# sg13g2_stdcell_hv -- thick-oxide (3.3 V) standard cells
# Generated by work/gen_lef.py from the drawn GDS; see that script
# for what is measured and what is inherited from the thin-oxide
# LEF. Uses the PDK tech LEF (sg13g2_tech.lef) layers.
VERSION 5.8 ;
BUSBITCHARS "[]" ;
DIVIDERCHAR "/" ;

SITE  CoreSiteHV
    CLASS       CORE ;
    SYMMETRY    Y ;
    SIZE        0.48 BY 7.14 ;
END  CoreSiteHV

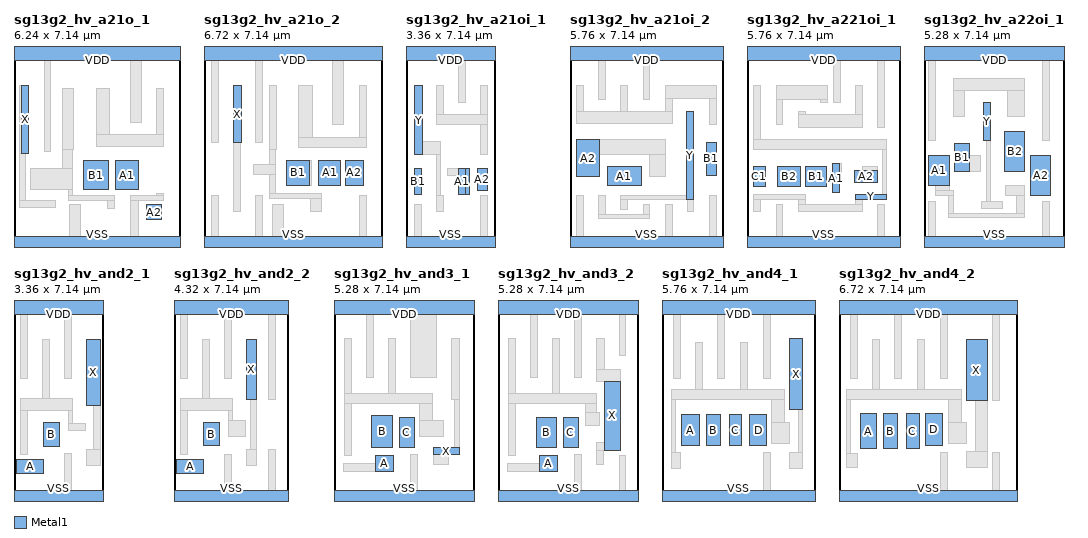
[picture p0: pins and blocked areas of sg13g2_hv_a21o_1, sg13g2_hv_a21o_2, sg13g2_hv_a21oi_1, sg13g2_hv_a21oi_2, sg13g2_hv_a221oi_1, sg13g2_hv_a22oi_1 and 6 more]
MACRO sg13g2_hv_a21o_1
  CLASS CORE ;
  ORIGIN 0 0 ;
  FOREIGN sg13g2_hv_a21o_1 0 0 ;
  SIZE 6.24 BY 7.14 ;
  SYMMETRY X Y ;
  SITE CoreSiteHV ;
  PIN A2
    DIRECTION INPUT ;
    USE SIGNAL ;
    ANTENNAMODEL OXIDE1 ;
      ANTENNAGATEAREA 1.3680 LAYER Metal1 ;
    PORT
      LAYER Metal1 ;
        RECT 4.965 0.835 5.55 1.395 ;
    END
  END A2
  PIN A1
    DIRECTION INPUT ;
    USE SIGNAL ;
    ANTENNAMODEL OXIDE1 ;
      ANTENNAGATEAREA 1.3680 LAYER Metal1 ;
    PORT
      LAYER Metal1 ;
        RECT 3.825 1.955 4.665 3.08 ;
    END
  END A1
  PIN B1
    DIRECTION INPUT ;
    USE SIGNAL ;
    ANTENNAMODEL OXIDE1 ;
      ANTENNAGATEAREA 1.3680 LAYER Metal1 ;
    PORT
      LAYER Metal1 ;
        RECT 2.63 1.955 3.54 3.08 ;
    END
  END B1
  PIN X
    DIRECTION OUTPUT ;
    USE SIGNAL ;
    ANTENNADIFFAREA 1.1662 LAYER Metal1 ;
    PORT
      LAYER Metal1 ;
        RECT 0.285 3.31 0.56 5.865 ;
    END
  END X
  PIN VDD
    DIRECTION INOUT ;
    USE POWER ;
    SHAPE ABUTMENT ;
    NETEXPR "VDD VDD!" ;
    PORT
      LAYER Metal1 ;
        RECT 0 6.825 6.24 7.36 ;
    END
  END VDD
  PIN VSS
    DIRECTION INOUT ;
    USE GROUND ;
    SHAPE ABUTMENT ;
    NETEXPR "VSS VSS!" ;
    PORT
      LAYER Metal1 ;
        RECT 0 -0.22 6.24 0.22 ;
    END
  END VSS
  OBS
      LAYER Metal1 ;
        RECT 0.205 1.315 1.545 1.575 ;
        RECT 0.205 1.575 0.445 3.31 ;
        RECT 0.205 3.31 0.285 5.865 ;
        RECT 0.635 1.97 2.215 2.745 ;
        RECT 1.13 3.415 1.39 6.825 ;
        RECT 1.825 2.745 2.215 3.49 ;
        RECT 1.825 3.49 2.235 5.78 ;
        RECT 2.055 1.575 3.775 1.735 ;
        RECT 2.055 1.735 2.215 1.97 ;
        RECT 2.095 0.22 2.49 1.395 ;
        RECT 3.085 3.585 5.615 4.05 ;
        RECT 3.085 4.05 3.605 5.78 ;
        RECT 3.51 1.255 3.775 1.575 ;
        RECT 4.365 4.485 4.785 6.825 ;
        RECT 4.395 0.22 4.695 1.575 ;
        RECT 4.395 1.575 5.605 1.74 ;
        RECT 5.355 4.05 5.615 5.78 ;
        RECT 5.36 1.74 5.605 1.84 ;
  END
END sg13g2_hv_a21o_1

MACRO sg13g2_hv_a21o_2
  CLASS CORE ;
  ORIGIN 0 0 ;
  FOREIGN sg13g2_hv_a21o_2 0 0 ;
  SIZE 6.72 BY 7.14 ;
  SYMMETRY X Y ;
  SITE CoreSiteHV ;
  PIN A2
    DIRECTION INPUT ;
    USE SIGNAL ;
    ANTENNAMODEL OXIDE1 ;
      ANTENNAGATEAREA 1.4130 LAYER Metal1 ;
    PORT
      LAYER Metal1 ;
        RECT 5.32 2.125 5.985 3.08 ;
    END
  END A2
  PIN A1
    DIRECTION INPUT ;
    USE SIGNAL ;
    ANTENNAMODEL OXIDE1 ;
      ANTENNAGATEAREA 1.4130 LAYER Metal1 ;
    PORT
      LAYER Metal1 ;
        RECT 4.3 2.125 5.14 3.08 ;
    END
  END A1
  PIN B1
    DIRECTION INPUT ;
    USE SIGNAL ;
    ANTENNAMODEL OXIDE1 ;
      ANTENNAGATEAREA 1.4130 LAYER Metal1 ;
    PORT
      LAYER Metal1 ;
        RECT 3.105 2.125 3.97 3.08 ;
    END
  END B1
  PIN X
    DIRECTION OUTPUT ;
    USE SIGNAL ;
    ANTENNADIFFAREA 1.3034 LAYER Metal1 ;
    PORT
      LAYER Metal1 ;
        RECT 1.105 3.73 1.4 5.865 ;
    END
  END X
  PIN VDD
    DIRECTION INOUT ;
    USE POWER ;
    SHAPE ABUTMENT ;
    NETEXPR "VDD VDD!" ;
    PORT
      LAYER Metal1 ;
        RECT 0 6.825 6.72 7.36 ;
    END
  END VDD
  PIN VSS
    DIRECTION INOUT ;
    USE GROUND ;
    SHAPE ABUTMENT ;
    NETEXPR "VSS VSS!" ;
    PORT
      LAYER Metal1 ;
        RECT 0 -0.22 6.72 0.22 ;
    END
  END VSS
  OBS
      LAYER Metal1 ;
        RECT 0.275 0.22 0.535 1.75 ;
        RECT 0.275 3.73 0.535 6.825 ;
        RECT 1.105 1.15 1.365 3.73 ;
        RECT 1.875 2.545 2.69 2.91 ;
        RECT 1.935 0.22 2.195 1.75 ;
        RECT 1.935 3.73 2.195 6.825 ;
        RECT 2.45 1.65 4.405 1.81 ;
        RECT 2.45 1.81 2.69 2.545 ;
        RECT 2.45 2.91 2.69 3.49 ;
        RECT 2.45 3.49 2.71 5.865 ;
        RECT 2.575 0.22 2.985 1.42 ;
        RECT 3.56 3.56 6.09 3.945 ;
        RECT 3.56 3.945 4.08 5.865 ;
        RECT 3.97 2.125 4.025 3.08 ;
        RECT 3.985 1.15 4.405 1.65 ;
        RECT 4.84 4.4 5.26 6.825 ;
        RECT 5.83 0.22 6.09 1.75 ;
        RECT 5.83 3.945 6.09 5.865 ;
  END
END sg13g2_hv_a21o_2

MACRO sg13g2_hv_a21oi_1
  CLASS CORE ;
  ORIGIN 0 0 ;
  FOREIGN sg13g2_hv_a21oi_1 0 0 ;
  SIZE 3.36 BY 7.14 ;
  SYMMETRY X Y ;
  SITE CoreSiteHV ;
  PIN VSS
    DIRECTION INOUT ;
    USE GROUND ;
    SHAPE ABUTMENT ;
    NETEXPR "VSS VSS!" ;
    PORT
      LAYER Metal1 ;
        RECT 0 -0.22 3.36 0.22 ;
    END
  END VSS
  PIN VDD
    DIRECTION INOUT ;
    USE POWER ;
    SHAPE ABUTMENT ;
    NETEXPR "VDD VDD!" ;
    PORT
      LAYER Metal1 ;
        RECT 0 6.825 3.36 7.36 ;
    END
  END VDD
  PIN A1
    DIRECTION INPUT ;
    USE SIGNAL ;
    ANTENNAMODEL OXIDE1 ;
      ANTENNAGATEAREA 1.5435 LAYER Metal1 ;
    PORT
      LAYER Metal1 ;
        RECT 1.96 1.775 2.22 2.765 ;
        RECT 2.22 1.775 2.4 2.765 ;
    END
  END A1
  PIN A2
    DIRECTION INPUT ;
    USE SIGNAL ;
    ANTENNAMODEL OXIDE1 ;
      ANTENNAGATEAREA 1.5435 LAYER Metal1 ;
    PORT
      LAYER Metal1 ;
        RECT 2.67 1.93 3.075 2.765 ;
    END
  END A2
  PIN Y
    DIRECTION OUTPUT ;
    USE SIGNAL ;
    ANTENNADIFFAREA 1.4178 LAYER Metal1 ;
    PORT
      LAYER Metal1 ;
        RECT 0.325 3.27 0.62 5.865 ;
    END
  END Y
  PIN B1
    DIRECTION INPUT ;
    USE SIGNAL ;
    ANTENNAMODEL OXIDE1 ;
      ANTENNAGATEAREA 1.5435 LAYER Metal1 ;
    PORT
      LAYER Metal1 ;
        RECT 0.325 1.775 0.6 2.765 ;
    END
  END B1
  OBS
      LAYER Metal1 ;
        RECT 0.325 0.22 0.585 1.41 ;
        RECT 0.62 3.27 1.315 3.775 ;
        RECT 1.155 1.15 1.415 1.75 ;
        RECT 1.155 1.75 1.315 3.27 ;
        RECT 1.155 4.41 3.075 4.795 ;
        RECT 1.155 4.795 1.415 5.865 ;
        RECT 1.545 2.495 1.96 2.765 ;
        RECT 1.985 5.24 2.245 6.825 ;
        RECT 2.815 0.22 3.075 1.75 ;
        RECT 2.815 3.27 3.075 4.41 ;
        RECT 2.815 4.795 3.075 5.865 ;
  END
END sg13g2_hv_a21oi_1

MACRO sg13g2_hv_a21oi_2
  CLASS CORE ;
  ORIGIN 0 0 ;
  FOREIGN sg13g2_hv_a21oi_2 0 0 ;
  SIZE 5.76 BY 7.14 ;
  SYMMETRY X Y ;
  SITE CoreSiteHV ;
  PIN VSS
    DIRECTION INOUT ;
    USE GROUND ;
    SHAPE ABUTMENT ;
    NETEXPR "VSS VSS!" ;
    PORT
      LAYER Metal1 ;
        RECT 0 -0.22 5.76 0.22 ;
    END
  END VSS
  PIN VDD
    DIRECTION INOUT ;
    USE POWER ;
    SHAPE ABUTMENT ;
    NETEXPR "VDD VDD!" ;
    PORT
      LAYER Metal1 ;
        RECT 0 6.825 5.76 7.36 ;
    END
  END VDD
  PIN B1
    DIRECTION INPUT ;
    USE SIGNAL ;
    ANTENNAMODEL OXIDE1 ;
      ANTENNAGATEAREA 3.0870 LAYER Metal1 ;
    PORT
      LAYER Metal1 ;
        RECT 5.125 2.5 5.495 3.75 ;
    END
  END B1
  PIN Y
    DIRECTION OUTPUT ;
    USE SIGNAL ;
    ANTENNADIFFAREA 1.5846 LAYER Metal1 ;
    PORT
      LAYER Metal1 ;
        RECT 4.36 1.59 4.645 4.915 ;
    END
  END Y
  PIN A2
    DIRECTION INPUT ;
    USE SIGNAL ;
    ANTENNAMODEL OXIDE1 ;
      ANTENNAGATEAREA 3.0870 LAYER Metal1 ;
    PORT
      LAYER Metal1 ;
        RECT 0.255 2.475 1.09 3.835 ;
    END
  END A2
  PIN A1
    DIRECTION INPUT ;
    USE SIGNAL ;
    ANTENNAMODEL OXIDE1 ;
      ANTENNAGATEAREA 3.0870 LAYER Metal1 ;
    PORT
      LAYER Metal1 ;
        RECT 1.405 2.125 2.685 2.825 ;
    END
  END A1
  OBS
      LAYER Metal1 ;
        RECT 0.255 0.22 0.515 1.75 ;
        RECT 0.255 4.435 3.835 4.915 ;
        RECT 0.255 4.915 0.515 5.865 ;
        RECT 1.085 0.875 3.005 1.035 ;
        RECT 1.085 1.035 1.345 1.75 ;
        RECT 1.085 5.36 1.345 6.825 ;
        RECT 1.09 3.295 3.58 3.835 ;
        RECT 1.915 1.215 2.175 1.59 ;
        RECT 1.915 1.59 4.36 1.75 ;
        RECT 1.915 4.915 2.175 5.865 ;
        RECT 2.745 1.035 3.005 1.41 ;
        RECT 2.745 5.36 3.005 6.825 ;
        RECT 3 2.475 3.58 3.295 ;
        RECT 3.575 0.22 3.835 1.41 ;
        RECT 3.575 4.915 3.835 5.395 ;
        RECT 3.575 5.395 5.495 5.865 ;
        RECT 4.405 1.15 4.645 1.59 ;
        RECT 5.235 0.22 5.495 1.75 ;
        RECT 5.235 4.425 5.495 5.395 ;
  END
END sg13g2_hv_a21oi_2

MACRO sg13g2_hv_a221oi_1
  CLASS CORE ;
  ORIGIN 0 0 ;
  FOREIGN sg13g2_hv_a221oi_1 0 0 ;
  SIZE 5.76 BY 7.14 ;
  SYMMETRY X Y ;
  SITE CoreSiteHV ;
  PIN VDD
    DIRECTION INOUT ;
    USE POWER ;
    SHAPE ABUTMENT ;
    NETEXPR "VDD VDD!" ;
    PORT
      LAYER Metal1 ;
        RECT 0 6.825 5.76 7.36 ;
    END
  END VDD
  PIN VSS
    DIRECTION INOUT ;
    USE GROUND ;
    SHAPE ABUTMENT ;
    NETEXPR "VSS VSS!" ;
    PORT
      LAYER Metal1 ;
        RECT 0 -0.22 5.76 0.22 ;
    END
  END VSS
  PIN B2
    DIRECTION INPUT ;
    USE SIGNAL ;
    ANTENNAMODEL OXIDE1 ;
      ANTENNAGATEAREA 1.5435 LAYER Metal1 ;
    PORT
      LAYER Metal1 ;
        RECT 1.15 2.075 2 2.825 ;
    END
  END B2
  PIN C1
    DIRECTION INPUT ;
    USE SIGNAL ;
    ANTENNAMODEL OXIDE1 ;
      ANTENNAGATEAREA 1.5435 LAYER Metal1 ;
    PORT
      LAYER Metal1 ;
        RECT 0.25 2.075 0.685 2.825 ;
    END
  END C1
  PIN B1
    DIRECTION INPUT ;
    USE SIGNAL ;
    ANTENNAMODEL OXIDE1 ;
      ANTENNAGATEAREA 1.5435 LAYER Metal1 ;
    PORT
      LAYER Metal1 ;
        RECT 2.18 2.075 3 2.825 ;
    END
  END B1
  PIN A1
    DIRECTION INPUT ;
    USE SIGNAL ;
    ANTENNAMODEL OXIDE1 ;
      ANTENNAGATEAREA 1.5435 LAYER Metal1 ;
    PORT
      LAYER Metal1 ;
        RECT 3.22 1.87 3.475 2.935 ;
    END
  END A1
  PIN Y
    DIRECTION OUTPUT ;
    USE SIGNAL ;
    ANTENNADIFFAREA 1.6694 LAYER Metal1 ;
    PORT
      LAYER Metal1 ;
        RECT 4.09 1.59 5.26 1.8 ;
    END
  END Y
  PIN A2
    DIRECTION INPUT ;
    USE SIGNAL ;
    ANTENNAMODEL OXIDE1 ;
      ANTENNAGATEAREA 1.5435 LAYER Metal1 ;
    PORT
      LAYER Metal1 ;
        RECT 4.04 2.225 4.92 2.675 ;
    END
  END A2
  OBS
      LAYER Metal1 ;
        RECT 0.26 1.15 0.52 1.59 ;
        RECT 0.26 1.59 2.18 1.8 ;
        RECT 0.26 3.475 5.26 3.86 ;
        RECT 0.26 3.86 0.52 5.865 ;
        RECT 1.09 0.22 1.35 1.41 ;
        RECT 1.09 4.425 1.35 5.36 ;
        RECT 1.09 5.36 3.01 5.865 ;
        RECT 1.92 1.15 4.35 1.41 ;
        RECT 1.92 1.41 2.18 1.59 ;
        RECT 1.92 4.29 4.35 4.795 ;
        RECT 1.92 4.795 2.18 4.915 ;
        RECT 2.75 5.24 3.01 5.36 ;
        RECT 3.26 5.24 3.52 6.825 ;
        RECT 3.475 2.585 3.54 2.935 ;
        RECT 4.09 1.41 4.35 1.59 ;
        RECT 4.09 4.795 4.35 5.865 ;
        RECT 4.335 2.675 4.92 2.825 ;
        RECT 4.92 0.22 5.18 1.41 ;
        RECT 4.92 4.29 5.18 6.825 ;
        RECT 5.1 1.8 5.26 3.475 ;
  END
END sg13g2_hv_a221oi_1

MACRO sg13g2_hv_a22oi_1
  CLASS CORE ;
  ORIGIN 0 0 ;
  FOREIGN sg13g2_hv_a22oi_1 0 0 ;
  SIZE 5.28 BY 7.14 ;
  SYMMETRY X Y ;
  SITE CoreSiteHV ;
  PIN Y
    DIRECTION OUTPUT ;
    USE SIGNAL ;
    ANTENNADIFFAREA 2.3324 LAYER Metal1 ;
    PORT
      LAYER Metal1 ;
        RECT 2.22 3.8 2.51 5.24 ;
    END
  END Y
  PIN B1
    DIRECTION INPUT ;
    USE SIGNAL ;
    ANTENNAMODEL OXIDE1 ;
      ANTENNAGATEAREA 1.5435 LAYER Metal1 ;
    PORT
      LAYER Metal1 ;
        RECT 1.14 2.66 1.695 3.69 ;
    END
  END B1
  PIN B2
    DIRECTION INPUT ;
    USE SIGNAL ;
    ANTENNAMODEL OXIDE1 ;
      ANTENNAGATEAREA 1.5435 LAYER Metal1 ;
    PORT
      LAYER Metal1 ;
        RECT 3.04 2.645 3.78 4.135 ;
    END
  END B2
  PIN A2
    DIRECTION INPUT ;
    USE SIGNAL ;
    ANTENNAMODEL OXIDE1 ;
      ANTENNAGATEAREA 1.5435 LAYER Metal1 ;
    PORT
      LAYER Metal1 ;
        RECT 4.02 1.76 4.74 3.25 ;
    END
  END A2
  PIN A1
    DIRECTION INPUT ;
    USE SIGNAL ;
    ANTENNAMODEL OXIDE1 ;
      ANTENNAGATEAREA 1.5435 LAYER Metal1 ;
    PORT
      LAYER Metal1 ;
        RECT 0.17 2.125 0.96 3.25 ;
    END
  END A1
  PIN VDD
    DIRECTION INOUT ;
    USE POWER ;
    SHAPE ABUTMENT ;
    NETEXPR "VDD VDD!" ;
    PORT
      LAYER Metal1 ;
        RECT 0 6.825 5.28 7.36 ;
    END
  END VDD
  PIN VSS
    DIRECTION INOUT ;
    USE GROUND ;
    SHAPE ABUTMENT ;
    NETEXPR "VSS VSS!" ;
    PORT
      LAYER Metal1 ;
        RECT 0 -0.22 5.28 0.22 ;
    END
  END VSS
  OBS
      LAYER Metal1 ;
        RECT 0.18 0.22 0.44 1.53 ;
        RECT 0.18 3.8 0.45 6.825 ;
        RECT 0.42 1.76 1.1 1.92 ;
        RECT 0.42 1.92 0.96 2.125 ;
        RECT 0.905 0.91 3.79 1.07 ;
        RECT 0.905 1.07 1.1 1.76 ;
        RECT 1.12 4.71 1.505 5.685 ;
        RECT 1.12 5.685 3.78 6.15 ;
        RECT 1.695 2.66 2.125 3.25 ;
        RECT 2.16 1.27 2.955 1.53 ;
        RECT 2.33 1.53 2.51 3.8 ;
        RECT 3.065 1.76 3.79 2.125 ;
        RECT 3.14 4.71 3.78 5.685 ;
        RECT 3.485 1.07 3.79 1.76 ;
        RECT 4.46 0.22 4.72 1.53 ;
        RECT 4.46 3.8 4.72 6.825 ;
  END
END sg13g2_hv_a22oi_1

MACRO sg13g2_hv_and2_1
  CLASS CORE ;
  ORIGIN 0 0 ;
  FOREIGN sg13g2_hv_and2_1 0 0 ;
  SIZE 3.36 BY 7.14 ;
  SYMMETRY X Y ;
  SITE CoreSiteHV ;
  PIN A
    DIRECTION INPUT ;
    USE SIGNAL ;
    ANTENNAMODEL OXIDE1 ;
      ANTENNAGATEAREA 1.1947 LAYER Metal1 ;
    PORT
      LAYER Metal1 ;
        RECT 0.105 0.835 1.1 1.39 ;
    END
  END A
  PIN B
    DIRECTION INPUT ;
    USE SIGNAL ;
    ANTENNAMODEL OXIDE1 ;
      ANTENNAGATEAREA 1.1947 LAYER Metal1 ;
    PORT
      LAYER Metal1 ;
        RECT 1.1 1.865 1.725 2.745 ;
    END
  END B
  PIN X
    DIRECTION OUTPUT ;
    USE SIGNAL ;
    ANTENNADIFFAREA 1.1662 LAYER Metal1 ;
    PORT
      LAYER Metal1 ;
        RECT 2.735 3.415 3.235 5.865 ;
    END
  END X
  PIN VDD
    DIRECTION INOUT ;
    USE POWER ;
    SHAPE ABUTMENT ;
    NETEXPR "VDD VDD!" ;
    PORT
      LAYER Metal1 ;
        RECT 0 6.825 3.36 7.36 ;
    END
  END VDD
  PIN VSS
    DIRECTION INOUT ;
    USE GROUND ;
    SHAPE ABUTMENT ;
    NETEXPR "VSS VSS!" ;
    PORT
      LAYER Metal1 ;
        RECT 0 -0.22 3.36 0.22 ;
    END
  END VSS
  OBS
      LAYER Metal1 ;
        RECT 0.245 1.57 0.505 3.2 ;
        RECT 0.245 3.2 2.2 3.655 ;
        RECT 0.245 4.425 0.505 6.825 ;
        RECT 1.075 3.655 1.335 5.865 ;
        RECT 1.905 0.22 2.165 1.585 ;
        RECT 1.905 4.425 2.165 6.825 ;
        RECT 2.04 2.48 2.7 2.74 ;
        RECT 2.04 2.74 2.2 3.2 ;
        RECT 2.735 1.15 3.235 1.75 ;
        RECT 3 1.75 3.235 3.415 ;
  END
END sg13g2_hv_and2_1

MACRO sg13g2_hv_and2_2
  CLASS CORE ;
  ORIGIN 0 0 ;
  FOREIGN sg13g2_hv_and2_2 0 0 ;
  SIZE 4.32 BY 7.14 ;
  SYMMETRY X Y ;
  SITE CoreSiteHV ;
  PIN A
    DIRECTION INPUT ;
    USE SIGNAL ;
    ANTENNAMODEL OXIDE1 ;
      ANTENNAGATEAREA 1.1947 LAYER Metal1 ;
    PORT
      LAYER Metal1 ;
        RECT 0.105 0.835 1.1 1.39 ;
    END
  END A
  PIN B
    DIRECTION INPUT ;
    USE SIGNAL ;
    ANTENNAMODEL OXIDE1 ;
      ANTENNAGATEAREA 1.1947 LAYER Metal1 ;
    PORT
      LAYER Metal1 ;
        RECT 1.1 1.9 1.725 2.745 ;
    END
  END B
  PIN X
    DIRECTION OUTPUT ;
    USE SIGNAL ;
    ANTENNADIFFAREA 1.3034 LAYER Metal1 ;
    PORT
      LAYER Metal1 ;
        RECT 2.735 3.61 3.09 5.865 ;
    END
  END X
  PIN VDD
    DIRECTION INOUT ;
    USE POWER ;
    SHAPE ABUTMENT ;
    NETEXPR "VDD VDD!" ;
    PORT
      LAYER Metal1 ;
        RECT 0 6.825 4.32 7.36 ;
    END
  END VDD
  PIN VSS
    DIRECTION INOUT ;
    USE GROUND ;
    SHAPE ABUTMENT ;
    NETEXPR "VSS VSS!" ;
    PORT
      LAYER Metal1 ;
        RECT 0 -0.22 4.32 0.22 ;
    END
  END VSS
  OBS
      LAYER Metal1 ;
        RECT 0.245 1.57 0.505 3.2 ;
        RECT 0.245 3.2 2.2 3.655 ;
        RECT 0.245 4.425 0.505 6.825 ;
        RECT 1.075 3.655 1.335 5.865 ;
        RECT 1.905 0.22 2.165 1.575 ;
        RECT 1.905 4.425 2.165 6.825 ;
        RECT 2.04 2.225 2.7 2.825 ;
        RECT 2.04 2.825 2.2 3.2 ;
        RECT 2.735 1.15 3.09 1.75 ;
        RECT 2.88 1.75 3.09 3.61 ;
        RECT 3.565 0.22 3.825 1.75 ;
        RECT 3.565 3.61 3.825 6.825 ;
  END
END sg13g2_hv_and2_2

MACRO sg13g2_hv_and3_1
  CLASS CORE ;
  ORIGIN 0 0 ;
  FOREIGN sg13g2_hv_and3_1 0 0 ;
  SIZE 5.28 BY 7.14 ;
  SYMMETRY X Y ;
  SITE CoreSiteHV ;
  PIN X
    DIRECTION OUTPUT ;
    USE SIGNAL ;
    ANTENNADIFFAREA 1.1662 LAYER Metal1 ;
    PORT
      LAYER Metal1 ;
        RECT 3.73 1.555 4.705 1.815 ;
    END
  END X
  PIN A
    DIRECTION INPUT ;
    USE SIGNAL ;
    ANTENNAMODEL OXIDE1 ;
      ANTENNAGATEAREA 1.1947 LAYER Metal1 ;
    PORT
      LAYER Metal1 ;
        RECT 1.545 0.905 2.23 1.52 ;
    END
  END A
  PIN B
    DIRECTION INPUT ;
    USE SIGNAL ;
    ANTENNAMODEL OXIDE1 ;
      ANTENNAGATEAREA 1.1947 LAYER Metal1 ;
    PORT
      LAYER Metal1 ;
        RECT 1.41 1.83 2.2 3.03 ;
    END
  END B
  PIN C
    DIRECTION INPUT ;
    USE SIGNAL ;
    ANTENNAMODEL OXIDE1 ;
      ANTENNAGATEAREA 1.1947 LAYER Metal1 ;
    PORT
      LAYER Metal1 ;
        RECT 2.465 1.83 3.02 2.96 ;
    END
  END C
  PIN VDD
    DIRECTION INOUT ;
    USE POWER ;
    SHAPE ABUTMENT ;
    NETEXPR "VDD VDD!" ;
    PORT
      LAYER Metal1 ;
        RECT 0 6.825 5.28 7.36 ;
    END
  END VDD
  PIN VSS
    DIRECTION INOUT ;
    USE GROUND ;
    SHAPE ABUTMENT ;
    NETEXPR "VSS VSS!" ;
    PORT
      LAYER Metal1 ;
        RECT 0 -0.22 5.28 0.22 ;
    END
  END VSS
  OBS
      LAYER Metal1 ;
        RECT 0.35 0.905 1.545 1.22 ;
        RECT 0.4 1.52 0.66 3.465 ;
        RECT 0.4 3.465 3.69 3.85 ;
        RECT 0.4 3.85 0.66 5.9 ;
        RECT 1.23 4.45 1.49 6.825 ;
        RECT 2.06 3.85 2.32 5.9 ;
        RECT 2.89 0.22 3.15 1.57 ;
        RECT 2.89 4.46 3.84 6.825 ;
        RECT 3.205 2.225 4.1 2.825 ;
        RECT 3.205 2.825 3.69 3.465 ;
        RECT 3.73 1.2 4.29 1.555 ;
        RECT 4.42 3.645 4.705 5.9 ;
        RECT 4.535 1.815 4.705 3.645 ;
  END
END sg13g2_hv_and3_1

MACRO sg13g2_hv_and3_2
  CLASS CORE ;
  ORIGIN 0 0 ;
  FOREIGN sg13g2_hv_and3_2 0 0 ;
  SIZE 5.28 BY 7.14 ;
  SYMMETRY X Y ;
  SITE CoreSiteHV ;
  PIN X
    DIRECTION OUTPUT ;
    USE SIGNAL ;
    ANTENNADIFFAREA 1.3034 LAYER Metal1 ;
    PORT
      LAYER Metal1 ;
        RECT 4.02 1.72 4.62 4.305 ;
    END
  END X
  PIN A
    DIRECTION INPUT ;
    USE SIGNAL ;
    ANTENNAMODEL OXIDE1 ;
      ANTENNAGATEAREA 1.1947 LAYER Metal1 ;
    PORT
      LAYER Metal1 ;
        RECT 1.545 0.905 2.23 1.52 ;
    END
  END A
  PIN B
    DIRECTION INPUT ;
    USE SIGNAL ;
    ANTENNAMODEL OXIDE1 ;
      ANTENNAGATEAREA 1.1947 LAYER Metal1 ;
    PORT
      LAYER Metal1 ;
        RECT 1.445 1.83 2.2 2.96 ;
    END
  END B
  PIN C
    DIRECTION INPUT ;
    USE SIGNAL ;
    ANTENNAMODEL OXIDE1 ;
      ANTENNAGATEAREA 1.1947 LAYER Metal1 ;
    PORT
      LAYER Metal1 ;
        RECT 2.45 1.83 3.02 2.96 ;
    END
  END C
  PIN VDD
    DIRECTION INOUT ;
    USE POWER ;
    SHAPE ABUTMENT ;
    NETEXPR "VDD VDD!" ;
    PORT
      LAYER Metal1 ;
        RECT 0 6.825 5.28 7.36 ;
    END
  END VDD
  PIN VSS
    DIRECTION INOUT ;
    USE GROUND ;
    SHAPE ABUTMENT ;
    NETEXPR "VSS VSS!" ;
    PORT
      LAYER Metal1 ;
        RECT 0 -0.22 5.28 0.22 ;
    END
  END VSS
  OBS
      LAYER Metal1 ;
        RECT 0.35 0.905 1.545 1.22 ;
        RECT 0.4 1.52 0.66 3.465 ;
        RECT 0.4 3.465 3.71 3.85 ;
        RECT 0.4 3.85 0.66 5.9 ;
        RECT 1.23 4.46 1.49 6.825 ;
        RECT 2.055 3.85 2.315 5.9 ;
        RECT 2.89 0.22 3.15 1.57 ;
        RECT 2.89 4.46 3.15 6.825 ;
        RECT 3.28 2.645 3.81 3.15 ;
        RECT 3.28 3.15 3.71 3.465 ;
        RECT 3.715 4.305 4.62 4.735 ;
        RECT 3.715 4.735 3.985 5.9 ;
        RECT 3.72 1.2 3.98 1.72 ;
        RECT 3.72 1.72 4.02 2.025 ;
        RECT 4.55 0.22 4.81 1.52 ;
        RECT 4.55 5.275 4.81 6.825 ;
  END
END sg13g2_hv_and3_2

MACRO sg13g2_hv_and4_1
  CLASS CORE ;
  ORIGIN 0 0 ;
  FOREIGN sg13g2_hv_and4_1 0 0 ;
  SIZE 5.76 BY 7.14 ;
  SYMMETRY X Y ;
  SITE CoreSiteHV ;
  PIN A
    DIRECTION INPUT ;
    USE SIGNAL ;
    ANTENNAMODEL OXIDE1 ;
      ANTENNAGATEAREA 1.1947 LAYER Metal1 ;
    PORT
      LAYER Metal1 ;
        RECT 0.745 1.885 1.4 3.045 ;
    END
  END A
  PIN B
    DIRECTION INPUT ;
    USE SIGNAL ;
    ANTENNAMODEL OXIDE1 ;
      ANTENNAGATEAREA 1.1947 LAYER Metal1 ;
    PORT
      LAYER Metal1 ;
        RECT 1.68 1.885 2.2 3.045 ;
    END
  END B
  PIN C
    DIRECTION INPUT ;
    USE SIGNAL ;
    ANTENNAMODEL OXIDE1 ;
      ANTENNAGATEAREA 1.1947 LAYER Metal1 ;
    PORT
      LAYER Metal1 ;
        RECT 2.525 1.885 3.005 3.045 ;
    END
  END C
  PIN D
    DIRECTION INPUT ;
    USE SIGNAL ;
    ANTENNAMODEL OXIDE1 ;
      ANTENNAGATEAREA 1.1947 LAYER Metal1 ;
    PORT
      LAYER Metal1 ;
        RECT 3.275 1.88 3.945 3.08 ;
    END
  END D
  PIN X
    DIRECTION OUTPUT ;
    USE SIGNAL ;
    ANTENNADIFFAREA 1.1662 LAYER Metal1 ;
    PORT
      LAYER Metal1 ;
        RECT 4.805 3.25 5.285 5.91 ;
    END
  END X
  PIN VDD
    DIRECTION INOUT ;
    USE POWER ;
    SHAPE ABUTMENT ;
    NETEXPR "VDD VDD!" ;
    PORT
      LAYER Metal1 ;
        RECT 0 6.825 5.76 7.36 ;
    END
  END VDD
  PIN VSS
    DIRECTION INOUT ;
    USE GROUND ;
    SHAPE ABUTMENT ;
    NETEXPR "VSS VSS!" ;
    PORT
      LAYER Metal1 ;
        RECT 0 -0.22 5.76 0.22 ;
    END
  END VSS
  OBS
      LAYER Metal1 ;
        RECT 0.355 1.04 0.685 1.64 ;
        RECT 0.355 1.64 0.525 3.61 ;
        RECT 0.355 3.61 4.61 3.99 ;
        RECT 0.425 4.425 0.685 6.825 ;
        RECT 1.255 3.99 1.515 5.78 ;
        RECT 2.085 4.425 2.345 6.825 ;
        RECT 2.945 3.99 3.205 5.77 ;
        RECT 3.82 4.425 4.08 6.825 ;
        RECT 3.83 0.22 4.095 1.64 ;
        RECT 4.13 1.97 4.805 2.745 ;
        RECT 4.13 2.745 4.61 3.61 ;
        RECT 4.805 1.04 5.285 1.64 ;
        RECT 5.125 1.64 5.285 3.25 ;
  END
END sg13g2_hv_and4_1

MACRO sg13g2_hv_and4_2
  CLASS CORE ;
  ORIGIN 0 0 ;
  FOREIGN sg13g2_hv_and4_2 0 0 ;
  SIZE 6.72 BY 7.14 ;
  SYMMETRY X Y ;
  SITE CoreSiteHV ;
  PIN A
    DIRECTION INPUT ;
    USE SIGNAL ;
    ANTENNAMODEL OXIDE1 ;
      ANTENNAGATEAREA 1.1947 LAYER Metal1 ;
    PORT
      LAYER Metal1 ;
        RECT 0.815 1.78 1.4 3.105 ;
    END
  END A
  PIN B
    DIRECTION INPUT ;
    USE SIGNAL ;
    ANTENNAMODEL OXIDE1 ;
      ANTENNAGATEAREA 1.1947 LAYER Metal1 ;
    PORT
      LAYER Metal1 ;
        RECT 1.68 1.78 2.205 3.105 ;
    END
  END B
  PIN C
    DIRECTION INPUT ;
    USE SIGNAL ;
    ANTENNAMODEL OXIDE1 ;
      ANTENNAGATEAREA 1.1947 LAYER Metal1 ;
    PORT
      LAYER Metal1 ;
        RECT 2.525 1.78 3.02 3.105 ;
    END
  END C
  PIN D
    DIRECTION INPUT ;
    USE SIGNAL ;
    ANTENNAMODEL OXIDE1 ;
      ANTENNAGATEAREA 1.1947 LAYER Metal1 ;
    PORT
      LAYER Metal1 ;
        RECT 3.24 1.89 3.895 3.105 ;
    END
  END D
  PIN X
    DIRECTION OUTPUT ;
    USE SIGNAL ;
    ANTENNADIFFAREA 1.3034 LAYER Metal1 ;
    PORT
      LAYER Metal1 ;
        RECT 4.805 3.585 5.565 5.865 ;
    END
  END X
  PIN VDD
    DIRECTION INOUT ;
    USE POWER ;
    SHAPE ABUTMENT ;
    NETEXPR "VDD VDD!" ;
    PORT
      LAYER Metal1 ;
        RECT 0 6.825 6.72 7.36 ;
    END
  END VDD
  PIN VSS
    DIRECTION INOUT ;
    USE GROUND ;
    SHAPE ABUTMENT ;
    NETEXPR "VSS VSS!" ;
    PORT
      LAYER Metal1 ;
        RECT 0 -0.22 6.72 0.22 ;
    END
  END VSS
  OBS
      LAYER Metal1 ;
        RECT 0.265 1.075 0.685 1.6 ;
        RECT 0.265 1.6 0.435 3.61 ;
        RECT 0.265 3.61 4.61 3.99 ;
        RECT 0.425 4.425 0.685 6.825 ;
        RECT 1.255 3.99 1.515 5.865 ;
        RECT 2.085 4.425 2.345 6.825 ;
        RECT 2.945 3.99 3.205 5.865 ;
        RECT 3.82 4.425 4.08 6.825 ;
        RECT 3.83 0.22 4.095 1.64 ;
        RECT 4.13 1.97 4.805 2.745 ;
        RECT 4.13 2.745 4.61 3.61 ;
        RECT 4.805 1.07 5.565 1.69 ;
        RECT 5.125 1.69 5.565 3.585 ;
        RECT 5.785 0.22 6.045 1.64 ;
        RECT 5.785 3.585 6.045 6.825 ;
  END
END sg13g2_hv_and4_2

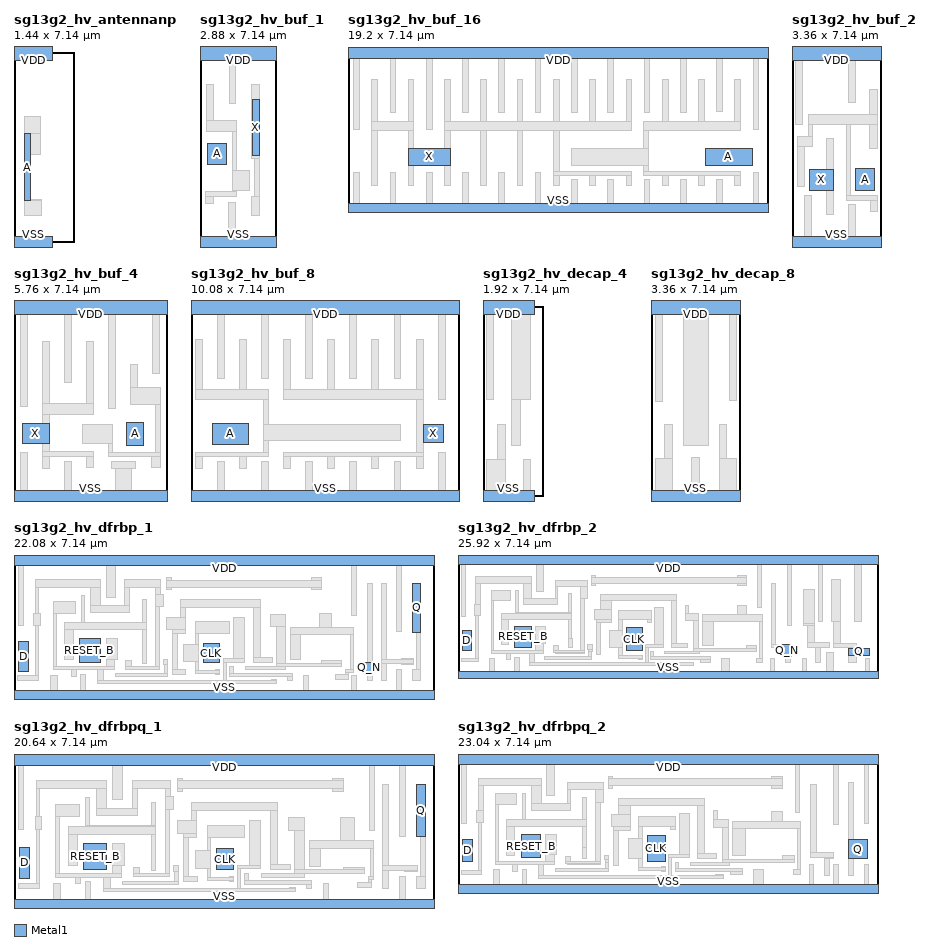
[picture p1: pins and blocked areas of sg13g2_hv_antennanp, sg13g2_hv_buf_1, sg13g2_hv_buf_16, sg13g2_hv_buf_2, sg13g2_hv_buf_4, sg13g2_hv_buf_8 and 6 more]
MACRO sg13g2_hv_antennanp
  CLASS CORE ANTENNACELL ;
  ORIGIN 0 0 ;
  FOREIGN sg13g2_hv_antennanp 0 0 ;
  SIZE 1.44 BY 7.14 ;
  SYMMETRY X Y ;
  SITE CoreSiteHV ;
  PIN VDD
    DIRECTION INOUT ;
    USE POWER ;
    SHAPE ABUTMENT ;
    NETEXPR "VDD VDD!" ;
    PORT
      LAYER Metal1 ;
        RECT 0 6.825 1.44 7.36 ;
    END
  END VDD
  PIN VSS
    DIRECTION INOUT ;
    USE GROUND ;
    SHAPE ABUTMENT ;
    NETEXPR "VSS VSS!" ;
    PORT
      LAYER Metal1 ;
        RECT 0 -0.22 1.44 0.22 ;
    END
  END VSS
  PIN A
    DIRECTION INPUT ;
    USE SIGNAL ;
    ANTENNADIFFAREA 2.0154 LAYER Metal1 ;
    PORT
      LAYER Metal1 ;
        RECT 0.38 1.56 0.63 4.065 ;
    END
  END A
  OBS
      LAYER Metal1 ;
        RECT 0.38 4.065 0.98 4.71 ;
        RECT 0.405 1 1.05 1.56 ;
        RECT 0.63 1.56 1.05 1.59 ;
        RECT 0.63 3.27 0.98 4.065 ;
  END
END sg13g2_hv_antennanp

MACRO sg13g2_hv_buf_1
  CLASS CORE ;
  ORIGIN 0 0 ;
  FOREIGN sg13g2_hv_buf_1 0 0 ;
  SIZE 2.88 BY 7.14 ;
  SYMMETRY X Y ;
  SITE CoreSiteHV ;
  PIN A
    DIRECTION INPUT ;
    USE SIGNAL ;
    ANTENNAMODEL OXIDE1 ;
      ANTENNAGATEAREA 1.1542 LAYER Metal1 ;
    PORT
      LAYER Metal1 ;
        RECT 0.285 2.91 1 3.705 ;
    END
  END A
  PIN X
    DIRECTION OUTPUT ;
    USE SIGNAL ;
    ANTENNADIFFAREA 1.1662 LAYER Metal1 ;
    PORT
      LAYER Metal1 ;
        RECT 1.955 3.25 2.22 5.35 ;
        RECT 1.955 3.25 2.22 5.35 ;
    END
  END X
  PIN VDD
    DIRECTION INOUT ;
    USE POWER ;
    SHAPE ABUTMENT ;
    NETEXPR "VDD VDD!" ;
    PORT
      LAYER Metal1 ;
        RECT 0 6.825 2.88 7.36 ;
    END
  END VDD
  PIN VSS
    DIRECTION INOUT ;
    USE GROUND ;
    SHAPE ABUTMENT ;
    NETEXPR "VSS VSS!" ;
    PORT
      LAYER Metal1 ;
        RECT 0 -0.22 2.88 0.22 ;
    END
  END VSS
  OBS
      LAYER Metal1 ;
        RECT 0.215 1.43 0.515 1.72 ;
        RECT 0.215 1.72 1.39 1.895 ;
        RECT 0.24 4.135 1.39 4.57 ;
        RECT 0.24 4.57 0.51 5.91 ;
        RECT 1.085 0.22 1.335 1.5 ;
        RECT 1.09 5.215 1.35 6.825 ;
        RECT 1.22 1.895 1.39 1.93 ;
        RECT 1.22 1.93 1.865 2.705 ;
        RECT 1.22 2.705 1.39 4.135 ;
        RECT 1.94 3.13 2.24 3.25 ;
        RECT 1.94 3.25 1.955 5.35 ;
        RECT 1.94 5.35 2.24 5.91 ;
        RECT 1.95 0.98 2.24 1.72 ;
        RECT 2.05 1.72 2.24 3.13 ;
        RECT 2.22 3.25 2.24 5.35 ;
  END
END sg13g2_hv_buf_1

MACRO sg13g2_hv_buf_16
  CLASS CORE ;
  ORIGIN 0 0 ;
  FOREIGN sg13g2_hv_buf_16 0 0 ;
  SIZE 19.2 BY 7.14 ;
  SYMMETRY X Y ;
  SITE CoreSiteHV ;
  PIN X
    DIRECTION OUTPUT ;
    USE SIGNAL ;
    ANTENNADIFFAREA 10.4272 LAYER Metal1 ;
    PORT
      LAYER Metal1 ;
        RECT 2.75 1.95 4.67 2.725 ;
    END
  END X
  PIN A
    DIRECTION INPUT ;
    USE SIGNAL ;
    ANTENNAMODEL OXIDE1 ;
      ANTENNAGATEAREA 9.2610 LAYER Metal1 ;
    PORT
      LAYER Metal1 ;
        RECT 16.34 1.95 18.48 2.725 ;
    END
  END A
  PIN VDD
    DIRECTION INOUT ;
    USE POWER ;
    SHAPE ABUTMENT ;
    NETEXPR "VDD VDD!" ;
    PORT
      LAYER Metal1 ;
        RECT 0 6.825 19.2 7.36 ;
    END
  END VDD
  PIN VSS
    DIRECTION INOUT ;
    USE GROUND ;
    SHAPE ABUTMENT ;
    NETEXPR "VSS VSS!" ;
    PORT
      LAYER Metal1 ;
        RECT 0 -0.22 19.2 0.22 ;
    END
  END VSS
  OBS
      LAYER Metal1 ;
        RECT 0.26 0.22 0.52 1.64 ;
        RECT 0.26 3.61 0.52 6.825 ;
        RECT 1.09 1.04 1.35 3.56 ;
        RECT 1.09 3.56 3.01 3.945 ;
        RECT 1.09 3.945 1.35 5.865 ;
        RECT 1.92 0.22 2.18 1.64 ;
        RECT 1.92 4.375 2.18 6.825 ;
        RECT 2.75 1.04 3.01 1.95 ;
        RECT 2.75 2.725 3.01 3.56 ;
        RECT 2.75 3.945 3.01 5.865 ;
        RECT 3.58 0.22 3.84 1.64 ;
        RECT 3.58 3.61 3.84 6.825 ;
        RECT 4.41 1.04 4.67 1.95 ;
        RECT 4.41 2.725 4.67 3.56 ;
        RECT 4.41 3.56 12.97 3.945 ;
        RECT 4.41 3.945 4.67 5.865 ;
        RECT 5.24 0.22 5.5 1.625 ;
        RECT 5.24 4.375 5.5 6.825 ;
        RECT 6.07 1.04 6.33 3.56 ;
        RECT 6.07 3.945 6.33 5.865 ;
        RECT 6.9 0.22 7.16 1.625 ;
        RECT 6.9 4.375 7.16 6.825 ;
        RECT 7.73 1.04 7.99 3.56 ;
        RECT 7.73 3.945 7.99 5.865 ;
        RECT 8.56 0.22 8.82 1.625 ;
        RECT 8.56 4.375 8.82 6.825 ;
        RECT 9.39 1.04 9.65 1.48 ;
        RECT 9.39 1.48 12.97 1.65 ;
        RECT 9.39 1.65 9.65 3.56 ;
        RECT 9.39 3.945 9.65 5.865 ;
        RECT 10.22 0.22 10.48 1.3 ;
        RECT 10.22 4.375 10.48 6.825 ;
        RECT 10.235 1.95 13.715 2.725 ;
        RECT 11.05 1.04 11.31 1.48 ;
        RECT 11.05 3.945 11.31 5.865 ;
        RECT 11.88 0.22 12.14 1.3 ;
        RECT 11.88 4.375 12.14 6.825 ;
        RECT 12.71 1.04 12.97 1.48 ;
        RECT 12.71 3.945 12.97 5.865 ;
        RECT 13.505 1.48 17.95 1.65 ;
        RECT 13.505 1.65 13.715 1.95 ;
        RECT 13.505 2.725 13.715 3.56 ;
        RECT 13.505 3.56 17.95 3.945 ;
        RECT 13.54 0.22 13.805 1.3 ;
        RECT 13.54 4.375 13.8 6.825 ;
        RECT 14.37 1.04 14.63 1.48 ;
        RECT 14.37 3.945 14.63 5.865 ;
        RECT 15.2 0.22 15.46 1.3 ;
        RECT 15.2 4.375 15.46 6.825 ;
        RECT 16.03 1.04 16.29 1.48 ;
        RECT 16.03 3.945 16.29 5.865 ;
        RECT 16.86 0.22 17.12 1.3 ;
        RECT 16.86 4.39 17.12 6.825 ;
        RECT 17.69 1.04 17.95 1.48 ;
        RECT 17.69 3.945 17.95 5.865 ;
        RECT 18.52 0.22 18.78 1.64 ;
        RECT 18.52 3.595 18.78 6.825 ;
  END
END sg13g2_hv_buf_16

MACRO sg13g2_hv_buf_2
  CLASS CORE ;
  ORIGIN 0 0 ;
  FOREIGN sg13g2_hv_buf_2 0 0 ;
  SIZE 3.36 BY 7.14 ;
  SYMMETRY X Y ;
  SITE CoreSiteHV ;
  PIN A
    DIRECTION INPUT ;
    USE SIGNAL ;
    ANTENNAMODEL OXIDE1 ;
      ANTENNAGATEAREA 1.3680 LAYER Metal1 ;
    PORT
      LAYER Metal1 ;
        RECT 2.395 1.92 3.1 2.745 ;
    END
  END A
  PIN X
    DIRECTION OUTPUT ;
    USE SIGNAL ;
    ANTENNADIFFAREA 1.3034 LAYER Metal1 ;
    PORT
      LAYER Metal1 ;
        RECT 0.67 1.95 1.555 2.725 ;
    END
  END X
  PIN VDD
    DIRECTION INOUT ;
    USE POWER ;
    SHAPE ABUTMENT ;
    NETEXPR "VDD VDD!" ;
    PORT
      LAYER Metal1 ;
        RECT 0 6.825 3.36 7.36 ;
    END
  END VDD
  PIN VSS
    DIRECTION INOUT ;
    USE GROUND ;
    SHAPE ABUTMENT ;
    NETEXPR "VSS VSS!" ;
    PORT
      LAYER Metal1 ;
        RECT 0 -0.22 3.36 0.22 ;
    END
  END VSS
  OBS
      LAYER Metal1 ;
        RECT 0.15 4.425 0.41 6.825 ;
        RECT 0.225 2.075 0.485 3.595 ;
        RECT 0.225 3.595 0.765 3.98 ;
        RECT 0.465 0.22 0.725 1.74 ;
        RECT 0.605 3.98 0.765 4.4 ;
        RECT 0.605 4.4 3.22 4.785 ;
        RECT 1.295 1.04 1.555 1.95 ;
        RECT 1.295 2.725 1.555 3.895 ;
        RECT 2.03 1.575 3.215 1.74 ;
        RECT 2.03 1.74 2.215 4.4 ;
        RECT 2.125 0.22 2.385 1.395 ;
        RECT 2.125 5.23 2.385 6.825 ;
        RECT 2.93 3.51 3.22 4.4 ;
        RECT 2.93 4.785 3.22 5.72 ;
        RECT 2.955 1.15 3.215 1.575 ;
  END
END sg13g2_hv_buf_2

MACRO sg13g2_hv_buf_4
  CLASS CORE ;
  ORIGIN 0 0 ;
  FOREIGN sg13g2_hv_buf_4 0 0 ;
  SIZE 5.76 BY 7.14 ;
  SYMMETRY X Y ;
  SITE CoreSiteHV ;
  PIN X
    DIRECTION OUTPUT ;
    USE SIGNAL ;
    ANTENNADIFFAREA 2.6068 LAYER Metal1 ;
    PORT
      LAYER Metal1 ;
        RECT 0.32 1.955 1.325 2.715 ;
    END
  END X
  PIN A
    DIRECTION INPUT ;
    USE SIGNAL ;
    ANTENNAMODEL OXIDE1 ;
      ANTENNAGATEAREA 2.1465 LAYER Metal1 ;
    PORT
      LAYER Metal1 ;
        RECT 4.24 1.905 4.86 2.78 ;
    END
  END A
  PIN VDD
    DIRECTION INOUT ;
    USE POWER ;
    SHAPE ABUTMENT ;
    NETEXPR "VDD VDD!" ;
    PORT
      LAYER Metal1 ;
        RECT 0 6.825 5.76 7.36 ;
    END
  END VDD
  PIN VSS
    DIRECTION INOUT ;
    USE GROUND ;
    SHAPE ABUTMENT ;
    NETEXPR "VSS VSS!" ;
    PORT
      LAYER Metal1 ;
        RECT 0 -0.22 5.76 0.22 ;
    END
  END VSS
  OBS
      LAYER Metal1 ;
        RECT 0.235 0.22 0.495 1.64 ;
        RECT 0.235 3.355 0.495 6.825 ;
        RECT 1.065 1.035 1.325 1.495 ;
        RECT 1.065 1.495 2.985 1.655 ;
        RECT 1.065 1.655 1.325 1.955 ;
        RECT 1.065 2.715 1.325 3.07 ;
        RECT 1.065 3.07 2.985 3.475 ;
        RECT 1.065 3.475 1.325 5.79 ;
        RECT 1.895 0.22 2.155 1.3 ;
        RECT 1.895 4.255 2.155 6.825 ;
        RECT 2.58 1.97 3.71 2.675 ;
        RECT 2.725 1.075 2.985 1.495 ;
        RECT 2.725 3.475 2.985 5.79 ;
        RECT 3.545 1.48 5.51 1.64 ;
        RECT 3.545 1.64 3.71 1.97 ;
        RECT 3.555 3.27 3.815 6.825 ;
        RECT 3.655 1.04 4.575 1.3 ;
        RECT 3.825 0.22 4.405 1.04 ;
        RECT 4.385 3.44 5.51 4.09 ;
        RECT 4.385 4.09 4.645 4.93 ;
        RECT 5.165 1.07 5.51 1.48 ;
        RECT 5.215 4.615 5.475 6.825 ;
        RECT 5.32 1.64 5.51 3.44 ;
  END
END sg13g2_hv_buf_4

MACRO sg13g2_hv_buf_8
  CLASS CORE ;
  ORIGIN 0 0 ;
  FOREIGN sg13g2_hv_buf_8 0 0 ;
  SIZE 10.08 BY 7.14 ;
  SYMMETRY X Y ;
  SITE CoreSiteHV ;
  PIN A
    DIRECTION INPUT ;
    USE SIGNAL ;
    ANTENNAMODEL OXIDE1 ;
      ANTENNAGATEAREA 4.6305 LAYER Metal1 ;
    PORT
      LAYER Metal1 ;
        RECT 0.79 1.93 2.175 2.74 ;
    END
  END A
  PIN X
    DIRECTION OUTPUT ;
    USE SIGNAL ;
    ANTENNADIFFAREA 5.2136 LAYER Metal1 ;
    PORT
      LAYER Metal1 ;
        RECT 8.72 2.025 9.47 2.69 ;
    END
  END X
  PIN VDD
    DIRECTION INOUT ;
    USE POWER ;
    SHAPE ABUTMENT ;
    NETEXPR "VDD VDD!" ;
    PORT
      LAYER Metal1 ;
        RECT 0 6.825 10.08 7.36 ;
    END
  END VDD
  PIN VSS
    DIRECTION INOUT ;
    USE GROUND ;
    SHAPE ABUTMENT ;
    NETEXPR "VSS VSS!" ;
    PORT
      LAYER Metal1 ;
        RECT 0 -0.22 10.08 0.22 ;
    END
  END VSS
  OBS
      LAYER Metal1 ;
        RECT 0.16 1.04 0.42 1.48 ;
        RECT 0.16 1.48 2.9 1.64 ;
        RECT 0.16 3.61 2.9 3.99 ;
        RECT 0.16 3.99 0.42 5.865 ;
        RECT 0.99 0.22 1.25 1.3 ;
        RECT 0.99 4.425 1.25 6.825 ;
        RECT 1.82 1.04 2.08 1.48 ;
        RECT 1.82 3.99 2.08 5.865 ;
        RECT 2.65 0.22 2.91 1.3 ;
        RECT 2.65 4.425 2.91 6.825 ;
        RECT 2.73 1.64 2.9 2.075 ;
        RECT 2.73 2.075 7.855 2.69 ;
        RECT 2.73 2.69 2.9 3.61 ;
        RECT 3.48 1.04 3.74 1.48 ;
        RECT 3.48 1.48 8.72 1.64 ;
        RECT 3.48 3.61 8.72 3.99 ;
        RECT 3.48 3.99 3.74 5.865 ;
        RECT 4.31 0.22 4.57 1.3 ;
        RECT 4.31 4.425 4.57 6.825 ;
        RECT 5.14 1.04 5.4 1.48 ;
        RECT 5.14 3.99 5.4 5.865 ;
        RECT 5.97 0.22 6.23 1.3 ;
        RECT 5.97 4.425 6.23 6.825 ;
        RECT 6.8 1.04 7.06 1.48 ;
        RECT 6.8 3.99 7.06 5.865 ;
        RECT 7.63 0.22 7.89 1.3 ;
        RECT 7.63 4.425 7.89 6.825 ;
        RECT 8.46 1.04 8.72 1.48 ;
        RECT 8.46 1.64 8.72 3.61 ;
        RECT 8.46 3.99 8.72 5.865 ;
        RECT 9.29 0.22 9.55 1.64 ;
        RECT 9.29 3.61 9.55 6.825 ;
  END
END sg13g2_hv_buf_8

MACRO sg13g2_hv_decap_4
  CLASS CORE SPACER ;
  ORIGIN 0 0 ;
  FOREIGN sg13g2_hv_decap_4 0 0 ;
  SIZE 1.92 BY 7.14 ;
  SYMMETRY X Y ;
  SITE CoreSiteHV ;
  PIN VDD
    DIRECTION INOUT ;
    USE POWER ;
    SHAPE ABUTMENT ;
    NETEXPR "VDD VDD!" ;
    PORT
      LAYER Metal1 ;
        RECT 0 6.825 1.92 7.36 ;
    END
  END VDD
  PIN VSS
    DIRECTION INOUT ;
    USE GROUND ;
    SHAPE ABUTMENT ;
    NETEXPR "VSS VSS!" ;
    PORT
      LAYER Metal1 ;
        RECT 0 -0.22 1.92 0.22 ;
    END
  END VSS
  OBS
      LAYER Metal1 ;
        RECT 0.13 0.22 0.855 1.365 ;
        RECT 0.13 3.61 0.4 6.825 ;
        RECT 0.53 1.365 0.855 2.68 ;
        RECT 1.065 1.9 1.405 3.61 ;
        RECT 1.065 3.61 1.79 6.825 ;
        RECT 1.51 0.22 1.79 1.365 ;
  END
END sg13g2_hv_decap_4

MACRO sg13g2_hv_decap_8
  CLASS CORE SPACER ;
  ORIGIN 0 0 ;
  FOREIGN sg13g2_hv_decap_8 0 0 ;
  SIZE 3.36 BY 7.14 ;
  SYMMETRY X Y ;
  SITE CoreSiteHV ;
  PIN VDD
    DIRECTION INOUT ;
    USE POWER ;
    SHAPE ABUTMENT ;
    NETEXPR "VDD VDD!" ;
    PORT
      LAYER Metal1 ;
        RECT 0 6.825 3.36 7.36 ;
    END
  END VDD
  PIN VSS
    DIRECTION INOUT ;
    USE GROUND ;
    SHAPE ABUTMENT ;
    NETEXPR "VSS VSS!" ;
    PORT
      LAYER Metal1 ;
        RECT 0 -0.22 3.36 0.22 ;
    END
  END VSS
  OBS
      LAYER Metal1 ;
        RECT 0.175 0.22 0.81 1.42 ;
        RECT 0.185 3.57 0.445 6.825 ;
        RECT 0.52 1.42 0.81 2.685 ;
        RECT 1.22 1.905 2.155 6.825 ;
        RECT 1.53 0.22 1.835 1.46 ;
        RECT 2.585 0.22 3.195 1.42 ;
        RECT 2.585 1.42 2.835 2.685 ;
        RECT 2.945 3.585 3.205 6.825 ;
  END
END sg13g2_hv_decap_8

MACRO sg13g2_hv_dfrbp_1
  CLASS CORE ;
  ORIGIN 0 0 ;
  FOREIGN sg13g2_hv_dfrbp_1 0 0 ;
  SIZE 22.08 BY 7.14 ;
  SYMMETRY X Y ;
  SITE CoreSiteHV ;
  PIN RESET_B
    DIRECTION INPUT ;
    USE SIGNAL ;
    ANTENNAMODEL OXIDE1 ;
      ANTENNAGATEAREA 1.9305 LAYER Metal1 ;
    PORT
      LAYER Metal1 ;
        RECT 3.425 1.7 4.545 2.995 ;
    END
  END RESET_B
  PIN VSS
    DIRECTION INOUT ;
    USE GROUND ;
    SHAPE ABUTMENT ;
    NETEXPR "VSS VSS!" ;
    PORT
      LAYER Metal1 ;
        RECT 0 -0.22 22.08 0.22 ;
    END
  END VSS
  PIN VDD
    DIRECTION INOUT ;
    USE POWER ;
    SHAPE ABUTMENT ;
    NETEXPR "VDD VDD!" ;
    PORT
      LAYER Metal1 ;
        RECT 0 6.825 22.08 7.36 ;
    END
  END VDD
  PIN D
    DIRECTION INPUT ;
    USE SIGNAL ;
    ANTENNAMODEL OXIDE1 ;
      ANTENNAGATEAREA 0.6435 LAYER Metal1 ;
    PORT
      LAYER Metal1 ;
        RECT 0.255 1.24 0.77 2.795 ;
    END
  END D
  PIN Q
    DIRECTION OUTPUT ;
    USE SIGNAL ;
    ANTENNADIFFAREA 1.1662 LAYER Metal1 ;
    PORT
      LAYER Metal1 ;
        RECT 20.96 3.31 21.375 5.85 ;
    END
  END Q
  PIN Q_N
    DIRECTION OUTPUT ;
    USE SIGNAL ;
    ANTENNADIFFAREA 1.1662 LAYER Metal1 ;
    PORT
      LAYER Metal1 ;
        RECT 18.44 1.16 18.9 1.69 ;
    END
  END Q_N
  PIN CLK
    DIRECTION INPUT ;
    USE SIGNAL ;
    ANTENNAMODEL OXIDE1 ;
      ANTENNAGATEAREA 1.5435 LAYER Metal1 ;
    PORT
      LAYER Metal1 ;
        RECT 9.95 1.69 10.81 2.715 ;
    END
  END CLK
  OBS
      LAYER Metal1 ;
        RECT 0.21 0.76 1.27 1.02 ;
        RECT 0.215 3.655 0.475 6.825 ;
        RECT 1.04 3.655 1.375 4.28 ;
        RECT 1.105 1.02 1.27 3.655 ;
        RECT 1.105 4.28 1.27 5.67 ;
        RECT 1.105 5.67 4.57 6.055 ;
        RECT 1.93 0.22 2.27 1.02 ;
        RECT 2.06 1.32 5.305 1.48 ;
        RECT 2.06 1.48 2.22 4.28 ;
        RECT 2.06 4.28 3.22 4.905 ;
        RECT 2.68 1.875 3.125 3.43 ;
        RECT 2.68 3.43 6.975 3.81 ;
        RECT 3 0.985 3.26 1.32 ;
        RECT 3.515 0.22 3.775 1.085 ;
        RECT 3.525 3.81 6.975 3.835 ;
        RECT 3.525 3.835 3.705 5.24 ;
        RECT 4.045 4.33 6.075 4.71 ;
        RECT 4.045 4.71 4.57 5.67 ;
        RECT 4.39 0.61 13.82 0.775 ;
        RECT 4.39 0.775 4.72 1.32 ;
        RECT 4.85 5.145 5.31 6.825 ;
        RECT 4.865 1.48 5.305 1.875 ;
        RECT 4.865 1.875 5.42 2.995 ;
        RECT 5.315 0.955 8.085 1.13 ;
        RECT 5.81 4.71 6.075 5.67 ;
        RECT 5.81 5.67 7.685 6.055 ;
        RECT 5.88 1.33 7.66 1.49 ;
        RECT 5.88 1.49 6.185 1.81 ;
        RECT 6.755 1.67 6.975 3.43 ;
        RECT 6.755 3.835 6.975 5.01 ;
        RECT 7.44 1.49 7.66 4.65 ;
        RECT 7.44 4.65 7.845 5.275 ;
        RECT 7.44 5.275 7.685 5.67 ;
        RECT 7.84 1.61 8.085 1.87 ;
        RECT 7.905 1.13 8.085 1.61 ;
        RECT 8.035 3.465 8.99 4.09 ;
        RECT 8.035 5.54 8.295 5.66 ;
        RECT 8.035 5.66 16.185 6.045 ;
        RECT 8.035 6.045 8.295 6.165 ;
        RECT 8.325 1.09 8.995 1.35 ;
        RECT 8.325 1.35 8.6 3.25 ;
        RECT 8.325 3.25 8.99 3.465 ;
        RECT 8.73 4.09 8.99 4.59 ;
        RECT 8.73 4.59 12.935 5 ;
        RECT 8.905 1.745 9.68 2.64 ;
        RECT 9.52 1.15 10.81 1.31 ;
        RECT 9.52 1.31 9.68 1.745 ;
        RECT 9.52 2.64 9.68 3.25 ;
        RECT 9.52 3.25 11.345 3.87 ;
        RECT 10.575 1.09 10.81 1.15 ;
        RECT 10.575 1.31 10.81 1.35 ;
        RECT 10.99 0.775 11.15 1.725 ;
        RECT 10.99 1.725 12.1 1.895 ;
        RECT 11.33 0.975 14.635 1.135 ;
        RECT 11.33 1.135 11.545 1.48 ;
        RECT 11.565 1.895 12.1 4.1 ;
        RECT 12.15 1.315 14.295 1.485 ;
        RECT 12.585 1.695 13.605 1.955 ;
        RECT 12.585 1.955 12.935 4.59 ;
        RECT 13.48 3.62 14.275 4.245 ;
        RECT 13.545 0.775 13.82 0.795 ;
        RECT 13.795 1.485 14.295 1.52 ;
        RECT 13.795 1.52 17.205 1.68 ;
        RECT 13.795 1.68 14.275 3.62 ;
        RECT 14.375 0.76 14.635 0.975 ;
        RECT 14.545 1.86 15.08 3.165 ;
        RECT 14.545 3.165 17.855 3.55 ;
        RECT 15.205 0.22 15.465 1.02 ;
        RECT 15.63 5.54 16.185 5.66 ;
        RECT 15.63 6.045 16.185 6.165 ;
        RECT 16.06 3.55 16.715 4.27 ;
        RECT 16.19 1.68 17.205 1.795 ;
        RECT 16.89 0.795 17.585 1.055 ;
        RECT 17.425 1.055 17.585 1.2 ;
        RECT 17.425 1.2 17.855 1.36 ;
        RECT 17.695 1.36 17.855 3.165 ;
        RECT 17.745 4.185 18.005 6.825 ;
        RECT 17.765 0.22 18.005 1.02 ;
        RECT 18.575 0.76 18.835 1.16 ;
        RECT 18.575 1.69 18.835 5.85 ;
        RECT 19.3 0.76 19.56 1.655 ;
        RECT 19.3 1.655 20.985 1.88 ;
        RECT 19.3 1.88 19.56 5.85 ;
        RECT 20.125 3.32 20.395 6.825 ;
        RECT 20.13 0.22 20.39 1.36 ;
        RECT 20.365 1.615 20.985 1.655 ;
        RECT 20.365 1.88 20.985 1.915 ;
        RECT 20.94 0.76 21.375 1.36 ;
        RECT 21.165 1.36 21.375 3.31 ;
  END
END sg13g2_hv_dfrbp_1

MACRO sg13g2_hv_dfrbp_2
  CLASS CORE ;
  ORIGIN 0 0 ;
  FOREIGN sg13g2_hv_dfrbp_2 0 0 ;
  SIZE 25.92 BY 7.14 ;
  SYMMETRY X Y ;
  SITE CoreSiteHV ;
  PIN RESET_B
    DIRECTION INPUT ;
    USE SIGNAL ;
    ANTENNAMODEL OXIDE1 ;
      ANTENNAGATEAREA 1.9305 LAYER Metal1 ;
    PORT
      LAYER Metal1 ;
        RECT 3.48 1.71 4.545 2.995 ;
    END
  END RESET_B
  PIN VSS
    DIRECTION INOUT ;
    USE GROUND ;
    SHAPE ABUTMENT ;
    NETEXPR "VSS VSS!" ;
    PORT
      LAYER Metal1 ;
        RECT 0 -0.22 25.92 0.22 ;
    END
  END VSS
  PIN VDD
    DIRECTION INOUT ;
    USE POWER ;
    SHAPE ABUTMENT ;
    NETEXPR "VDD VDD!" ;
    PORT
      LAYER Metal1 ;
        RECT 0 6.825 25.92 7.36 ;
    END
  END VDD
  PIN D
    DIRECTION INPUT ;
    USE SIGNAL ;
    ANTENNAMODEL OXIDE1 ;
      ANTENNAGATEAREA 0.6435 LAYER Metal1 ;
    PORT
      LAYER Metal1 ;
        RECT 0.255 1.535 0.805 2.73 ;
    END
  END D
  PIN Q
    DIRECTION OUTPUT ;
    USE SIGNAL ;
    ANTENNADIFFAREA 1.3034 LAYER Metal1 ;
    PORT
      LAYER Metal1 ;
        RECT 24.115 1.205 25.415 1.65 ;
    END
  END Q
  PIN Q_N
    DIRECTION OUTPUT ;
    USE SIGNAL ;
    ANTENNADIFFAREA 1.3034 LAYER Metal1 ;
    PORT
      LAYER Metal1 ;
        RECT 20.025 1.15 20.575 1.9 ;
    END
  END Q_N
  PIN CLK
    DIRECTION INPUT ;
    USE SIGNAL ;
    ANTENNAMODEL OXIDE1 ;
      ANTENNAGATEAREA 1.5435 LAYER Metal1 ;
    PORT
      LAYER Metal1 ;
        RECT 10.385 1.495 11.39 2.925 ;
    END
  END CLK
  OBS
      LAYER Metal1 ;
        RECT 0.21 0.805 1.27 1 ;
        RECT 0.215 3.595 0.47 6.825 ;
        RECT 1.04 3.655 1.375 4.33 ;
        RECT 1.11 1 1.27 3.655 ;
        RECT 1.11 4.33 1.375 5.67 ;
        RECT 1.11 5.67 4.565 6.055 ;
        RECT 1.93 0.22 2.26 1.045 ;
        RECT 2.06 1.33 5.285 1.49 ;
        RECT 2.06 1.49 2.22 4.615 ;
        RECT 2.06 4.615 3.22 5.24 ;
        RECT 2.68 1.865 3.125 3.43 ;
        RECT 2.68 3.43 7.035 3.81 ;
        RECT 3 0.975 3.26 1.33 ;
        RECT 3.515 0.22 3.775 1.075 ;
        RECT 3.525 3.81 7.035 3.835 ;
        RECT 3.525 3.835 3.705 5.24 ;
        RECT 4.045 4.33 6.155 4.71 ;
        RECT 4.045 4.71 4.565 5.67 ;
        RECT 4.39 0.6 14.56 0.765 ;
        RECT 4.39 0.765 4.715 1.33 ;
        RECT 4.795 1.49 5.285 1.915 ;
        RECT 4.795 1.915 5.425 2.995 ;
        RECT 4.83 5.145 5.305 6.825 ;
        RECT 5.365 0.945 8.245 1.12 ;
        RECT 5.88 1.385 7.83 1.49 ;
        RECT 5.88 1.49 6.185 1.8 ;
        RECT 5.995 4.71 6.155 5.445 ;
        RECT 5.995 5.445 8.005 5.83 ;
        RECT 6.005 1.33 7.83 1.385 ;
        RECT 6.85 1.67 7.07 2.255 ;
        RECT 6.85 2.255 7.035 3.43 ;
        RECT 6.85 3.835 7.035 5.01 ;
        RECT 7.535 1.49 7.83 4.725 ;
        RECT 7.535 4.725 8.005 5.445 ;
        RECT 8.01 1.6 8.275 1.86 ;
        RECT 8.065 1.12 8.245 1.46 ;
        RECT 8.065 1.46 8.275 1.6 ;
        RECT 8.235 5.54 8.495 5.66 ;
        RECT 8.235 5.66 17.8 6.045 ;
        RECT 8.235 6.045 8.495 6.165 ;
        RECT 8.4 3.44 9.485 4.065 ;
        RECT 8.535 1.295 8.795 3.225 ;
        RECT 8.535 3.225 9.485 3.44 ;
        RECT 8.805 4.065 9.485 4.59 ;
        RECT 8.805 4.59 13.515 4.975 ;
        RECT 9.35 1.7 10.145 2.745 ;
        RECT 9.885 1.015 11.39 1.185 ;
        RECT 9.885 1.185 10.145 1.7 ;
        RECT 9.885 2.745 10.145 3.43 ;
        RECT 9.885 3.43 11.925 3.97 ;
        RECT 11.155 0.97 11.39 1.015 ;
        RECT 11.155 1.185 11.39 1.23 ;
        RECT 11.57 0.765 11.73 1.715 ;
        RECT 11.57 1.715 12.675 1.885 ;
        RECT 11.665 3.26 11.925 3.43 ;
        RECT 11.91 0.965 15.6 1.125 ;
        RECT 11.91 1.125 12.08 1.47 ;
        RECT 12.145 1.885 12.675 4.16 ;
        RECT 12.73 1.305 14.875 1.435 ;
        RECT 12.73 1.435 18.435 1.475 ;
        RECT 13.16 1.67 14.185 1.93 ;
        RECT 13.16 1.93 13.515 4.59 ;
        RECT 14.04 3.38 14.855 3.79 ;
        RECT 14.04 3.79 14.245 4.28 ;
        RECT 14.125 0.765 14.56 0.785 ;
        RECT 14.525 1.475 18.435 1.625 ;
        RECT 14.525 1.625 14.855 3.38 ;
        RECT 14.955 0.785 15.6 0.965 ;
        RECT 15.085 1.815 15.765 3.32 ;
        RECT 15.085 3.32 18.775 3.705 ;
        RECT 16.235 0.22 16.76 1.045 ;
        RECT 17.22 3.705 17.79 4.27 ;
        RECT 17.22 5.54 17.8 5.66 ;
        RECT 17.22 6.045 17.8 6.165 ;
        RECT 17.78 1.625 18.435 1.825 ;
        RECT 18.425 0.785 18.775 1.045 ;
        RECT 18.495 4.185 18.755 6.825 ;
        RECT 18.615 1.045 18.775 3.32 ;
        RECT 19.275 0.22 19.515 1.01 ;
        RECT 19.325 1.68 20.025 1.9 ;
        RECT 19.325 1.9 19.61 5.625 ;
        RECT 20.215 0.75 20.515 1.15 ;
        RECT 20.325 3.03 20.61 6.825 ;
        RECT 21.235 0.22 21.52 1.01 ;
        RECT 21.33 3.03 22.03 3.18 ;
        RECT 21.33 3.18 22.005 5.29 ;
        RECT 21.54 1.695 22.925 2.025 ;
        RECT 21.54 2.025 22.03 3.03 ;
        RECT 22.07 0.75 22.355 1.695 ;
        RECT 22.225 3.285 22.485 6.825 ;
        RECT 22.735 0.22 23.18 1.37 ;
        RECT 23.055 3.285 23.625 5.9 ;
        RECT 23.18 1.675 24.58 1.935 ;
        RECT 23.18 1.935 23.625 3.285 ;
        RECT 24.115 0.755 24.58 1.205 ;
        RECT 24.115 1.65 24.58 1.675 ;
        RECT 24.455 3.285 24.92 6.825 ;
        RECT 25.14 0.22 25.415 1 ;
  END
END sg13g2_hv_dfrbp_2

MACRO sg13g2_hv_dfrbpq_1
  CLASS CORE ;
  ORIGIN 0 0 ;
  FOREIGN sg13g2_hv_dfrbpq_1 0 0 ;
  SIZE 20.64 BY 7.14 ;
  SYMMETRY X Y ;
  SITE CoreSiteHV ;
  PIN RESET_B
    DIRECTION INPUT ;
    USE SIGNAL ;
    ANTENNAMODEL OXIDE1 ;
      ANTENNAGATEAREA 1.9305 LAYER Metal1 ;
    PORT
      LAYER Metal1 ;
        RECT 3.425 1.7 4.545 2.995 ;
    END
  END RESET_B
  PIN VSS
    DIRECTION INOUT ;
    USE GROUND ;
    SHAPE ABUTMENT ;
    NETEXPR "VSS VSS!" ;
    PORT
      LAYER Metal1 ;
        RECT 0 -0.22 20.64 0.22 ;
    END
  END VSS
  PIN VDD
    DIRECTION INOUT ;
    USE POWER ;
    SHAPE ABUTMENT ;
    NETEXPR "VDD VDD!" ;
    PORT
      LAYER Metal1 ;
        RECT 0 6.825 20.64 7.36 ;
    END
  END VDD
  PIN D
    DIRECTION INPUT ;
    USE SIGNAL ;
    ANTENNAMODEL OXIDE1 ;
      ANTENNAGATEAREA 0.6435 LAYER Metal1 ;
    PORT
      LAYER Metal1 ;
        RECT 0.255 1.24 0.77 2.795 ;
    END
  END D
  PIN Q
    DIRECTION OUTPUT ;
    USE SIGNAL ;
    ANTENNADIFFAREA 1.1662 LAYER Metal1 ;
    PORT
      LAYER Metal1 ;
        RECT 19.79 3.31 20.205 5.85 ;
    END
  END Q
  PIN CLK
    DIRECTION INPUT ;
    USE SIGNAL ;
    ANTENNAMODEL OXIDE1 ;
      ANTENNAGATEAREA 1.5435 LAYER Metal1 ;
    PORT
      LAYER Metal1 ;
        RECT 9.95 1.69 10.81 2.715 ;
    END
  END CLK
  OBS
      LAYER Metal1 ;
        RECT 0.21 0.76 1.27 1.02 ;
        RECT 0.215 3.655 0.475 6.825 ;
        RECT 1.04 3.655 1.375 4.28 ;
        RECT 1.105 1.02 1.27 3.655 ;
        RECT 1.105 4.28 1.27 5.67 ;
        RECT 1.105 5.67 4.57 6.055 ;
        RECT 1.93 0.22 2.27 1.02 ;
        RECT 2.06 1.32 5.305 1.48 ;
        RECT 2.06 1.48 2.22 4.28 ;
        RECT 2.06 4.28 3.22 4.905 ;
        RECT 2.68 1.875 3.125 3.43 ;
        RECT 2.68 3.43 6.975 3.81 ;
        RECT 3 0.985 3.26 1.32 ;
        RECT 3.515 0.22 3.775 1.085 ;
        RECT 3.525 3.81 6.975 3.835 ;
        RECT 3.525 3.835 3.705 5.24 ;
        RECT 4.045 4.33 6.075 4.71 ;
        RECT 4.045 4.71 4.57 5.67 ;
        RECT 4.39 0.61 13.82 0.775 ;
        RECT 4.39 0.775 4.72 1.32 ;
        RECT 4.85 5.145 5.31 6.825 ;
        RECT 4.865 1.48 5.305 1.875 ;
        RECT 4.865 1.875 5.42 2.995 ;
        RECT 5.315 0.955 8.085 1.13 ;
        RECT 5.81 4.71 6.075 5.67 ;
        RECT 5.81 5.67 7.685 6.055 ;
        RECT 5.88 1.33 7.66 1.49 ;
        RECT 5.88 1.49 6.185 1.81 ;
        RECT 6.755 1.67 6.975 3.43 ;
        RECT 6.755 3.835 6.975 5.01 ;
        RECT 7.44 1.49 7.66 4.65 ;
        RECT 7.44 4.65 7.845 5.275 ;
        RECT 7.44 5.275 7.685 5.67 ;
        RECT 7.84 1.61 8.085 1.87 ;
        RECT 7.905 1.13 8.085 1.61 ;
        RECT 8.035 3.465 8.99 4.09 ;
        RECT 8.035 5.54 8.295 5.66 ;
        RECT 8.035 5.66 16.185 6.045 ;
        RECT 8.035 6.045 8.295 6.165 ;
        RECT 8.325 1.09 8.995 1.35 ;
        RECT 8.325 1.35 8.6 3.25 ;
        RECT 8.325 3.25 8.99 3.465 ;
        RECT 8.73 4.09 8.99 4.59 ;
        RECT 8.73 4.59 12.935 5 ;
        RECT 8.905 1.745 9.68 2.64 ;
        RECT 9.52 1.15 10.81 1.31 ;
        RECT 9.52 1.31 9.68 1.745 ;
        RECT 9.52 2.64 9.68 3.25 ;
        RECT 9.52 3.25 11.345 3.87 ;
        RECT 10.575 1.09 10.81 1.15 ;
        RECT 10.575 1.31 10.81 1.35 ;
        RECT 10.99 0.775 11.15 1.725 ;
        RECT 10.99 1.725 12.1 1.895 ;
        RECT 11.33 0.975 14.635 1.135 ;
        RECT 11.33 1.135 11.545 1.48 ;
        RECT 11.565 1.895 12.1 4.1 ;
        RECT 12.15 1.315 14.295 1.485 ;
        RECT 12.585 1.695 13.605 1.955 ;
        RECT 12.585 1.955 12.935 4.59 ;
        RECT 13.48 3.62 14.275 4.245 ;
        RECT 13.545 0.775 13.82 0.795 ;
        RECT 13.795 1.485 14.295 1.52 ;
        RECT 13.795 1.52 17.205 1.68 ;
        RECT 13.795 1.68 14.275 3.62 ;
        RECT 14.375 0.76 14.635 0.975 ;
        RECT 14.545 1.86 15.08 2.735 ;
        RECT 14.545 2.735 17.69 3.13 ;
        RECT 15.205 0.22 15.465 1.02 ;
        RECT 15.63 5.54 16.185 5.66 ;
        RECT 15.63 6.045 16.185 6.165 ;
        RECT 16.06 3.13 16.715 4.27 ;
        RECT 16.19 1.68 17.205 1.795 ;
        RECT 16.89 0.795 17.585 1.055 ;
        RECT 17.425 1.055 17.585 1.2 ;
        RECT 17.425 1.2 17.69 1.36 ;
        RECT 17.465 3.62 17.73 6.825 ;
        RECT 17.53 1.36 17.69 2.735 ;
        RECT 18.13 0.76 18.39 1.655 ;
        RECT 18.13 1.655 19.815 1.88 ;
        RECT 18.13 1.88 18.39 5.85 ;
        RECT 18.96 0.22 19.22 1.36 ;
        RECT 18.96 3.32 19.22 6.825 ;
        RECT 19.195 1.615 19.815 1.655 ;
        RECT 19.195 1.88 19.815 1.915 ;
        RECT 19.77 0.76 20.205 1.36 ;
        RECT 19.995 1.36 20.205 3.31 ;
  END
END sg13g2_hv_dfrbpq_1

MACRO sg13g2_hv_dfrbpq_2
  CLASS CORE ;
  ORIGIN 0 0 ;
  FOREIGN sg13g2_hv_dfrbpq_2 0 0 ;
  SIZE 23.04 BY 7.14 ;
  SYMMETRY X Y ;
  SITE CoreSiteHV ;
  PIN RESET_B
    DIRECTION INPUT ;
    USE SIGNAL ;
    ANTENNAMODEL OXIDE1 ;
      ANTENNAGATEAREA 1.9305 LAYER Metal1 ;
    PORT
      LAYER Metal1 ;
        RECT 3.48 1.71 4.545 2.995 ;
    END
  END RESET_B
  PIN VSS
    DIRECTION INOUT ;
    USE GROUND ;
    SHAPE ABUTMENT ;
    NETEXPR "VSS VSS!" ;
    PORT
      LAYER Metal1 ;
        RECT 0 -0.22 23.04 0.22 ;
    END
  END VSS
  PIN VDD
    DIRECTION INOUT ;
    USE POWER ;
    SHAPE ABUTMENT ;
    NETEXPR "VDD VDD!" ;
    PORT
      LAYER Metal1 ;
        RECT 0 6.825 23.04 7.36 ;
    END
  END VDD
  PIN D
    DIRECTION INPUT ;
    USE SIGNAL ;
    ANTENNAMODEL OXIDE1 ;
      ANTENNAGATEAREA 0.6435 LAYER Metal1 ;
    PORT
      LAYER Metal1 ;
        RECT 0.255 1.535 0.805 2.73 ;
    END
  END D
  PIN Q
    DIRECTION OUTPUT ;
    USE SIGNAL ;
    ANTENNADIFFAREA 1.3034 LAYER Metal1 ;
    PORT
      LAYER Metal1 ;
        RECT 21.445 1.665 22.475 2.72 ;
    END
  END Q
  PIN CLK
    DIRECTION INPUT ;
    USE SIGNAL ;
    ANTENNAMODEL OXIDE1 ;
      ANTENNAGATEAREA 1.5435 LAYER Metal1 ;
    PORT
      LAYER Metal1 ;
        RECT 10.385 1.495 11.39 2.925 ;
    END
  END CLK
  OBS
      LAYER Metal1 ;
        RECT 0.21 0.805 1.27 1 ;
        RECT 0.215 3.595 0.47 6.825 ;
        RECT 1.04 3.655 1.375 4.33 ;
        RECT 1.11 1 1.27 3.655 ;
        RECT 1.11 4.33 1.375 5.67 ;
        RECT 1.11 5.67 4.565 6.055 ;
        RECT 1.93 0.22 2.26 1.045 ;
        RECT 2.06 1.33 5.285 1.49 ;
        RECT 2.06 1.49 2.22 4.615 ;
        RECT 2.06 4.615 3.22 5.24 ;
        RECT 2.68 1.865 3.125 3.43 ;
        RECT 2.68 3.43 7.035 3.81 ;
        RECT 3 0.975 3.26 1.33 ;
        RECT 3.515 0.22 3.775 1.075 ;
        RECT 3.525 3.81 7.035 3.835 ;
        RECT 3.525 3.835 3.705 5.24 ;
        RECT 4.045 4.33 6.155 4.71 ;
        RECT 4.045 4.71 4.565 5.67 ;
        RECT 4.39 0.6 14.56 0.765 ;
        RECT 4.39 0.765 4.715 1.33 ;
        RECT 4.795 1.49 5.285 1.915 ;
        RECT 4.795 1.915 5.425 2.995 ;
        RECT 4.83 5.145 5.305 6.825 ;
        RECT 5.365 0.945 8.245 1.12 ;
        RECT 5.88 1.385 7.83 1.49 ;
        RECT 5.88 1.49 6.185 1.8 ;
        RECT 5.995 4.71 6.155 5.445 ;
        RECT 5.995 5.445 8.005 5.83 ;
        RECT 6.005 1.33 7.83 1.385 ;
        RECT 6.85 1.67 7.07 2.255 ;
        RECT 6.85 2.255 7.035 3.43 ;
        RECT 6.85 3.835 7.035 5.01 ;
        RECT 7.535 1.49 7.83 4.725 ;
        RECT 7.535 4.725 8.005 5.445 ;
        RECT 8.01 1.6 8.275 1.86 ;
        RECT 8.065 1.12 8.245 1.46 ;
        RECT 8.065 1.46 8.275 1.6 ;
        RECT 8.235 5.54 8.495 5.66 ;
        RECT 8.235 5.66 17.8 6.045 ;
        RECT 8.235 6.045 8.495 6.165 ;
        RECT 8.4 3.44 9.485 4.065 ;
        RECT 8.535 1.295 8.795 3.225 ;
        RECT 8.535 3.225 9.485 3.44 ;
        RECT 8.805 4.065 9.485 4.59 ;
        RECT 8.805 4.59 13.515 4.975 ;
        RECT 9.35 1.7 10.145 2.745 ;
        RECT 9.885 1.015 11.39 1.185 ;
        RECT 9.885 1.185 10.145 1.7 ;
        RECT 9.885 2.745 10.145 3.43 ;
        RECT 9.885 3.43 11.925 3.97 ;
        RECT 11.155 0.97 11.39 1.015 ;
        RECT 11.155 1.185 11.39 1.23 ;
        RECT 11.57 0.765 11.73 1.715 ;
        RECT 11.57 1.715 12.675 1.885 ;
        RECT 11.665 3.26 11.925 3.43 ;
        RECT 11.91 0.965 15.6 1.125 ;
        RECT 11.91 1.125 12.08 1.47 ;
        RECT 12.145 1.885 12.675 4.16 ;
        RECT 12.73 1.305 14.875 1.435 ;
        RECT 12.73 1.435 18.435 1.475 ;
        RECT 13.16 1.67 14.185 1.93 ;
        RECT 13.16 1.93 13.515 4.59 ;
        RECT 14.04 3.38 14.855 3.79 ;
        RECT 14.04 3.79 14.245 4.28 ;
        RECT 14.125 0.765 14.56 0.785 ;
        RECT 14.525 1.475 18.435 1.625 ;
        RECT 14.525 1.625 14.855 3.38 ;
        RECT 14.955 0.785 15.6 0.965 ;
        RECT 15.085 1.815 15.765 3.32 ;
        RECT 15.085 3.32 18.775 3.705 ;
        RECT 16.235 0.22 16.76 1.045 ;
        RECT 17.22 3.705 17.79 4.27 ;
        RECT 17.22 5.54 17.8 5.66 ;
        RECT 17.22 6.045 17.8 6.165 ;
        RECT 17.78 1.625 18.435 1.825 ;
        RECT 18.425 0.785 18.775 1.045 ;
        RECT 18.495 4.185 18.755 6.825 ;
        RECT 18.615 1.045 18.775 3.32 ;
        RECT 19.275 0.22 19.525 1.35 ;
        RECT 19.355 1.715 20.605 2.025 ;
        RECT 19.355 2.025 19.69 5.73 ;
        RECT 20.095 0.75 20.355 1.7 ;
        RECT 20.095 1.7 20.605 1.715 ;
        RECT 20.615 3.535 20.875 6.825 ;
        RECT 20.62 0.22 20.885 1.36 ;
        RECT 21.445 0.755 21.705 1.665 ;
        RECT 21.445 2.72 21.705 5.865 ;
        RECT 22.28 3.61 22.54 6.825 ;
        RECT 22.285 0.22 22.54 1.36 ;
  END
END sg13g2_hv_dfrbpq_2

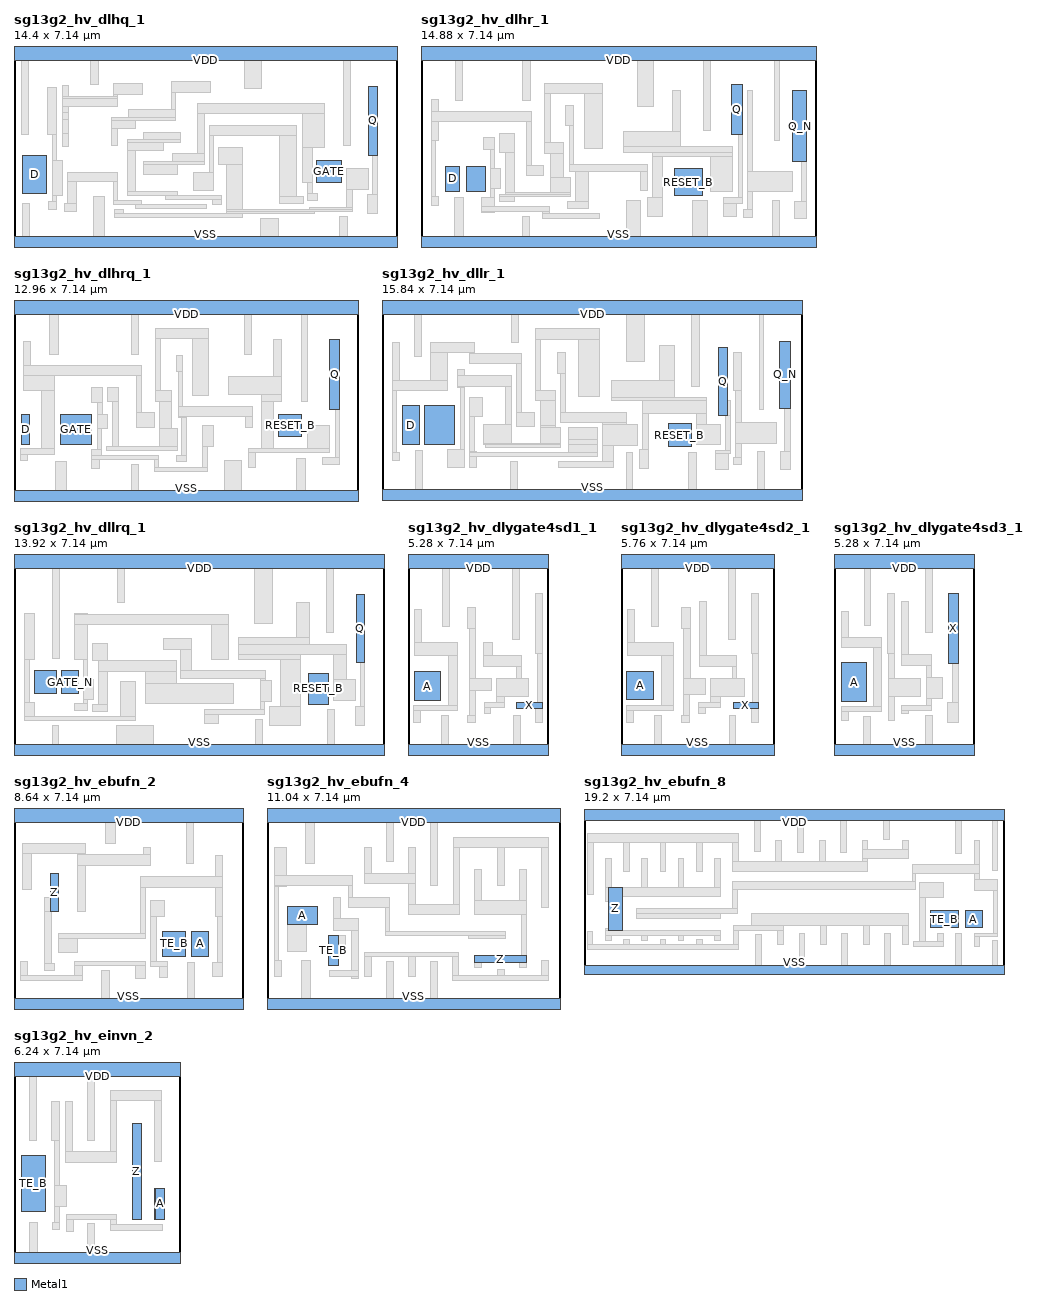
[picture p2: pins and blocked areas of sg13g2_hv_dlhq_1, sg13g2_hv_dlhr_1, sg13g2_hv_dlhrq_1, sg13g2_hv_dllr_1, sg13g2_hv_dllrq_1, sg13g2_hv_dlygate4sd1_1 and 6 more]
MACRO sg13g2_hv_dlhq_1
  CLASS CORE ;
  ORIGIN 0 0 ;
  FOREIGN sg13g2_hv_dlhq_1 0 0 ;
  SIZE 14.4 BY 7.14 ;
  SYMMETRY X Y ;
  SITE CoreSiteHV ;
  PIN D
    DIRECTION INPUT ;
    USE SIGNAL ;
    ANTENNAMODEL OXIDE1 ;
      ANTENNAGATEAREA 1.1542 LAYER Metal1 ;
    PORT
      LAYER Metal1 ;
        RECT 0.315 1.83 1.215 3.25 ;
    END
  END D
  PIN GATE
    DIRECTION INPUT ;
    USE SIGNAL ;
    ANTENNAMODEL OXIDE1 ;
      ANTENNAGATEAREA 1.2398 LAYER Metal1 ;
    PORT
      LAYER Metal1 ;
        RECT 11.385 2.225 12.315 3.08 ;
    END
  END GATE
  PIN Q
    DIRECTION OUTPUT ;
    USE SIGNAL ;
    ANTENNADIFFAREA 1.1662 LAYER Metal1 ;
    PORT
      LAYER Metal1 ;
        RECT 13.315 3.26 13.65 5.85 ;
    END
  END Q
  PIN VDD
    DIRECTION INOUT ;
    USE POWER ;
    SHAPE ABUTMENT ;
    NETEXPR "VDD VDD!" ;
    PORT
      LAYER Metal1 ;
        RECT 0 6.825 14.4 7.36 ;
    END
  END VDD
  PIN VSS
    DIRECTION INOUT ;
    USE GROUND ;
    SHAPE ABUTMENT ;
    NETEXPR "VSS VSS!" ;
    PORT
      LAYER Metal1 ;
        RECT 0 -0.22 14.4 0.22 ;
    END
  END VSS
  OBS
      LAYER Metal1 ;
        RECT 0.275 4.04 0.535 6.825 ;
        RECT 0.335 0.22 0.595 1.46 ;
        RECT 1.255 4.05 1.605 5.805 ;
        RECT 1.295 1.22 1.595 1.525 ;
        RECT 1.435 1.525 1.595 1.75 ;
        RECT 1.435 1.75 1.825 3.055 ;
        RECT 1.435 3.055 1.605 4.05 ;
        RECT 1.805 3.595 2.04 4.06 ;
        RECT 1.805 4.59 2.04 4.88 ;
        RECT 1.805 5.4 3.905 5.48 ;
        RECT 1.805 5.48 2.04 5.875 ;
        RECT 1.825 4.06 2.04 4.59 ;
        RECT 1.825 4.88 2.04 5.095 ;
        RECT 1.825 5.095 3.905 5.4 ;
        RECT 1.885 1.155 2.335 1.465 ;
        RECT 2.005 1.465 2.335 2.27 ;
        RECT 2.005 2.27 3.905 2.62 ;
        RECT 2.87 5.935 3.17 6.825 ;
        RECT 2.985 0.22 3.415 1.7 ;
        RECT 3.65 3.62 3.9 4.27 ;
        RECT 3.65 4.27 4.57 4.555 ;
        RECT 3.65 4.555 6.085 4.665 ;
        RECT 3.735 5.48 3.905 5.54 ;
        RECT 3.735 5.54 4.845 5.97 ;
        RECT 3.745 1.395 7.22 1.405 ;
        RECT 3.745 1.405 4.78 1.56 ;
        RECT 3.745 1.56 3.905 2.27 ;
        RECT 3.77 0.905 8.595 1.055 ;
        RECT 3.77 1.055 11.31 1.065 ;
        RECT 3.77 1.065 4.13 1.21 ;
        RECT 4.27 1.745 7.785 1.755 ;
        RECT 4.27 1.755 6.13 1.905 ;
        RECT 4.27 1.905 4.57 3.45 ;
        RECT 4.27 3.45 5.615 3.74 ;
        RECT 4.27 3.74 6.27 3.835 ;
        RECT 4.285 4.665 6.085 4.965 ;
        RECT 4.55 1.245 7.22 1.395 ;
        RECT 4.865 2.53 6.13 2.91 ;
        RECT 4.865 2.91 7.15 3.02 ;
        RECT 4.88 3.835 6.27 4.125 ;
        RECT 5.685 1.585 7.785 1.745 ;
        RECT 5.915 4.965 6.085 5.635 ;
        RECT 5.915 5.635 7.375 6.045 ;
        RECT 5.975 3.02 7.15 3.31 ;
        RECT 6.735 1.945 7.49 2.625 ;
        RECT 6.895 3.31 7.15 4.82 ;
        RECT 6.895 4.82 11.66 5.205 ;
        RECT 7.33 2.625 7.49 4.005 ;
        RECT 7.33 4.005 10.625 4.39 ;
        RECT 7.455 1.425 7.785 1.585 ;
        RECT 7.7 2.91 8.595 3.55 ;
        RECT 7.97 1.065 11.31 1.13 ;
        RECT 7.97 1.13 12.73 1.215 ;
        RECT 7.97 1.215 8.595 2.91 ;
        RECT 8.65 5.755 9.315 6.825 ;
        RECT 9.27 0.22 9.935 0.875 ;
        RECT 9.97 1.435 10.865 1.695 ;
        RECT 9.97 1.695 10.625 4.005 ;
        RECT 10.845 2.225 11.205 3.57 ;
        RECT 10.845 3.57 11.66 4.82 ;
        RECT 11.045 1.545 11.41 1.82 ;
        RECT 11.045 1.82 11.205 2.225 ;
        RECT 11.1 1.215 12.73 1.31 ;
        RECT 12.23 0.22 12.55 0.945 ;
        RECT 12.375 3.63 12.635 6.825 ;
        RECT 12.495 1.31 12.73 1.97 ;
        RECT 12.495 1.97 13.31 2.745 ;
        RECT 13.3 1.06 13.65 1.785 ;
        RECT 13.49 1.785 13.65 3.26 ;
  END
END sg13g2_hv_dlhq_1

MACRO sg13g2_hv_dlhr_1
  CLASS CORE ;
  ORIGIN 0 0 ;
  FOREIGN sg13g2_hv_dlhr_1 0 0 ;
  SIZE 14.88 BY 7.14 ;
  SYMMETRY X Y ;
  SITE CoreSiteHV ;
  PIN D
    DIRECTION INPUT ;
    USE SIGNAL ;
    ANTENNAMODEL OXIDE1 ;
      ANTENNAGATEAREA 1.1542 LAYER Metal1 ;
    PORT
      LAYER Metal1 ;
        RECT 0.915 1.88 1.455 2.855 ;
    END
  END D
  PIN GATE
    DIRECTION INPUT ;
    USE SIGNAL ;
    ANTENNAMODEL OXIDE1 ;
      ANTENNAGATEAREA 1.2398 LAYER Metal1 ;
    PORT
      LAYER Metal1 ;
        RECT 1.695 1.88 2.425 2.855 ;
    END
  END GATE
  PIN RESET_B
    DIRECTION INPUT ;
    USE SIGNAL ;
    ANTENNAMODEL OXIDE1 ;
      ANTENNAGATEAREA 1.5435 LAYER Metal1 ;
    PORT
      LAYER Metal1 ;
        RECT 9.51 1.755 10.565 2.75 ;
    END
  END RESET_B
  PIN Q
    DIRECTION OUTPUT ;
    USE SIGNAL ;
    ANTENNADIFFAREA 1.1662 LAYER Metal1 ;
    PORT
      LAYER Metal1 ;
        RECT 11.665 4.03 12.08 5.9 ;
    END
  END Q
  PIN VDD
    DIRECTION INOUT ;
    USE POWER ;
    SHAPE ABUTMENT ;
    NETEXPR "VDD VDD!" ;
    PORT
      LAYER Metal1 ;
        RECT 0 6.825 14.88 7.36 ;
    END
  END VDD
  PIN VSS
    DIRECTION INOUT ;
    USE GROUND ;
    SHAPE ABUTMENT ;
    NETEXPR "VSS VSS!" ;
    PORT
      LAYER Metal1 ;
        RECT 0 -0.22 14.88 0.22 ;
    END
  END VSS
  PIN Q_N
    DIRECTION OUTPUT ;
    USE SIGNAL ;
    ANTENNADIFFAREA 1.1662 LAYER Metal1 ;
    PORT
      LAYER Metal1 ;
        RECT 13.97 3.01 14.485 5.695 ;
    END
  END Q_N
  OBS
      LAYER Metal1 ;
        RECT 0.38 1.39 0.665 1.7 ;
        RECT 0.38 1.7 0.54 3.8 ;
        RECT 0.38 3.8 0.665 4.51 ;
        RECT 0.38 4.51 4.14 4.89 ;
        RECT 0.38 4.89 0.665 5.35 ;
        RECT 1.255 0.22 1.585 1.68 ;
        RECT 1.315 5.325 1.575 6.825 ;
        RECT 2.265 1.09 2.765 1.15 ;
        RECT 2.265 1.15 4.82 1.32 ;
        RECT 2.265 1.32 2.765 1.68 ;
        RECT 2.355 3.475 2.765 3.93 ;
        RECT 2.605 1.68 2.765 2.025 ;
        RECT 2.605 2.025 2.98 2.765 ;
        RECT 2.605 2.765 2.765 3.475 ;
        RECT 2.945 1.505 3.52 1.7 ;
        RECT 2.945 1.7 5.61 1.78 ;
        RECT 2.945 3.38 3.52 4.075 ;
        RECT 3.165 1.78 5.61 1.865 ;
        RECT 3.165 1.865 3.52 3.38 ;
        RECT 3.825 0.22 4.085 0.97 ;
        RECT 3.83 5.325 4.11 6.825 ;
        RECT 3.97 2.495 4.62 2.885 ;
        RECT 3.97 2.885 4.14 4.51 ;
        RECT 4.57 0.87 6.715 1.06 ;
        RECT 4.57 1.06 4.82 1.15 ;
        RECT 4.655 3.33 5.34 3.73 ;
        RECT 4.655 3.73 4.865 5.565 ;
        RECT 4.655 5.565 6.835 5.97 ;
        RECT 4.85 1.865 5.61 2.42 ;
        RECT 4.85 2.42 5.34 3.33 ;
        RECT 5.425 4.365 5.73 5.13 ;
        RECT 5.52 1.27 6.295 1.52 ;
        RECT 5.57 2.645 8.53 2.925 ;
        RECT 5.57 2.925 5.73 4.365 ;
        RECT 5.795 1.52 6.295 2.635 ;
        RECT 5.795 2.635 8.53 2.645 ;
        RECT 6.14 3.51 6.835 5.565 ;
        RECT 7.61 3.37 11.7 3.595 ;
        RECT 7.61 3.595 9.755 4.16 ;
        RECT 7.73 0.22 8.25 1.545 ;
        RECT 8.12 5.085 8.72 6.825 ;
        RECT 8.26 1.945 8.53 2.635 ;
        RECT 8.505 0.94 9.09 1.66 ;
        RECT 8.71 1.66 9.09 3.21 ;
        RECT 8.71 3.21 11.7 3.37 ;
        RECT 9.445 4.16 9.755 5.695 ;
        RECT 10.19 0.22 10.75 1.57 ;
        RECT 10.61 4.185 10.865 6.825 ;
        RECT 10.88 1.91 11.7 3.21 ;
        RECT 11.385 0.94 11.855 1.44 ;
        RECT 11.385 1.44 12.08 1.67 ;
        RECT 11.92 1.67 12.08 4.03 ;
        RECT 12.135 0.92 12.44 1.205 ;
        RECT 12.26 1.205 12.44 1.905 ;
        RECT 12.26 1.905 13.97 2.635 ;
        RECT 12.26 2.635 12.45 5.695 ;
        RECT 13.2 0.22 13.46 1.55 ;
        RECT 13.285 3.825 13.47 6.825 ;
        RECT 14.04 0.9 14.485 1.515 ;
        RECT 14.31 1.515 14.485 3.01 ;
  END
END sg13g2_hv_dlhr_1

MACRO sg13g2_hv_dlhrq_1
  CLASS CORE ;
  ORIGIN 0 0 ;
  FOREIGN sg13g2_hv_dlhrq_1 0 0 ;
  SIZE 12.96 BY 7.14 ;
  SYMMETRY X Y ;
  SITE CoreSiteHV ;
  PIN D
    DIRECTION INPUT ;
    USE SIGNAL ;
    ANTENNAMODEL OXIDE1 ;
      ANTENNAGATEAREA 1.1542 LAYER Metal1 ;
    PORT
      LAYER Metal1 ;
        RECT 0.3 1.95 0.6 3.08 ;
    END
  END D
  PIN GATE
    DIRECTION INPUT ;
    USE SIGNAL ;
    ANTENNAMODEL OXIDE1 ;
      ANTENNAGATEAREA 1.2398 LAYER Metal1 ;
    PORT
      LAYER Metal1 ;
        RECT 1.74 1.935 2.925 3.08 ;
    END
  END GATE
  PIN RESET_B
    DIRECTION INPUT ;
    USE SIGNAL ;
    ANTENNAMODEL OXIDE1 ;
      ANTENNAGATEAREA 1.4130 LAYER Metal1 ;
    PORT
      LAYER Metal1 ;
        RECT 9.95 2.225 10.81 3.08 ;
    END
  END RESET_B
  PIN Q
    DIRECTION OUTPUT ;
    USE SIGNAL ;
    ANTENNADIFFAREA 1.1662 LAYER Metal1 ;
    PORT
      LAYER Metal1 ;
        RECT 11.865 3.26 12.225 5.865 ;
    END
  END Q
  PIN VDD
    DIRECTION INOUT ;
    USE POWER ;
    SHAPE ABUTMENT ;
    NETEXPR "VDD VDD!" ;
    PORT
      LAYER Metal1 ;
        RECT 0 6.825 12.96 7.36 ;
    END
  END VDD
  PIN VSS
    DIRECTION INOUT ;
    USE GROUND ;
    SHAPE ABUTMENT ;
    NETEXPR "VSS VSS!" ;
    PORT
      LAYER Metal1 ;
        RECT 0 -0.22 12.96 0.22 ;
    END
  END VSS
  OBS
      LAYER Metal1 ;
        RECT 0.24 1.35 0.515 1.55 ;
        RECT 0.24 1.55 1.52 1.77 ;
        RECT 0.365 3.97 1.52 4.51 ;
        RECT 0.365 4.51 4.8 4.89 ;
        RECT 0.365 4.89 0.61 5.815 ;
        RECT 1.025 1.77 1.52 3.97 ;
        RECT 1.34 5.325 1.685 6.825 ;
        RECT 1.55 0.22 1.985 1.3 ;
        RECT 2.905 3.51 3.315 4.075 ;
        RECT 2.925 1.035 3.215 1.355 ;
        RECT 2.925 1.355 5.44 1.515 ;
        RECT 2.925 1.515 3.305 1.745 ;
        RECT 3.145 1.745 3.305 2.555 ;
        RECT 3.145 2.555 3.52 3.08 ;
        RECT 3.145 3.08 3.315 3.51 ;
        RECT 3.485 1.695 6.13 1.875 ;
        RECT 3.495 3.56 3.92 4.075 ;
        RECT 3.7 1.875 3.92 3.56 ;
        RECT 4.4 0.22 4.69 1.175 ;
        RECT 4.43 5.325 4.69 6.825 ;
        RECT 4.585 2.565 5.27 3.13 ;
        RECT 4.585 3.13 4.8 4.51 ;
        RECT 5.265 0.905 7.28 1.075 ;
        RECT 5.265 1.075 5.44 1.355 ;
        RECT 5.32 3.55 5.935 3.97 ;
        RECT 5.32 3.97 5.52 5.91 ;
        RECT 5.32 5.91 7.325 6.295 ;
        RECT 5.455 1.875 6.13 2.545 ;
        RECT 5.455 2.545 5.935 3.55 ;
        RECT 6.1 1.28 6.495 1.515 ;
        RECT 6.11 4.665 6.35 5.29 ;
        RECT 6.19 2.95 6.495 2.97 ;
        RECT 6.19 2.97 8.975 3.355 ;
        RECT 6.19 3.355 6.35 4.665 ;
        RECT 6.31 1.515 6.495 2.95 ;
        RECT 6.7 3.79 7.325 5.91 ;
        RECT 7.095 1.075 7.28 1.875 ;
        RECT 7.095 1.875 7.49 2.65 ;
        RECT 7.905 0.22 8.55 1.325 ;
        RECT 8.05 3.8 10.04 4.485 ;
        RECT 8.675 5.325 8.935 6.825 ;
        RECT 8.715 2.565 8.975 2.97 ;
        RECT 8.825 1.07 9.085 1.63 ;
        RECT 8.825 1.63 11.845 1.79 ;
        RECT 9.305 1.79 9.76 3.57 ;
        RECT 9.305 3.57 10.04 3.8 ;
        RECT 9.74 4.485 10.04 5.865 ;
        RECT 10.63 0.22 10.96 1.415 ;
        RECT 10.82 3.57 11.04 6.825 ;
        RECT 11.02 1.79 11.845 2.645 ;
        RECT 11.61 1.2 12.225 1.45 ;
        RECT 12.065 1.45 12.225 3.26 ;
  END
END sg13g2_hv_dlhrq_1

MACRO sg13g2_hv_dllr_1
  CLASS CORE ;
  ORIGIN 0 0 ;
  FOREIGN sg13g2_hv_dllr_1 0 0 ;
  SIZE 15.84 BY 7.14 ;
  SYMMETRY X Y ;
  SITE CoreSiteHV ;
  PIN D
    DIRECTION INPUT ;
    USE SIGNAL ;
    ANTENNAMODEL OXIDE1 ;
      ANTENNAGATEAREA 1.1542 LAYER Metal1 ;
    PORT
      LAYER Metal1 ;
        RECT 0.76 1.91 1.42 3.37 ;
    END
  END D
  PIN GATE_N
    DIRECTION INPUT ;
    USE SIGNAL ;
    ANTENNAMODEL OXIDE1 ;
      ANTENNAGATEAREA 1.2398 LAYER Metal1 ;
    PORT
      LAYER Metal1 ;
        RECT 1.61 1.92 2.74 3.37 ;
    END
  END GATE_N
  PIN RESET_B
    DIRECTION INPUT ;
    USE SIGNAL ;
    ANTENNAMODEL OXIDE1 ;
      ANTENNAGATEAREA 1.5435 LAYER Metal1 ;
    PORT
      LAYER Metal1 ;
        RECT 10.81 1.84 11.66 2.685 ;
    END
  END RESET_B
  PIN Q_N
    DIRECTION OUTPUT ;
    USE SIGNAL ;
    ANTENNADIFFAREA 1.1662 LAYER Metal1 ;
    PORT
      LAYER Metal1 ;
        RECT 14.975 3.25 15.41 5.805 ;
    END
  END Q_N
  PIN Q
    DIRECTION OUTPUT ;
    USE SIGNAL ;
    ANTENNADIFFAREA 1.1662 LAYER Metal1 ;
    PORT
      LAYER Metal1 ;
        RECT 12.69 2.995 13.025 5.565 ;
    END
  END Q
  PIN VDD
    DIRECTION INOUT ;
    USE POWER ;
    SHAPE ABUTMENT ;
    NETEXPR "VDD VDD!" ;
    PORT
      LAYER Metal1 ;
        RECT 0 6.825 15.84 7.36 ;
    END
  END VDD
  PIN VSS
    DIRECTION INOUT ;
    USE GROUND ;
    SHAPE ABUTMENT ;
    NETEXPR "VSS VSS!" ;
    PORT
      LAYER Metal1 ;
        RECT 0 -0.22 15.84 0.22 ;
    END
  END VSS
  OBS
      LAYER Metal1 ;
        RECT 0.38 1.305 0.66 1.615 ;
        RECT 0.38 1.615 0.54 3.93 ;
        RECT 0.38 3.93 2.485 4.315 ;
        RECT 0.38 4.315 0.655 5.77 ;
        RECT 1.225 5.23 1.485 6.825 ;
        RECT 1.27 0.22 1.53 1.665 ;
        RECT 1.82 4.315 2.485 5.36 ;
        RECT 1.82 5.36 3.47 5.77 ;
        RECT 2.485 1.025 3.12 1.72 ;
        RECT 2.86 4.065 3.12 4.11 ;
        RECT 2.86 4.11 4.895 4.495 ;
        RECT 2.86 4.495 3.13 4.75 ;
        RECT 2.96 1.72 3.12 4.065 ;
        RECT 3.3 1.035 3.56 1.44 ;
        RECT 3.3 1.44 7.4 1.46 ;
        RECT 3.3 1.46 8.13 1.6 ;
        RECT 3.3 1.6 3.55 1.655 ;
        RECT 3.3 1.655 3.47 2.97 ;
        RECT 3.3 2.97 3.78 3.68 ;
        RECT 3.3 4.95 5.26 5.335 ;
        RECT 3.3 5.335 3.47 5.36 ;
        RECT 3.845 1.895 6.725 1.94 ;
        RECT 3.845 1.94 4.895 2.645 ;
        RECT 3.9 1.78 6.725 1.895 ;
        RECT 4.65 2.645 4.895 4.11 ;
        RECT 4.84 0.22 5.1 1.25 ;
        RECT 4.88 5.77 5.14 6.825 ;
        RECT 5.08 2.565 5.745 3.13 ;
        RECT 5.08 3.13 5.26 4.95 ;
        RECT 5.795 3.56 6.525 3.955 ;
        RECT 5.795 3.955 5.995 5.85 ;
        RECT 5.795 5.85 8.19 6.295 ;
        RECT 5.96 1.94 6.725 2.545 ;
        RECT 5.96 2.545 6.55 2.625 ;
        RECT 5.96 2.625 6.525 3.56 ;
        RECT 6.615 4.58 6.905 5.37 ;
        RECT 6.665 1.025 8.725 1.26 ;
        RECT 6.745 2.73 9.225 3.13 ;
        RECT 6.745 3.13 6.905 4.58 ;
        RECT 7.015 1.6 8.13 1.9 ;
        RECT 7.015 1.9 8.11 2.09 ;
        RECT 7.015 2.09 8.13 2.545 ;
        RECT 7.41 3.73 8.19 5.85 ;
        RECT 7.9 1.44 8.13 1.46 ;
        RECT 8.315 1.26 8.725 1.87 ;
        RECT 8.315 1.87 9.62 2.645 ;
        RECT 8.315 2.645 9.225 2.73 ;
        RECT 8.67 3.56 12.24 3.67 ;
        RECT 8.67 3.67 11.035 4.305 ;
        RECT 9.225 0.22 9.455 1.595 ;
        RECT 9.235 5.035 9.91 6.825 ;
        RECT 9.71 0.985 10.055 1.7 ;
        RECT 9.82 1.7 10.055 3.055 ;
        RECT 9.82 3.055 12.24 3.56 ;
        RECT 10.47 4.305 11.035 5.65 ;
        RECT 11.55 0.22 11.85 1.59 ;
        RECT 11.665 4.1 11.96 6.825 ;
        RECT 11.845 1.91 12.775 2.645 ;
        RECT 11.845 2.645 12.24 3.055 ;
        RECT 12.565 0.965 13.08 1.565 ;
        RECT 12.565 1.565 13.15 1.68 ;
        RECT 12.96 1.68 13.15 2.995 ;
        RECT 13.025 2.995 13.15 3.56 ;
        RECT 13.245 3.93 13.54 5.385 ;
        RECT 13.26 1.155 13.55 1.41 ;
        RECT 13.33 1.41 13.55 1.95 ;
        RECT 13.33 1.95 14.875 2.725 ;
        RECT 13.33 2.725 13.54 3.93 ;
        RECT 14.155 0.22 14.415 1.65 ;
        RECT 14.22 3.225 14.4 6.825 ;
        RECT 15.045 0.97 15.41 1.65 ;
        RECT 15.165 1.65 15.41 3.25 ;
  END
END sg13g2_hv_dllr_1

MACRO sg13g2_hv_dllrq_1
  CLASS CORE ;
  ORIGIN 0 0 ;
  FOREIGN sg13g2_hv_dllrq_1 0 0 ;
  SIZE 13.92 BY 7.14 ;
  SYMMETRY X Y ;
  SITE CoreSiteHV ;
  PIN D
    DIRECTION INPUT ;
    USE SIGNAL ;
    ANTENNAMODEL OXIDE1 ;
      ANTENNAGATEAREA 1.1542 LAYER Metal1 ;
    PORT
      LAYER Metal1 ;
        RECT 0.775 2.125 1.585 2.985 ;
    END
  END D
  PIN GATE_N
    DIRECTION INPUT ;
    USE SIGNAL ;
    ANTENNAMODEL OXIDE1 ;
      ANTENNAGATEAREA 1.2398 LAYER Metal1 ;
    PORT
      LAYER Metal1 ;
        RECT 1.775 2.125 2.41 2.985 ;
    END
  END GATE_N
  PIN RESET_B
    DIRECTION INPUT ;
    USE SIGNAL ;
    ANTENNAMODEL OXIDE1 ;
      ANTENNAGATEAREA 1.4130 LAYER Metal1 ;
    PORT
      LAYER Metal1 ;
        RECT 11.075 1.72 11.835 2.87 ;
    END
  END RESET_B
  PIN Q
    DIRECTION OUTPUT ;
    USE SIGNAL ;
    ANTENNADIFFAREA 1.1662 LAYER Metal1 ;
    PORT
      LAYER Metal1 ;
        RECT 12.855 3.285 13.185 5.85 ;
    END
  END Q
  PIN VDD
    DIRECTION INOUT ;
    USE POWER ;
    SHAPE ABUTMENT ;
    NETEXPR "VDD VDD!" ;
    PORT
      LAYER Metal1 ;
        RECT 0 6.825 13.92 7.36 ;
    END
  END VDD
  PIN VSS
    DIRECTION INOUT ;
    USE GROUND ;
    SHAPE ABUTMENT ;
    NETEXPR "VSS VSS!" ;
    PORT
      LAYER Metal1 ;
        RECT 0 -0.22 13.92 0.22 ;
    END
  END VSS
  OBS
      LAYER Metal1 ;
        RECT 0.395 1.1 4.58 1.265 ;
        RECT 0.395 1.265 0.755 1.79 ;
        RECT 0.395 1.79 0.565 3.415 ;
        RECT 0.395 3.415 0.775 5.13 ;
        RECT 1.43 0.22 1.69 0.92 ;
        RECT 1.46 3.45 1.72 6.825 ;
        RECT 2.28 3.415 2.755 4.71 ;
        RECT 2.28 4.71 8.055 5.095 ;
        RECT 2.28 5.095 2.765 5.13 ;
        RECT 2.285 1.5 2.755 1.765 ;
        RECT 2.595 1.765 2.755 1.89 ;
        RECT 2.595 1.89 2.995 2.655 ;
        RECT 2.595 2.655 2.755 3.415 ;
        RECT 2.935 1.445 3.515 1.71 ;
        RECT 2.955 3.38 3.515 4.005 ;
        RECT 3.175 1.71 3.515 2.96 ;
        RECT 3.175 2.96 6.09 3.345 ;
        RECT 3.175 3.345 3.515 3.38 ;
        RECT 3.865 0.22 5.23 0.92 ;
        RECT 3.885 5.54 4.145 6.825 ;
        RECT 4.005 1.265 4.58 2.575 ;
        RECT 4.935 1.73 8.255 2.49 ;
        RECT 4.935 2.49 6.09 2.96 ;
        RECT 5.635 3.775 6.655 4.185 ;
        RECT 6.275 2.675 9.435 2.985 ;
        RECT 6.275 2.985 6.655 3.775 ;
        RECT 7.165 0.99 7.68 1.345 ;
        RECT 7.165 1.345 9.42 1.505 ;
        RECT 7.44 3.415 8.055 4.71 ;
        RECT 8.445 3.415 10.775 3.595 ;
        RECT 8.445 3.595 12.48 3.98 ;
        RECT 8.445 3.98 11.115 4.21 ;
        RECT 9.04 4.76 9.72 6.825 ;
        RECT 9.075 0.22 9.335 1.155 ;
        RECT 9.25 1.505 9.42 1.84 ;
        RECT 9.25 1.84 9.66 2.615 ;
        RECT 9.25 2.615 9.435 2.675 ;
        RECT 9.615 0.925 10.775 1.63 ;
        RECT 10.005 1.63 10.775 3.415 ;
        RECT 10.62 4.21 11.115 5.55 ;
        RECT 11.75 4.425 12.005 6.825 ;
        RECT 11.775 0.22 12.035 1.535 ;
        RECT 12.015 1.86 12.845 2.635 ;
        RECT 12.015 2.635 12.48 3.595 ;
        RECT 12.835 0.93 13.185 1.63 ;
        RECT 13.025 1.63 13.185 3.285 ;
  END
END sg13g2_hv_dllrq_1

MACRO sg13g2_hv_dlygate4sd1_1
  CLASS CORE ;
  ORIGIN 0 0 ;
  FOREIGN sg13g2_hv_dlygate4sd1_1 0 0 ;
  SIZE 5.28 BY 7.14 ;
  SYMMETRY X Y ;
  SITE CoreSiteHV ;
  PIN A
    DIRECTION INPUT ;
    USE SIGNAL ;
    ANTENNAMODEL OXIDE1 ;
      ANTENNAGATEAREA 0.6435 LAYER Metal1 ;
    PORT
      LAYER Metal1 ;
        RECT 0.24 1.855 1.23 2.95 ;
    END
  END A
  PIN X
    DIRECTION OUTPUT ;
    USE SIGNAL ;
    ANTENNADIFFAREA 1.1662 LAYER Metal1 ;
    PORT
      LAYER Metal1 ;
        RECT 4.06 1.55 5.04 1.8 ;
    END
  END X
  PIN VDD
    DIRECTION INOUT ;
    USE POWER ;
    SHAPE ABUTMENT ;
    NETEXPR "VDD VDD!" ;
    PORT
      LAYER Metal1 ;
        RECT 0 6.825 5.28 7.36 ;
    END
  END VDD
  PIN VSS
    DIRECTION INOUT ;
    USE GROUND ;
    SHAPE ABUTMENT ;
    NETEXPR "VSS VSS!" ;
    PORT
      LAYER Metal1 ;
        RECT 0 -0.22 5.28 0.22 ;
    END
  END VSS
  OBS
      LAYER Metal1 ;
        RECT 0.21 1.04 0.48 1.495 ;
        RECT 0.21 1.495 1.855 1.67 ;
        RECT 0.24 3.55 1.855 4.04 ;
        RECT 0.24 4.04 0.5 5.265 ;
        RECT 1.265 0.22 1.525 1.3 ;
        RECT 1.305 4.64 1.565 6.825 ;
        RECT 1.515 1.67 1.855 3.55 ;
        RECT 2.235 1.045 2.525 1.3 ;
        RECT 2.235 4.555 2.54 5.35 ;
        RECT 2.295 1.3 2.525 2.225 ;
        RECT 2.295 2.225 3.13 2.705 ;
        RECT 2.295 2.705 2.54 4.555 ;
        RECT 2.855 3.15 4.27 3.57 ;
        RECT 2.855 3.57 3.165 4.03 ;
        RECT 2.87 1.39 3.11 1.59 ;
        RECT 2.87 1.59 3.615 1.79 ;
        RECT 3.31 1.79 3.615 2.025 ;
        RECT 3.31 2.025 4.545 2.685 ;
        RECT 3.935 4.17 4.195 6.825 ;
        RECT 3.95 0.22 4.21 1.3 ;
        RECT 4.08 2.685 4.27 3.15 ;
        RECT 4.78 1.04 5.04 1.55 ;
        RECT 4.785 3.61 5.04 5.865 ;
        RECT 4.85 1.8 5.04 3.61 ;
  END
END sg13g2_hv_dlygate4sd1_1

MACRO sg13g2_hv_dlygate4sd2_1
  CLASS CORE ;
  ORIGIN 0 0 ;
  FOREIGN sg13g2_hv_dlygate4sd2_1 0 0 ;
  SIZE 5.76 BY 7.14 ;
  SYMMETRY X Y ;
  SITE CoreSiteHV ;
  PIN A
    DIRECTION INPUT ;
    USE SIGNAL ;
    ANTENNAMODEL OXIDE1 ;
      ANTENNAGATEAREA 0.6435 LAYER Metal1 ;
    PORT
      LAYER Metal1 ;
        RECT 0.205 1.89 1.23 2.95 ;
    END
  END A
  PIN X
    DIRECTION OUTPUT ;
    USE SIGNAL ;
    ANTENNADIFFAREA 1.1662 LAYER Metal1 ;
    PORT
      LAYER Metal1 ;
        RECT 4.21 1.545 5.15 1.8 ;
    END
  END X
  PIN VDD
    DIRECTION INOUT ;
    USE POWER ;
    SHAPE ABUTMENT ;
    NETEXPR "VDD VDD!" ;
    PORT
      LAYER Metal1 ;
        RECT 0 6.825 5.76 7.36 ;
    END
  END VDD
  PIN VSS
    DIRECTION INOUT ;
    USE GROUND ;
    SHAPE ABUTMENT ;
    NETEXPR "VSS VSS!" ;
    PORT
      LAYER Metal1 ;
        RECT 0 -0.22 5.76 0.22 ;
    END
  END VSS
  OBS
      LAYER Metal1 ;
        RECT 0.21 1.04 0.48 1.495 ;
        RECT 0.21 1.495 1.955 1.67 ;
        RECT 0.24 3.55 1.955 4.04 ;
        RECT 0.24 4.04 0.5 5.265 ;
        RECT 1.14 4.64 1.405 6.825 ;
        RECT 1.255 0.22 1.515 1.3 ;
        RECT 1.515 1.67 1.955 3.55 ;
        RECT 2.29 1.04 2.58 1.3 ;
        RECT 2.29 4.555 2.595 5.35 ;
        RECT 2.35 1.3 2.58 2.075 ;
        RECT 2.35 2.075 3.17 2.69 ;
        RECT 2.35 2.69 2.595 4.555 ;
        RECT 2.925 1.39 3.165 1.59 ;
        RECT 2.925 1.59 3.755 1.79 ;
        RECT 2.935 3.15 4.35 3.57 ;
        RECT 2.935 3.57 3.195 5.575 ;
        RECT 3.355 1.79 3.755 2.025 ;
        RECT 3.355 2.025 4.655 2.685 ;
        RECT 4.045 4.17 4.305 6.825 ;
        RECT 4.06 0.22 4.32 1.3 ;
        RECT 4.19 2.685 4.35 3.15 ;
        RECT 4.89 1.04 5.15 1.545 ;
        RECT 4.895 3.61 5.15 5.865 ;
        RECT 4.96 1.8 5.15 3.61 ;
  END
END sg13g2_hv_dlygate4sd2_1

MACRO sg13g2_hv_dlygate4sd3_1
  CLASS CORE ;
  ORIGIN 0 0 ;
  FOREIGN sg13g2_hv_dlygate4sd3_1 0 0 ;
  SIZE 5.28 BY 7.14 ;
  SYMMETRY X Y ;
  SITE CoreSiteHV ;
  PIN A
    DIRECTION INPUT ;
    USE SIGNAL ;
    ANTENNAMODEL OXIDE1 ;
      ANTENNAGATEAREA 0.6435 LAYER Metal1 ;
    PORT
      LAYER Metal1 ;
        RECT 0.285 1.84 1.235 3.27 ;
    END
  END A
  PIN VDD
    DIRECTION INOUT ;
    USE POWER ;
    SHAPE ABUTMENT ;
    NETEXPR "VDD VDD!" ;
    PORT
      LAYER Metal1 ;
        RECT 0 6.825 5.28 7.36 ;
    END
  END VDD
  PIN VSS
    DIRECTION INOUT ;
    USE GROUND ;
    SHAPE ABUTMENT ;
    NETEXPR "VSS VSS!" ;
    PORT
      LAYER Metal1 ;
        RECT 0 -0.22 5.28 0.22 ;
    END
  END VSS
  PIN X
    DIRECTION OUTPUT ;
    USE SIGNAL ;
    ANTENNADIFFAREA 1.1662 LAYER Metal1 ;
    PORT
      LAYER Metal1 ;
        RECT 4.32 3.26 4.685 5.89 ;
    END
  END X
  OBS
      LAYER Metal1 ;
        RECT 0.3 1.12 0.56 1.445 ;
        RECT 0.3 1.445 1.775 1.635 ;
        RECT 0.3 3.85 1.775 4.23 ;
        RECT 0.3 4.23 0.56 5.19 ;
        RECT 1.12 0.22 1.39 1.265 ;
        RECT 1.13 4.675 1.39 6.825 ;
        RECT 1.495 1.635 1.775 3.85 ;
        RECT 2.01 3.61 2.275 5.865 ;
        RECT 2.04 1.095 2.275 2.025 ;
        RECT 2.04 2.025 3.245 2.685 ;
        RECT 2.04 2.685 2.275 3.61 ;
        RECT 2.525 1.375 2.79 1.475 ;
        RECT 2.525 1.475 3.66 1.665 ;
        RECT 2.53 3.19 3.66 3.595 ;
        RECT 2.53 3.595 2.79 5.575 ;
        RECT 3.44 4.425 3.7 6.825 ;
        RECT 3.45 0.22 3.71 1.28 ;
        RECT 3.47 1.665 3.66 1.945 ;
        RECT 3.47 1.945 4.09 2.72 ;
        RECT 3.47 2.72 3.66 3.19 ;
        RECT 4.275 1.025 4.685 1.77 ;
        RECT 4.47 1.77 4.685 3.26 ;
  END
END sg13g2_hv_dlygate4sd3_1

MACRO sg13g2_hv_ebufn_2
  CLASS CORE ;
  ORIGIN 0 0 ;
  FOREIGN sg13g2_hv_ebufn_2 0 0 ;
  SIZE 8.64 BY 7.14 ;
  SYMMETRY X Y ;
  SITE CoreSiteHV ;
  PIN TE_B
    DIRECTION INPUT ;
    USE SIGNAL ;
    ANTENNAMODEL OXIDE1 ;
      ANTENNAGATEAREA 3.7890 LAYER Metal1 ;
    PORT
      LAYER Metal1 ;
        RECT 5.585 1.8 6.455 2.725 ;
    END
  END TE_B
  PIN A
    DIRECTION INPUT ;
    USE SIGNAL ;
    ANTENNAMODEL OXIDE1 ;
      ANTENNAGATEAREA 1.3680 LAYER Metal1 ;
    PORT
      LAYER Metal1 ;
        RECT 6.665 1.8 7.32 2.725 ;
    END
  END A
  PIN Z
    DIRECTION OUTPUT ;
    USE SIGNAL ;
    ANTENNADIFFAREA 1.3034 LAYER Metal1 ;
    PORT
      LAYER Metal1 ;
        RECT 1.355 3.49 1.665 4.915 ;
    END
  END Z
  PIN VDD
    DIRECTION INOUT ;
    USE POWER ;
    SHAPE ABUTMENT ;
    NETEXPR "VDD VDD!" ;
    PORT
      LAYER Metal1 ;
        RECT 0 6.825 8.64 7.36 ;
    END
  END VDD
  PIN VSS
    DIRECTION INOUT ;
    USE GROUND ;
    SHAPE ABUTMENT ;
    NETEXPR "VSS VSS!" ;
    PORT
      LAYER Metal1 ;
        RECT 0 -0.22 8.64 0.22 ;
    END
  END VSS
  OBS
      LAYER Metal1 ;
        RECT 0.25 0.87 2.565 1.065 ;
        RECT 0.25 1.065 0.51 1.59 ;
        RECT 0.33 4.305 0.64 5.66 ;
        RECT 0.33 5.66 2.695 6.045 ;
        RECT 1.16 1.275 1.54 1.51 ;
        RECT 1.16 1.51 1.425 3.49 ;
        RECT 1.16 3.49 1.355 3.99 ;
        RECT 1.665 1.93 2.39 2.475 ;
        RECT 1.665 2.475 4.95 2.635 ;
        RECT 2.255 1.065 2.565 1.43 ;
        RECT 2.255 1.43 4.945 1.59 ;
        RECT 2.385 3.49 2.695 5.215 ;
        RECT 2.385 5.215 5.12 5.6 ;
        RECT 2.385 5.6 2.695 5.66 ;
        RECT 3.28 0.22 3.59 1.25 ;
        RECT 3.44 6.03 3.825 6.825 ;
        RECT 4.56 0.97 4.945 1.43 ;
        RECT 4.765 2.635 4.95 4.39 ;
        RECT 4.765 4.39 7.85 4.785 ;
        RECT 4.86 5.6 5.12 5.865 ;
        RECT 5.13 1.405 5.78 1.59 ;
        RECT 5.13 1.59 5.345 3.27 ;
        RECT 5.13 3.27 5.65 3.895 ;
        RECT 5.48 0.99 5.78 1.405 ;
        RECT 6.49 5.275 6.75 6.825 ;
        RECT 6.53 0.22 6.79 1.56 ;
        RECT 7.475 1.025 7.85 1.56 ;
        RECT 7.555 3.27 7.85 4.39 ;
        RECT 7.555 4.785 7.85 5.575 ;
        RECT 7.66 1.56 7.85 3.27 ;
  END
END sg13g2_hv_ebufn_2

MACRO sg13g2_hv_ebufn_4
  CLASS CORE ;
  ORIGIN 0 0 ;
  FOREIGN sg13g2_hv_ebufn_4 0 0 ;
  SIZE 11.04 BY 7.14 ;
  SYMMETRY X Y ;
  SITE CoreSiteHV ;
  PIN A
    DIRECTION INPUT ;
    USE SIGNAL ;
    ANTENNAMODEL OXIDE1 ;
      ANTENNAGATEAREA 1.5435 LAYER Metal1 ;
    PORT
      LAYER Metal1 ;
        RECT 0.775 2.985 1.9 3.655 ;
    END
  END A
  PIN TE_B
    DIRECTION INPUT ;
    USE SIGNAL ;
    ANTENNAMODEL OXIDE1 ;
      ANTENNAGATEAREA 6.3855 LAYER Metal1 ;
    PORT
      LAYER Metal1 ;
        RECT 2.295 1.45 2.675 2.575 ;
    END
  END TE_B
  PIN Z
    DIRECTION OUTPUT ;
    USE SIGNAL ;
    ANTENNADIFFAREA 2.6068 LAYER Metal1 ;
    PORT
      LAYER Metal1 ;
        RECT 7.81 1.575 9.745 1.805 ;
    END
  END Z
  PIN VDD
    DIRECTION INOUT ;
    USE POWER ;
    SHAPE ABUTMENT ;
    NETEXPR "VDD VDD!" ;
    PORT
      LAYER Metal1 ;
        RECT 0 6.825 11.04 7.36 ;
    END
  END VDD
  PIN VSS
    DIRECTION INOUT ;
    USE GROUND ;
    SHAPE ABUTMENT ;
    NETEXPR "VSS VSS!" ;
    PORT
      LAYER Metal1 ;
        RECT 0 -0.22 11.04 0.22 ;
    END
  END VSS
  OBS
      LAYER Metal1 ;
        RECT 0.28 1.02 0.54 1.62 ;
        RECT 0.28 1.62 0.445 4.41 ;
        RECT 0.28 4.41 0.74 4.45 ;
        RECT 0.28 4.45 3.215 4.83 ;
        RECT 0.28 4.83 0.74 5.89 ;
        RECT 0.775 1.965 1.48 2.985 ;
        RECT 1.31 0.22 1.63 1.62 ;
        RECT 1.455 5.265 1.78 6.825 ;
        RECT 2.35 1.02 3.45 1.27 ;
        RECT 2.495 2.78 3.45 3.2 ;
        RECT 2.495 3.2 2.755 4.015 ;
        RECT 2.675 1.85 2.95 2.575 ;
        RECT 3.055 3.63 4.615 4.015 ;
        RECT 3.055 4.015 3.215 4.45 ;
        RECT 3.19 0.965 3.45 1.02 ;
        RECT 3.19 1.27 3.45 2.78 ;
        RECT 3.655 1.02 3.915 1.77 ;
        RECT 3.655 1.77 7.195 1.94 ;
        RECT 3.655 4.52 5.575 4.915 ;
        RECT 3.655 4.915 3.915 5.89 ;
        RECT 4.445 2.575 8.95 2.735 ;
        RECT 4.445 2.735 4.615 3.63 ;
        RECT 4.485 0.22 4.745 1.59 ;
        RECT 4.485 5.35 4.745 6.825 ;
        RECT 5.315 1.02 5.575 1.77 ;
        RECT 5.315 3.355 7.22 3.74 ;
        RECT 5.315 3.74 5.575 4.52 ;
        RECT 5.315 4.915 5.575 5.89 ;
        RECT 6.145 0.22 6.405 1.59 ;
        RECT 6.145 4.45 6.405 6.825 ;
        RECT 6.975 0.885 10.575 1.055 ;
        RECT 6.975 1.055 7.195 1.77 ;
        RECT 6.99 3.74 7.22 5.89 ;
        RECT 6.99 5.89 10.575 6.27 ;
        RECT 7.555 2.47 8.95 2.575 ;
        RECT 7.81 1.36 8.07 1.575 ;
        RECT 7.815 3.345 9.745 3.885 ;
        RECT 7.815 3.885 8.075 5.07 ;
        RECT 8.65 1.055 8.91 1.28 ;
        RECT 8.655 4.45 8.915 5.89 ;
        RECT 9.48 1.36 9.745 1.575 ;
        RECT 9.485 3.885 9.745 5.07 ;
        RECT 9.565 1.805 9.745 3.345 ;
        RECT 10.315 1.055 10.575 1.62 ;
        RECT 10.315 3.63 10.575 5.89 ;
  END
END sg13g2_hv_ebufn_4

MACRO sg13g2_hv_ebufn_8
  CLASS CORE ;
  ORIGIN 0 0 ;
  FOREIGN sg13g2_hv_ebufn_8 0 0 ;
  SIZE 19.2 BY 7.14 ;
  SYMMETRY X Y ;
  SITE CoreSiteHV ;
  PIN Z
    DIRECTION OUTPUT ;
    USE SIGNAL ;
    ANTENNADIFFAREA 5.2136 LAYER Metal1 ;
    PORT
      LAYER Metal1 ;
        RECT 1.1 1.79 1.78 3.79 ;
    END
  END Z
  PIN A
    DIRECTION INPUT ;
    USE SIGNAL ;
    ANTENNAMODEL OXIDE1 ;
      ANTENNAGATEAREA 3.0870 LAYER Metal1 ;
    PORT
      LAYER Metal1 ;
        RECT 17.425 1.94 18.205 2.71 ;
    END
  END A
  PIN TE_B
    DIRECTION INPUT ;
    USE SIGNAL ;
    ANTENNAMODEL OXIDE1 ;
      ANTENNAGATEAREA 11.2275 LAYER Metal1 ;
    PORT
      LAYER Metal1 ;
        RECT 15.855 1.94 17.115 2.71 ;
    END
  END TE_B
  PIN VDD
    DIRECTION INOUT ;
    USE POWER ;
    SHAPE ABUTMENT ;
    NETEXPR "VDD VDD!" ;
    PORT
      LAYER Metal1 ;
        RECT 0 6.825 19.2 7.36 ;
    END
  END VDD
  PIN VSS
    DIRECTION INOUT ;
    USE GROUND ;
    SHAPE ABUTMENT ;
    NETEXPR "VSS VSS!" ;
    PORT
      LAYER Metal1 ;
        RECT 0 -0.22 19.2 0.22 ;
    END
  END VSS
  OBS
      LAYER Metal1 ;
        RECT 0.15 0.96 7.085 1.16 ;
        RECT 0.15 1.16 0.405 1.77 ;
        RECT 0.16 3.44 0.42 5.85 ;
        RECT 0.16 5.85 7.06 6.26 ;
        RECT 0.99 1.35 1.25 1.6 ;
        RECT 0.99 1.6 6.23 1.79 ;
        RECT 0.99 1.79 1.1 1.895 ;
        RECT 0.99 3.13 1.1 3.79 ;
        RECT 0.99 3.79 1.25 5.12 ;
        RECT 1.78 3.37 6.23 3.775 ;
        RECT 1.78 3.775 4.57 3.79 ;
        RECT 1.82 1.16 2.08 1.405 ;
        RECT 1.82 4.495 2.08 5.85 ;
        RECT 2.415 2.37 6.235 2.605 ;
        RECT 2.415 2.605 7.005 2.825 ;
        RECT 2.645 1.35 2.91 1.6 ;
        RECT 2.65 3.79 2.91 5.12 ;
        RECT 3.48 1.16 3.74 1.415 ;
        RECT 3.48 4.495 3.74 5.85 ;
        RECT 4.31 1.35 4.57 1.6 ;
        RECT 4.31 3.79 4.57 5.12 ;
        RECT 5.14 1.16 5.4 1.415 ;
        RECT 5.14 4.495 5.4 5.85 ;
        RECT 5.97 1.345 6.23 1.6 ;
        RECT 5.97 3.775 6.23 5.12 ;
        RECT 6.795 2.825 7.005 3.68 ;
        RECT 6.795 3.68 15.175 4.065 ;
        RECT 6.8 4.495 12.97 4.94 ;
        RECT 6.8 4.94 11.02 4.95 ;
        RECT 6.8 4.95 7.06 5.85 ;
        RECT 6.82 1.16 7.085 1.81 ;
        RECT 6.82 1.81 9.115 2.025 ;
        RECT 7.675 2.025 14.835 2.595 ;
        RECT 7.78 5.41 8.05 6.825 ;
        RECT 7.855 0.22 8.125 1.63 ;
        RECT 8.77 4.95 9.04 5.935 ;
        RECT 8.845 1.17 9.115 1.81 ;
        RECT 9.76 5.385 10.03 6.825 ;
        RECT 9.835 0.22 10.095 1.655 ;
        RECT 10.755 4.95 11.02 5.935 ;
        RECT 10.815 1.17 11.075 2.025 ;
        RECT 11.73 5.385 11.99 6.825 ;
        RECT 11.79 0.22 12.05 1.655 ;
        RECT 12.71 4.94 12.97 5.095 ;
        RECT 12.71 5.095 14.835 5.53 ;
        RECT 12.71 5.53 12.97 5.935 ;
        RECT 12.77 1.17 13.03 2.025 ;
        RECT 13.71 5.97 13.975 6.825 ;
        RECT 13.745 0.22 14.005 1.655 ;
        RECT 14.575 1.17 14.835 2.025 ;
        RECT 14.575 5.53 14.835 5.935 ;
        RECT 14.995 4.065 15.175 4.425 ;
        RECT 14.995 4.425 18.09 4.82 ;
        RECT 15.065 1.07 16.43 1.315 ;
        RECT 15.355 1.315 15.59 3.32 ;
        RECT 15.355 3.32 16.43 3.99 ;
        RECT 16.17 1.315 16.43 1.67 ;
        RECT 17 0.22 17.26 1.67 ;
        RECT 17 5.31 17.26 6.825 ;
        RECT 17.83 1.07 18.09 1.51 ;
        RECT 17.83 1.51 18.915 1.67 ;
        RECT 17.83 3.655 18.915 4.135 ;
        RECT 17.83 4.135 18.09 4.425 ;
        RECT 17.83 4.82 18.09 5.935 ;
        RECT 18.66 0.22 18.92 1.33 ;
        RECT 18.66 4.57 18.92 6.825 ;
        RECT 18.74 1.67 18.915 3.655 ;
  END
END sg13g2_hv_ebufn_8

MACRO sg13g2_hv_einvn_2
  CLASS CORE ;
  ORIGIN 0 0 ;
  FOREIGN sg13g2_hv_einvn_2 0 0 ;
  SIZE 6.24 BY 7.14 ;
  SYMMETRY X Y ;
  SITE CoreSiteHV ;
  PIN Z
    DIRECTION OUTPUT ;
    USE SIGNAL ;
    ANTENNADIFFAREA 1.3034 LAYER Metal1 ;
    PORT
      LAYER Metal1 ;
        RECT 4.44 1.435 4.795 5.06 ;
        RECT 4.795 1.435 4.8 5.06 ;
    END
  END Z
  PIN A
    DIRECTION INPUT ;
    USE SIGNAL ;
    ANTENNAMODEL OXIDE1 ;
      ANTENNAGATEAREA 3.0870 LAYER Metal1 ;
    PORT
      LAYER Metal1 ;
        RECT 5.325 1.44 5.655 2.625 ;
        RECT 5.28 1.44 5.325 2.625 ;
    END
  END A
  PIN TE_B
    DIRECTION INPUT ;
    USE SIGNAL ;
    ANTENNAMODEL OXIDE1 ;
      ANTENNAGATEAREA 3.3007 LAYER Metal1 ;
    PORT
      LAYER Metal1 ;
        RECT 0.28 1.75 1.18 3.87 ;
    END
  END TE_B
  PIN VDD
    DIRECTION INOUT ;
    USE POWER ;
    SHAPE ABUTMENT ;
    NETEXPR "VDD VDD!" ;
    PORT
      LAYER Metal1 ;
        RECT 0 6.825 6.24 7.36 ;
    END
  END VDD
  PIN VSS
    DIRECTION INOUT ;
    USE GROUND ;
    SHAPE ABUTMENT ;
    NETEXPR "VSS VSS!" ;
    PORT
      LAYER Metal1 ;
        RECT 0 -0.22 6.24 0.22 ;
    END
  END VSS
  OBS
      LAYER Metal1 ;
        RECT 0.6 0.22 0.865 1.34 ;
        RECT 0.6 4.425 0.86 6.825 ;
        RECT 1.405 4.425 1.705 5.865 ;
        RECT 1.435 1.08 1.7 1.34 ;
        RECT 1.535 1.34 1.7 1.95 ;
        RECT 1.535 1.95 1.975 2.725 ;
        RECT 1.535 2.725 1.705 4.425 ;
        RECT 1.95 3.595 3.87 3.99 ;
        RECT 1.95 3.99 2.21 5.865 ;
        RECT 1.975 1.005 2.22 1.46 ;
        RECT 1.975 1.46 3.87 1.625 ;
        RECT 2.78 0.22 3.04 1.28 ;
        RECT 2.78 4.425 3.04 6.825 ;
        RECT 3.61 1.02 5.575 1.255 ;
        RECT 3.61 1.255 3.87 1.46 ;
        RECT 3.61 3.99 3.87 5.9 ;
        RECT 3.61 5.9 5.555 6.285 ;
        RECT 5.295 3.61 5.555 5.9 ;
  END
END sg13g2_hv_einvn_2

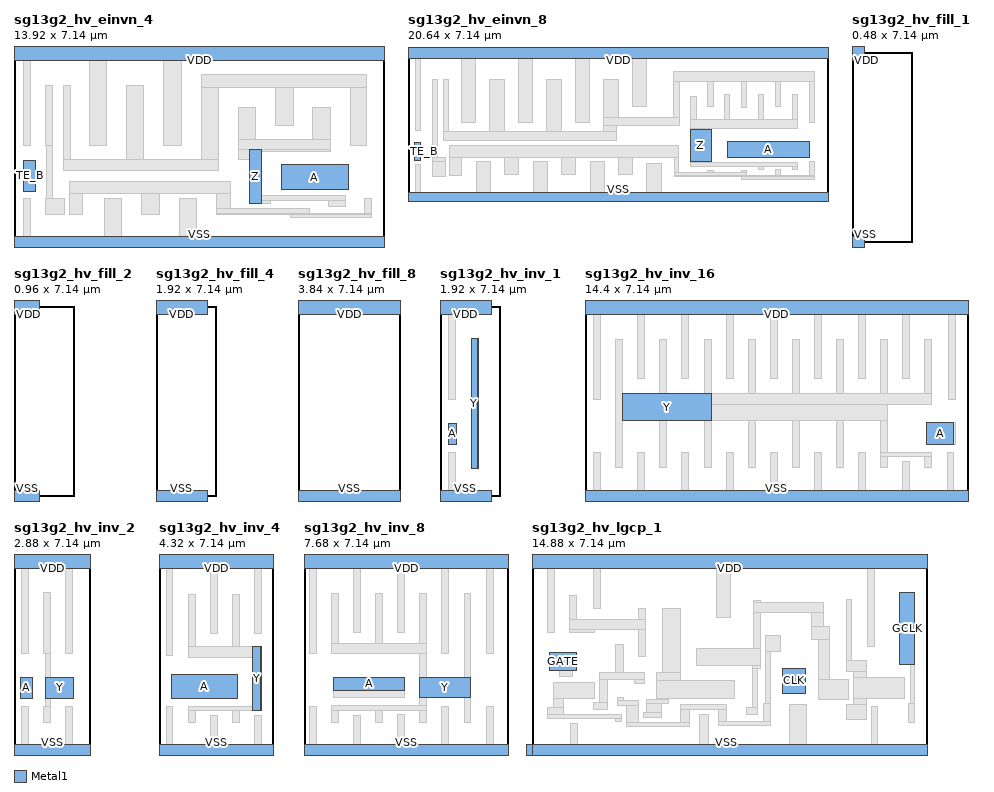
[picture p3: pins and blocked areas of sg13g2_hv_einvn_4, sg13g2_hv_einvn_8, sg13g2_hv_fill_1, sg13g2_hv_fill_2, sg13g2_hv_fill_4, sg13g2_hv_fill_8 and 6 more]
MACRO sg13g2_hv_einvn_4
  CLASS CORE ;
  ORIGIN 0 0 ;
  FOREIGN sg13g2_hv_einvn_4 0 0 ;
  SIZE 13.92 BY 7.14 ;
  SYMMETRY X Y ;
  SITE CoreSiteHV ;
  PIN Z
    DIRECTION OUTPUT ;
    USE SIGNAL ;
    ANTENNADIFFAREA 2.6068 LAYER Metal1 ;
    PORT
      LAYER Metal1 ;
        RECT 8.85 1.455 9.29 3.49 ;
    END
  END Z
  PIN A
    DIRECTION INPUT ;
    USE SIGNAL ;
    ANTENNAMODEL OXIDE1 ;
      ANTENNAGATEAREA 6.1740 LAYER Metal1 ;
    PORT
      LAYER Metal1 ;
        RECT 10.045 1.97 12.565 2.9 ;
    END
  END A
  PIN TE_B
    DIRECTION INPUT ;
    USE SIGNAL ;
    ANTENNAMODEL OXIDE1 ;
      ANTENNAGATEAREA 6.3855 LAYER Metal1 ;
    PORT
      LAYER Metal1 ;
        RECT 0.34 1.89 0.825 3.08 ;
    END
  END TE_B
  PIN VDD
    DIRECTION INOUT ;
    USE POWER ;
    SHAPE ABUTMENT ;
    NETEXPR "VDD VDD!" ;
    PORT
      LAYER Metal1 ;
        RECT 0 6.825 13.92 7.36 ;
    END
  END VDD
  PIN VSS
    DIRECTION INOUT ;
    USE GROUND ;
    SHAPE ABUTMENT ;
    NETEXPR "VSS VSS!" ;
    PORT
      LAYER Metal1 ;
        RECT 0 -0.22 13.92 0.22 ;
    END
  END VSS
  OBS
      LAYER Metal1 ;
        RECT 0.365 0.22 0.625 1.64 ;
        RECT 0.365 3.61 0.625 6.825 ;
        RECT 1.195 1.04 1.89 1.64 ;
        RECT 1.195 3.61 1.455 5.865 ;
        RECT 1.23 1.64 1.455 3.61 ;
        RECT 1.85 2.67 7.685 3.105 ;
        RECT 1.85 3.105 2.11 5.865 ;
        RECT 2.09 1.04 2.57 1.835 ;
        RECT 2.09 1.835 8.15 2.27 ;
        RECT 2.835 3.61 3.485 6.825 ;
        RECT 3.405 0.22 4.055 1.64 ;
        RECT 4.235 3.105 4.885 5.865 ;
        RECT 4.805 1.04 5.455 1.835 ;
        RECT 5.635 3.61 6.285 6.825 ;
        RECT 6.205 0.22 6.855 1.64 ;
        RECT 7.035 3.105 7.685 5.815 ;
        RECT 7.035 5.815 13.24 6.285 ;
        RECT 7.605 1.035 13.44 1.075 ;
        RECT 7.605 1.075 11.09 1.27 ;
        RECT 7.605 1.27 8.15 1.835 ;
        RECT 8.435 3.115 8.85 3.49 ;
        RECT 8.435 3.49 11.885 3.87 ;
        RECT 8.435 3.87 9.085 5.05 ;
        RECT 9.29 1.455 9.655 1.545 ;
        RECT 9.29 1.545 12.455 1.735 ;
        RECT 9.29 3.39 11.885 3.49 ;
        RECT 9.835 4.375 10.485 5.815 ;
        RECT 10.375 0.905 13.44 1.035 ;
        RECT 11.235 3.87 11.885 5.05 ;
        RECT 11.805 1.32 12.455 1.545 ;
        RECT 12.635 3.61 13.24 5.815 ;
        RECT 13.18 1.075 13.44 1.64 ;
  END
END sg13g2_hv_einvn_4

MACRO sg13g2_hv_einvn_8
  CLASS CORE ;
  ORIGIN 0 0 ;
  FOREIGN sg13g2_hv_einvn_8 0 0 ;
  SIZE 20.64 BY 7.14 ;
  SYMMETRY X Y ;
  SITE CoreSiteHV ;
  PIN A
    DIRECTION INPUT ;
    USE SIGNAL ;
    ANTENNAMODEL OXIDE1 ;
      ANTENNAGATEAREA 12.3480 LAYER Metal1 ;
    PORT
      LAYER Metal1 ;
        RECT 15.7 1.94 19.71 2.72 ;
    END
  END A
  PIN Z
    DIRECTION OUTPUT ;
    USE SIGNAL ;
    ANTENNADIFFAREA 5.2136 LAYER Metal1 ;
    PORT
      LAYER Metal1 ;
        RECT 13.89 1.735 14.905 3.32 ;
    END
  END Z
  PIN TE_B
    DIRECTION INPUT ;
    USE SIGNAL ;
    ANTENNAMODEL OXIDE1 ;
      ANTENNAGATEAREA 11.2275 LAYER Metal1 ;
    PORT
      LAYER Metal1 ;
        RECT 0.3 1.8 0.63 2.695 ;
    END
  END TE_B
  PIN VDD
    DIRECTION INOUT ;
    USE POWER ;
    SHAPE ABUTMENT ;
    NETEXPR "VDD VDD!" ;
    PORT
      LAYER Metal1 ;
        RECT 0 6.825 20.64 7.36 ;
    END
  END VDD
  PIN VSS
    DIRECTION INOUT ;
    USE GROUND ;
    SHAPE ABUTMENT ;
    NETEXPR "VSS VSS!" ;
    PORT
      LAYER Metal1 ;
        RECT 0 -0.22 20.64 0.22 ;
    END
  END VSS
  OBS
      LAYER Metal1 ;
        RECT 0.35 3.27 0.61 6.825 ;
        RECT 0.355 0.22 0.615 1.61 ;
        RECT 1.19 1.75 1.85 1.955 ;
        RECT 1.19 1.955 1.45 5.79 ;
        RECT 1.21 1.005 1.85 1.75 ;
        RECT 1.74 2.78 10.235 3.21 ;
        RECT 1.74 3.21 2 5.79 ;
        RECT 2.05 1.045 2.635 1.92 ;
        RECT 2.05 1.92 13.315 2.535 ;
        RECT 2.63 3.67 3.33 6.825 ;
        RECT 3.345 0.22 4.05 1.73 ;
        RECT 4.025 3.21 4.73 5.77 ;
        RECT 4.745 1.1 5.45 1.92 ;
        RECT 5.425 3.67 6.13 6.825 ;
        RECT 6.145 0.22 6.85 1.73 ;
        RECT 6.825 3.21 7.53 5.77 ;
        RECT 7.545 1.1 8.25 1.92 ;
        RECT 8.225 3.67 8.93 6.825 ;
        RECT 8.945 0.22 9.65 1.73 ;
        RECT 9.625 3.21 10.235 3.49 ;
        RECT 9.625 3.49 13.335 3.895 ;
        RECT 9.625 3.895 10.33 5.77 ;
        RECT 10.345 1.095 11.05 1.92 ;
        RECT 11.025 4.435 11.73 6.825 ;
        RECT 11.745 0.22 12.45 1.64 ;
        RECT 13.06 3.895 13.335 5.685 ;
        RECT 13.06 5.685 19.97 6.19 ;
        RECT 13.075 1 19.97 1.045 ;
        RECT 13.075 1.045 16.65 1.22 ;
        RECT 13.075 1.22 13.315 1.92 ;
        RECT 13.89 1.485 14.155 1.52 ;
        RECT 13.89 1.52 19.14 1.71 ;
        RECT 13.89 1.71 14.905 1.735 ;
        RECT 13.89 3.32 14.905 3.37 ;
        RECT 13.89 3.37 19.14 3.825 ;
        RECT 13.89 3.825 14.155 4.93 ;
        RECT 14.73 1.22 14.99 1.285 ;
        RECT 14.73 4.47 14.995 5.685 ;
        RECT 15.56 1.485 15.82 1.52 ;
        RECT 15.56 3.825 15.82 5.035 ;
        RECT 16.385 0.875 19.97 1 ;
        RECT 16.39 1.22 16.65 1.315 ;
        RECT 16.39 4.4 16.65 5.685 ;
        RECT 17.22 1.355 17.48 1.52 ;
        RECT 17.22 3.825 17.48 5.035 ;
        RECT 18.05 1.045 18.31 1.33 ;
        RECT 18.05 4.46 18.31 5.685 ;
        RECT 18.88 1.345 19.14 1.52 ;
        RECT 18.88 3.825 19.14 5.035 ;
        RECT 19.71 1.045 19.97 1.735 ;
        RECT 19.71 3.67 19.97 5.685 ;
  END
END sg13g2_hv_einvn_8

MACRO sg13g2_hv_fill_1
  CLASS CORE SPACER ;
  ORIGIN 0 0 ;
  FOREIGN sg13g2_hv_fill_1 0 0 ;
  SIZE 0.48 BY 7.14 ;
  SYMMETRY X Y ;
  SITE CoreSiteHV ;
  PIN VDD
    DIRECTION INOUT ;
    USE POWER ;
    SHAPE ABUTMENT ;
    NETEXPR "VDD VDD!" ;
    PORT
      LAYER Metal1 ;
        RECT 0 6.825 0.48 7.36 ;
    END
  END VDD
  PIN VSS
    DIRECTION INOUT ;
    USE GROUND ;
    SHAPE ABUTMENT ;
    NETEXPR "VSS VSS!" ;
    PORT
      LAYER Metal1 ;
        RECT 0 -0.22 0.48 0.22 ;
    END
  END VSS
END sg13g2_hv_fill_1

MACRO sg13g2_hv_fill_2
  CLASS CORE SPACER ;
  ORIGIN 0 0 ;
  FOREIGN sg13g2_hv_fill_2 0 0 ;
  SIZE 0.96 BY 7.14 ;
  SYMMETRY X Y ;
  SITE CoreSiteHV ;
  PIN VDD
    DIRECTION INOUT ;
    USE POWER ;
    SHAPE ABUTMENT ;
    NETEXPR "VDD VDD!" ;
    PORT
      LAYER Metal1 ;
        RECT 0 6.825 0.96 7.36 ;
    END
  END VDD
  PIN VSS
    DIRECTION INOUT ;
    USE GROUND ;
    SHAPE ABUTMENT ;
    NETEXPR "VSS VSS!" ;
    PORT
      LAYER Metal1 ;
        RECT 0 -0.22 0.96 0.22 ;
    END
  END VSS
END sg13g2_hv_fill_2

MACRO sg13g2_hv_fill_4
  CLASS CORE SPACER ;
  ORIGIN 0 0 ;
  FOREIGN sg13g2_hv_fill_4 0 0 ;
  SIZE 1.92 BY 7.14 ;
  SYMMETRY X Y ;
  SITE CoreSiteHV ;
  PIN VDD
    DIRECTION INOUT ;
    USE POWER ;
    SHAPE ABUTMENT ;
    NETEXPR "VDD VDD!" ;
    PORT
      LAYER Metal1 ;
        RECT 0 6.825 1.92 7.36 ;
    END
  END VDD
  PIN VSS
    DIRECTION INOUT ;
    USE GROUND ;
    SHAPE ABUTMENT ;
    NETEXPR "VSS VSS!" ;
    PORT
      LAYER Metal1 ;
        RECT 0 -0.22 1.92 0.22 ;
    END
  END VSS
END sg13g2_hv_fill_4

MACRO sg13g2_hv_fill_8
  CLASS CORE SPACER ;
  ORIGIN 0 0 ;
  FOREIGN sg13g2_hv_fill_8 0 0 ;
  SIZE 3.84 BY 7.14 ;
  SYMMETRY X Y ;
  SITE CoreSiteHV ;
  PIN VDD
    DIRECTION INOUT ;
    USE POWER ;
    SHAPE ABUTMENT ;
    NETEXPR "VDD VDD!" ;
    PORT
      LAYER Metal1 ;
        RECT 0 6.825 3.84 7.36 ;
    END
  END VDD
  PIN VSS
    DIRECTION INOUT ;
    USE GROUND ;
    SHAPE ABUTMENT ;
    NETEXPR "VSS VSS!" ;
    PORT
      LAYER Metal1 ;
        RECT 0 -0.22 3.84 0.22 ;
    END
  END VSS
END sg13g2_hv_fill_8

MACRO sg13g2_hv_inv_1
  CLASS CORE ;
  ORIGIN 0 0 ;
  FOREIGN sg13g2_hv_inv_1 0 0 ;
  SIZE 1.92 BY 7.14 ;
  SYMMETRY X Y ;
  SITE CoreSiteHV ;
  PIN VDD
    DIRECTION INOUT ;
    USE POWER ;
    SHAPE ABUTMENT ;
    NETEXPR "VDD VDD!" ;
    PORT
      LAYER Metal1 ;
        RECT 0 6.825 1.92 7.36 ;
    END
  END VDD
  PIN Y
    DIRECTION OUTPUT ;
    USE SIGNAL ;
    ANTENNADIFFAREA 1.1662 LAYER Metal1 ;
    PORT
      LAYER Metal1 ;
        RECT 1.175 1.04 1.405 5.9 ;
        RECT 1.405 1.04 1.44 5.9 ;
    END
  END Y
  PIN A
    DIRECTION INPUT ;
    USE SIGNAL ;
    ANTENNAMODEL OXIDE1 ;
      ANTENNAGATEAREA 1.5435 LAYER Metal1 ;
    PORT
      LAYER Metal1 ;
        RECT 0.31 1.95 0.625 2.725 ;
    END
  END A
  PIN VSS
    DIRECTION INOUT ;
    USE GROUND ;
    SHAPE ABUTMENT ;
    NETEXPR "VSS VSS!" ;
    PORT
      LAYER Metal1 ;
        RECT 0 -0.22 1.92 0.22 ;
    END
  END VSS
  OBS
      LAYER Metal1 ;
        RECT 0.33 0.22 0.59 1.64 ;
        RECT 0.33 3.645 0.59 6.825 ;
  END
END sg13g2_hv_inv_1

MACRO sg13g2_hv_inv_16
  CLASS CORE ;
  ORIGIN 0 0 ;
  FOREIGN sg13g2_hv_inv_16 0 0 ;
  SIZE 14.4 BY 7.14 ;
  SYMMETRY X Y ;
  SITE CoreSiteHV ;
  PIN A
    DIRECTION INPUT ;
    USE SIGNAL ;
    ANTENNAMODEL OXIDE1 ;
      ANTENNAGATEAREA 24.6960 LAYER Metal1 ;
    PORT
      LAYER Metal1 ;
        RECT 12.825 1.92 13.865 2.745 ;
    END
  END A
  PIN Y
    DIRECTION OUTPUT ;
    USE SIGNAL ;
    ANTENNADIFFAREA 10.4272 LAYER Metal1 ;
    PORT
      LAYER Metal1 ;
        RECT 1.415 2.825 4.735 3.85 ;
    END
  END Y
  PIN VDD
    DIRECTION INOUT ;
    USE POWER ;
    SHAPE ABUTMENT ;
    NETEXPR "VDD VDD!" ;
    PORT
      LAYER Metal1 ;
        RECT 0 6.825 14.4 7.36 ;
    END
  END VDD
  PIN VSS
    DIRECTION INOUT ;
    USE GROUND ;
    SHAPE ABUTMENT ;
    NETEXPR "VSS VSS!" ;
    PORT
      LAYER Metal1 ;
        RECT 0 -0.22 14.4 0.22 ;
    END
  END VSS
  OBS
      LAYER Metal1 ;
        RECT 0.325 0.22 0.585 1.64 ;
        RECT 0.325 3.61 0.585 6.825 ;
        RECT 1.155 1.06 1.415 5.865 ;
        RECT 1.985 0.22 2.245 1.64 ;
        RECT 1.985 4.425 2.245 6.825 ;
        RECT 2.815 1.06 3.075 2.825 ;
        RECT 2.815 3.85 3.075 5.865 ;
        RECT 3.645 0.22 3.905 1.64 ;
        RECT 3.645 4.425 3.905 6.825 ;
        RECT 4.475 1.055 4.735 2.825 ;
        RECT 4.475 3.85 4.735 5.865 ;
        RECT 4.735 2.825 11.375 3.43 ;
        RECT 4.735 3.43 13.035 3.85 ;
        RECT 5.305 0.22 5.565 1.64 ;
        RECT 5.305 4.425 5.565 6.825 ;
        RECT 6.135 1.055 6.395 2.825 ;
        RECT 6.135 3.85 6.395 5.865 ;
        RECT 6.965 0.22 7.225 1.64 ;
        RECT 6.965 4.425 7.225 6.825 ;
        RECT 7.795 1.055 8.055 2.825 ;
        RECT 7.795 3.85 8.055 5.865 ;
        RECT 8.625 0.22 8.885 1.64 ;
        RECT 8.625 4.425 8.885 6.825 ;
        RECT 9.455 1.055 9.715 2.825 ;
        RECT 9.455 3.85 9.715 5.865 ;
        RECT 10.285 0.22 10.545 1.64 ;
        RECT 10.285 4.425 10.545 6.825 ;
        RECT 11.115 1.055 11.375 1.48 ;
        RECT 11.115 1.48 13.035 1.64 ;
        RECT 11.115 1.64 11.375 2.825 ;
        RECT 11.115 3.85 11.375 5.865 ;
        RECT 11.945 0.22 12.205 1.3 ;
        RECT 11.945 4.425 12.205 6.81 ;
        RECT 11.945 6.81 13.915 6.825 ;
        RECT 12.775 1.055 13.035 1.48 ;
        RECT 12.775 3.85 13.035 5.865 ;
        RECT 13.605 0.22 13.865 1.64 ;
        RECT 13.655 3.61 13.915 6.81 ;
        RECT 13.865 1.92 13.905 2.745 ;
  END
END sg13g2_hv_inv_16

MACRO sg13g2_hv_inv_2
  CLASS CORE ;
  ORIGIN 0 0 ;
  FOREIGN sg13g2_hv_inv_2 0 0 ;
  SIZE 2.88 BY 7.14 ;
  SYMMETRY X Y ;
  SITE CoreSiteHV ;
  PIN Y
    DIRECTION OUTPUT ;
    USE SIGNAL ;
    ANTENNADIFFAREA 1.3034 LAYER Metal1 ;
    PORT
      LAYER Metal1 ;
        RECT 1.19 1.95 2.23 2.725 ;
    END
  END Y
  PIN A
    DIRECTION INPUT ;
    USE SIGNAL ;
    ANTENNAMODEL OXIDE1 ;
      ANTENNAGATEAREA 3.0870 LAYER Metal1 ;
    PORT
      LAYER Metal1 ;
        RECT 0.255 1.95 0.71 2.725 ;
    END
  END A
  PIN VDD
    DIRECTION INOUT ;
    USE POWER ;
    SHAPE ABUTMENT ;
    NETEXPR "VDD VDD!" ;
    PORT
      LAYER Metal1 ;
        RECT 0 6.825 2.88 7.36 ;
    END
  END VDD
  PIN VSS
    DIRECTION INOUT ;
    USE GROUND ;
    SHAPE ABUTMENT ;
    NETEXPR "VSS VSS!" ;
    PORT
      LAYER Metal1 ;
        RECT 0 -0.22 2.88 0.22 ;
    END
  END VSS
  OBS
      LAYER Metal1 ;
        RECT 0.285 0.22 0.545 1.64 ;
        RECT 0.285 3.61 0.545 6.825 ;
        RECT 1.115 1.04 1.375 1.64 ;
        RECT 1.115 3.61 1.375 5.91 ;
        RECT 1.19 1.64 1.375 1.95 ;
        RECT 1.19 2.725 1.375 3.61 ;
        RECT 1.945 0.22 2.205 1.64 ;
        RECT 1.95 3.61 2.21 6.825 ;
  END
END sg13g2_hv_inv_2

MACRO sg13g2_hv_inv_4
  CLASS CORE ;
  ORIGIN 0 0 ;
  FOREIGN sg13g2_hv_inv_4 0 0 ;
  SIZE 4.32 BY 7.14 ;
  SYMMETRY X Y ;
  SITE CoreSiteHV ;
  PIN A
    DIRECTION INPUT ;
    USE SIGNAL ;
    ANTENNAMODEL OXIDE1 ;
      ANTENNAGATEAREA 6.1740 LAYER Metal1 ;
    PORT
      LAYER Metal1 ;
        RECT 0.48 1.95 2.96 2.825 ;
    END
  END A
  PIN Y
    DIRECTION OUTPUT ;
    USE SIGNAL ;
    ANTENNADIFFAREA 2.6068 LAYER Metal1 ;
    PORT
      LAYER Metal1 ;
        RECT 3.525 1.48 3.82 3.895 ;
        RECT 3.82 1.48 3.84 3.895 ;
    END
  END Y
  PIN VDD
    DIRECTION INOUT ;
    USE POWER ;
    SHAPE ABUTMENT ;
    NETEXPR "VDD VDD!" ;
    PORT
      LAYER Metal1 ;
        RECT 0 6.825 4.32 7.36 ;
    END
  END VDD
  PIN VSS
    DIRECTION INOUT ;
    USE GROUND ;
    SHAPE ABUTMENT ;
    NETEXPR "VSS VSS!" ;
    PORT
      LAYER Metal1 ;
        RECT 0 -0.22 4.32 0.22 ;
    END
  END VSS
  OBS
      LAYER Metal1 ;
        RECT 0.265 0.22 0.525 1.64 ;
        RECT 0.265 3.57 0.525 6.825 ;
        RECT 1.095 1.04 1.355 1.48 ;
        RECT 1.095 1.48 3.525 1.64 ;
        RECT 1.095 3.49 3.525 3.895 ;
        RECT 1.095 3.895 1.355 5.85 ;
        RECT 1.92 0.22 2.19 1.3 ;
        RECT 1.925 4.39 2.185 6.825 ;
        RECT 2.755 1.04 3.015 1.48 ;
        RECT 2.755 3.895 3.015 5.85 ;
        RECT 3.585 0.22 3.845 1.3 ;
        RECT 3.585 4.39 3.845 6.825 ;
  END
END sg13g2_hv_inv_4

MACRO sg13g2_hv_inv_8
  CLASS CORE ;
  ORIGIN 0 0 ;
  FOREIGN sg13g2_hv_inv_8 0 0 ;
  SIZE 7.68 BY 7.14 ;
  SYMMETRY X Y ;
  SITE CoreSiteHV ;
  PIN Y
    DIRECTION OUTPUT ;
    USE SIGNAL ;
    ANTENNADIFFAREA 5.2136 LAYER Metal1 ;
    PORT
      LAYER Metal1 ;
        RECT 4.34 1.96 6.275 2.715 ;
    END
  END Y
  PIN A
    DIRECTION INPUT ;
    USE SIGNAL ;
    ANTENNAMODEL OXIDE1 ;
      ANTENNAGATEAREA 12.3480 LAYER Metal1 ;
    PORT
      LAYER Metal1 ;
        RECT 1.125 2.225 3.775 2.74 ;
    END
  END A
  PIN VDD
    DIRECTION INOUT ;
    USE POWER ;
    SHAPE ABUTMENT ;
    NETEXPR "VDD VDD!" ;
    PORT
      LAYER Metal1 ;
        RECT 0 6.825 7.68 7.36 ;
    END
  END VDD
  PIN VSS
    DIRECTION INOUT ;
    USE GROUND ;
    SHAPE ABUTMENT ;
    NETEXPR "VSS VSS!" ;
    PORT
      LAYER Metal1 ;
        RECT 0 -0.22 7.68 0.22 ;
    END
  END VSS
  OBS
      LAYER Metal1 ;
        RECT 0.205 0.22 0.465 1.64 ;
        RECT 0.205 3.61 0.465 6.825 ;
        RECT 1.035 1.05 1.3 1.48 ;
        RECT 1.035 1.48 2.96 1.5 ;
        RECT 1.035 1.5 4.615 1.66 ;
        RECT 1.035 3.61 4.615 3.99 ;
        RECT 1.035 3.99 1.295 5.865 ;
        RECT 1.125 1.965 3.775 2.225 ;
        RECT 1.865 0.22 2.125 1.3 ;
        RECT 1.865 4.425 2.125 6.825 ;
        RECT 2.695 1.04 2.96 1.48 ;
        RECT 2.695 3.99 2.955 5.865 ;
        RECT 3.525 0.22 3.785 1.32 ;
        RECT 3.525 4.425 3.785 6.825 ;
        RECT 4.34 1.66 4.615 1.96 ;
        RECT 4.34 2.715 4.615 3.61 ;
        RECT 4.355 1.04 4.615 1.5 ;
        RECT 4.355 3.99 4.615 5.865 ;
        RECT 5.185 0.22 5.445 1.64 ;
        RECT 5.185 3.61 5.445 6.825 ;
        RECT 6.015 1.04 6.275 1.96 ;
        RECT 6.015 2.715 6.275 5.865 ;
        RECT 6.855 0.22 7.115 1.64 ;
        RECT 6.855 3.61 7.115 6.825 ;
  END
END sg13g2_hv_inv_8

MACRO sg13g2_hv_lgcp_1
  CLASS CORE ;
  ORIGIN 0 0 ;
  FOREIGN sg13g2_hv_lgcp_1 0 0 ;
  SIZE 14.88 BY 7.14 ;
  SYMMETRY X Y ;
  SITE CoreSiteHV ;
  PIN GATE
    DIRECTION INPUT ;
    USE SIGNAL ;
    ANTENNAMODEL OXIDE1 ;
      ANTENNAGATEAREA 1.3680 LAYER Metal1 ;
    PORT
      LAYER Metal1 ;
        RECT 0.66 2.985 1.685 3.655 ;
    END
  END GATE
  PIN CLK
    DIRECTION INPUT ;
    USE SIGNAL ;
    ANTENNAMODEL OXIDE1 ;
      ANTENNAGATEAREA 2.4345 LAYER Metal1 ;
    PORT
      LAYER Metal1 ;
        RECT 9.41 2.125 10.29 3.08 ;
    END
  END CLK
  PIN GCLK
    DIRECTION OUTPUT ;
    USE SIGNAL ;
    ANTENNADIFFAREA 1.1662 LAYER Metal1 ;
    PORT
      LAYER Metal1 ;
        RECT 13.81 3.225 14.39 5.91 ;
    END
  END GCLK
  PIN VDD
    DIRECTION INOUT ;
    USE POWER ;
    SHAPE ABUTMENT ;
    NETEXPR "VDD VDD!" ;
    PORT
      LAYER Metal1 ;
        RECT 0 6.825 14.88 7.36 ;
    END
  END VDD
  PIN VSS
    DIRECTION INOUT ;
    USE GROUND ;
    SHAPE ABUTMENT ;
    NETEXPR "VSS VSS!" ;
    PORT
      LAYER Metal1 ;
        RECT 0 -0.22 14.88 0.22 ;
        RECT -0.48 -0.22 14.88 0.22 ;
    END
  END VSS
  OBS
      LAYER Metal1 ;
        RECT 0.58 1.185 3.36 1.35 ;
        RECT 0.58 1.35 1.175 1.61 ;
        RECT 0.58 4.4 0.84 6.825 ;
        RECT 0.81 1.61 1.175 1.95 ;
        RECT 0.81 1.95 2.35 2.555 ;
        RECT 1.02 2.78 1.515 2.985 ;
        RECT 1.41 4.425 2.35 4.51 ;
        RECT 1.41 4.51 4.26 4.905 ;
        RECT 1.41 4.905 1.67 5.815 ;
        RECT 1.44 0.22 1.7 1.005 ;
        RECT 2.3 1.53 2.825 1.77 ;
        RECT 2.3 5.335 2.56 6.825 ;
        RECT 2.53 1.77 2.825 2.64 ;
        RECT 2.53 2.64 4.245 2.925 ;
        RECT 3.135 2.925 3.435 3.97 ;
        RECT 3.14 1.085 3.36 1.185 ;
        RECT 3.2 1.68 4.02 1.85 ;
        RECT 3.2 1.85 3.445 1.975 ;
        RECT 3.54 0.88 5.93 1.04 ;
        RECT 3.54 1.04 4.02 1.68 ;
        RECT 3.87 2.515 4.245 2.64 ;
        RECT 4 3.5 4.26 4.51 ;
        RECT 4 4.905 4.26 5.325 ;
        RECT 4.2 1.22 4.86 1.42 ;
        RECT 4.315 1.42 4.86 1.745 ;
        RECT 4.315 1.745 5.125 1.9 ;
        RECT 4.685 1.9 5.125 1.93 ;
        RECT 4.685 1.93 7.61 2.595 ;
        RECT 4.685 2.595 5.58 2.925 ;
        RECT 4.905 2.925 5.58 5.325 ;
        RECT 5.58 1.04 5.93 1.535 ;
        RECT 5.58 1.535 7.295 1.695 ;
        RECT 6.18 3.19 8.59 3.81 ;
        RECT 6.3 0.22 6.63 1.34 ;
        RECT 6.94 4.965 7.465 6.825 ;
        RECT 6.995 0.905 8.975 1.075 ;
        RECT 6.995 1.075 7.295 1.535 ;
        RECT 8.06 1.34 8.475 1.6 ;
        RECT 8.3 1.6 8.475 3.08 ;
        RECT 8.3 3.08 8.59 3.19 ;
        RECT 8.33 3.81 8.59 5.155 ;
        RECT 8.33 5.155 10.97 5.54 ;
        RECT 8.33 5.54 8.59 5.635 ;
        RECT 8.69 1.075 8.975 1.74 ;
        RECT 8.785 1.74 8.945 3.69 ;
        RECT 8.785 3.69 9.32 4.315 ;
        RECT 9.69 0.22 10.33 1.705 ;
        RECT 10.495 4.16 11.18 4.65 ;
        RECT 10.495 4.65 10.97 5.155 ;
        RECT 10.775 1.89 11.905 2.635 ;
        RECT 10.775 2.635 11.18 4.16 ;
        RECT 11.8 2.935 12.565 3.345 ;
        RECT 11.8 3.345 11.995 5.66 ;
        RECT 11.83 1.14 12.575 1.7 ;
        RECT 12.085 1.7 12.575 1.95 ;
        RECT 12.085 1.95 14 2.725 ;
        RECT 12.085 2.725 12.565 2.935 ;
        RECT 12.6 3.885 12.86 6.825 ;
        RECT 12.755 0.22 12.985 1.65 ;
        RECT 14.13 1.05 14.39 1.73 ;
        RECT 14.23 1.73 14.39 3.225 ;
  END
END sg13g2_hv_lgcp_1

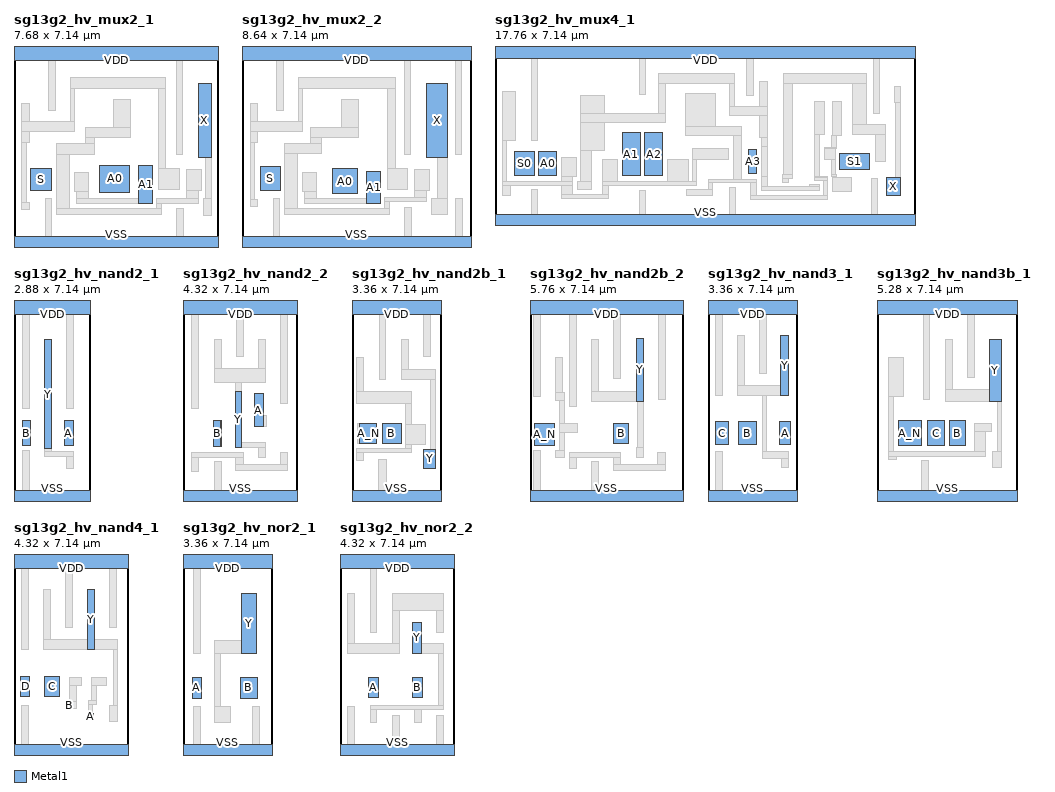
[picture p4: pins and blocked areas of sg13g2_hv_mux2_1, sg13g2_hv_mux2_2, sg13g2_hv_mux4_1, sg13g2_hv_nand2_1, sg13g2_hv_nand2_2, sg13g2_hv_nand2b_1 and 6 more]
MACRO sg13g2_hv_mux2_1
  CLASS CORE ;
  ORIGIN 0 0 ;
  FOREIGN sg13g2_hv_mux2_1 0 0 ;
  SIZE 7.68 BY 7.14 ;
  SYMMETRY X Y ;
  SITE CoreSiteHV ;
  PIN A0
    DIRECTION INPUT ;
    USE SIGNAL ;
    ANTENNAMODEL OXIDE1 ;
      ANTENNAGATEAREA 1.4130 LAYER Metal1 ;
    PORT
      LAYER Metal1 ;
        RECT 3.225 1.85 4.345 2.885 ;
    END
  END A0
  PIN A1
    DIRECTION INPUT ;
    USE SIGNAL ;
    ANTENNAMODEL OXIDE1 ;
      ANTENNAGATEAREA 1.4130 LAYER Metal1 ;
    PORT
      LAYER Metal1 ;
        RECT 4.695 1.46 5.19 2.885 ;
    END
  END A1
  PIN S
    DIRECTION INPUT ;
    USE SIGNAL ;
    ANTENNAMODEL OXIDE1 ;
      ANTENNAGATEAREA 2.5673 LAYER Metal1 ;
    PORT
      LAYER Metal1 ;
        RECT 0.635 1.93 1.425 2.745 ;
    END
  END S
  PIN X
    DIRECTION OUTPUT ;
    USE SIGNAL ;
    ANTENNADIFFAREA 1.1662 LAYER Metal1 ;
    PORT
      LAYER Metal1 ;
        RECT 6.95 3.175 7.405 5.96 ;
    END
  END X
  PIN VDD
    DIRECTION INOUT ;
    USE POWER ;
    SHAPE ABUTMENT ;
    NETEXPR "VDD VDD!" ;
    PORT
      LAYER Metal1 ;
        RECT 0 6.825 7.68 7.36 ;
    END
  END VDD
  PIN VSS
    DIRECTION INOUT ;
    USE GROUND ;
    SHAPE ABUTMENT ;
    NETEXPR "VSS VSS!" ;
    PORT
      LAYER Metal1 ;
        RECT 0 -0.22 7.68 0.22 ;
    END
  END VSS
  OBS
      LAYER Metal1 ;
        RECT 0.295 1.23 0.575 1.49 ;
        RECT 0.295 1.49 0.455 3.75 ;
        RECT 0.295 3.75 0.575 4.135 ;
        RECT 0.295 4.135 2.28 4.52 ;
        RECT 0.295 4.52 0.575 5.19 ;
        RECT 1.175 0.22 1.41 1.64 ;
        RECT 1.295 4.95 1.555 6.825 ;
        RECT 1.605 1.04 5.54 1.26 ;
        RECT 1.605 1.26 2.09 3.27 ;
        RECT 1.605 3.27 3.015 3.705 ;
        RECT 2.12 4.52 2.28 5.78 ;
        RECT 2.12 5.78 5.685 6.19 ;
        RECT 2.27 1.9 2.8 2.605 ;
        RECT 2.35 1.46 4.695 1.63 ;
        RECT 2.35 1.63 2.8 1.9 ;
        RECT 2.68 3.705 3.015 3.91 ;
        RECT 2.68 3.91 4.38 4.29 ;
        RECT 3.725 4.29 4.38 5.35 ;
        RECT 5.37 1.26 5.54 1.46 ;
        RECT 5.37 1.46 6.95 1.63 ;
        RECT 5.425 1.97 6.215 2.745 ;
        RECT 5.425 2.745 5.685 5.78 ;
        RECT 6.095 0.22 6.355 1.275 ;
        RECT 6.125 3.27 6.325 6.825 ;
        RECT 6.5 1.63 6.95 1.95 ;
        RECT 6.5 1.95 7.035 2.725 ;
        RECT 7.13 1 7.405 1.64 ;
        RECT 7.215 1.64 7.405 3.175 ;
  END
END sg13g2_hv_mux2_1

MACRO sg13g2_hv_mux2_2
  CLASS CORE ;
  ORIGIN 0 0 ;
  FOREIGN sg13g2_hv_mux2_2 0 0 ;
  SIZE 8.64 BY 7.14 ;
  SYMMETRY X Y ;
  SITE CoreSiteHV ;
  PIN A0
    DIRECTION INPUT ;
    USE SIGNAL ;
    ANTENNAMODEL OXIDE1 ;
      ANTENNAGATEAREA 1.4130 LAYER Metal1 ;
    PORT
      LAYER Metal1 ;
        RECT 3.415 1.83 4.345 2.75 ;
    END
  END A0
  PIN A1
    DIRECTION INPUT ;
    USE SIGNAL ;
    ANTENNAMODEL OXIDE1 ;
      ANTENNAGATEAREA 1.4130 LAYER Metal1 ;
    PORT
      LAYER Metal1 ;
        RECT 4.695 1.46 5.19 2.66 ;
    END
  END A1
  PIN S
    DIRECTION INPUT ;
    USE SIGNAL ;
    ANTENNAMODEL OXIDE1 ;
      ANTENNAGATEAREA 2.5673 LAYER Metal1 ;
    PORT
      LAYER Metal1 ;
        RECT 0.685 1.93 1.43 2.84 ;
    END
  END S
  PIN X
    DIRECTION OUTPUT ;
    USE SIGNAL ;
    ANTENNADIFFAREA 1.3034 LAYER Metal1 ;
    PORT
      LAYER Metal1 ;
        RECT 6.95 3.175 7.71 5.96 ;
    END
  END X
  PIN VDD
    DIRECTION INOUT ;
    USE POWER ;
    SHAPE ABUTMENT ;
    NETEXPR "VDD VDD!" ;
    PORT
      LAYER Metal1 ;
        RECT 0 6.825 8.64 7.36 ;
    END
  END VDD
  PIN VSS
    DIRECTION INOUT ;
    USE GROUND ;
    SHAPE ABUTMENT ;
    NETEXPR "VSS VSS!" ;
    PORT
      LAYER Metal1 ;
        RECT 0 -0.22 8.64 0.22 ;
    END
  END VSS
  OBS
      LAYER Metal1 ;
        RECT 0.31 1.35 0.575 1.61 ;
        RECT 0.31 1.61 0.47 3.75 ;
        RECT 0.31 3.75 0.575 4.135 ;
        RECT 0.31 4.135 2.28 4.52 ;
        RECT 0.31 4.52 0.575 5.19 ;
        RECT 1.175 0.22 1.41 1.64 ;
        RECT 1.295 4.95 1.555 6.825 ;
        RECT 1.61 1.04 5.54 1.26 ;
        RECT 1.61 1.26 2.09 3.32 ;
        RECT 1.61 3.32 2.975 3.705 ;
        RECT 2.12 4.52 2.28 5.78 ;
        RECT 2.12 5.78 5.775 6.19 ;
        RECT 2.27 1.9 2.8 2.605 ;
        RECT 2.35 1.46 4.695 1.63 ;
        RECT 2.35 1.63 2.8 1.9 ;
        RECT 2.575 3.705 2.975 3.91 ;
        RECT 2.575 3.91 4.38 4.29 ;
        RECT 3.725 4.29 4.38 5.35 ;
        RECT 5.37 1.26 5.54 1.53 ;
        RECT 5.37 1.53 6.95 1.69 ;
        RECT 5.465 1.97 6.215 2.745 ;
        RECT 5.465 2.745 5.775 5.78 ;
        RECT 6.095 0.22 6.355 1.3 ;
        RECT 6.125 3.27 6.325 6.825 ;
        RECT 6.5 1.69 6.95 1.95 ;
        RECT 6.5 1.95 7.06 2.725 ;
        RECT 7.13 1.04 7.71 1.64 ;
        RECT 7.33 1.64 7.71 3.175 ;
        RECT 8.01 0.22 8.27 1.64 ;
        RECT 8.04 3.27 8.24 6.825 ;
  END
END sg13g2_hv_mux2_2

MACRO sg13g2_hv_mux4_1
  CLASS CORE ;
  ORIGIN 0 0 ;
  FOREIGN sg13g2_hv_mux4_1 0 0 ;
  SIZE 17.76 BY 7.14 ;
  SYMMETRY X Y ;
  SITE CoreSiteHV ;
  PIN S0
    DIRECTION INPUT ;
    USE SIGNAL ;
    ANTENNAMODEL OXIDE1 ;
      ANTENNAGATEAREA 4.1040 LAYER Metal1 ;
    PORT
      LAYER Metal1 ;
        RECT 0.835 1.865 1.66 2.885 ;
    END
  END S0
  PIN A0
    DIRECTION INPUT ;
    USE SIGNAL ;
    ANTENNAMODEL OXIDE1 ;
      ANTENNAGATEAREA 1.3680 LAYER Metal1 ;
    PORT
      LAYER Metal1 ;
        RECT 1.84 1.865 2.615 2.885 ;
    END
  END A0
  PIN A1
    DIRECTION INPUT ;
    USE SIGNAL ;
    ANTENNAMODEL OXIDE1 ;
      ANTENNAGATEAREA 1.3680 LAYER Metal1 ;
    PORT
      LAYER Metal1 ;
        RECT 5.395 1.865 6.145 3.69 ;
    END
  END A1
  PIN A2
    DIRECTION INPUT ;
    USE SIGNAL ;
    ANTENNAMODEL OXIDE1 ;
      ANTENNAGATEAREA 1.3680 LAYER Metal1 ;
    PORT
      LAYER Metal1 ;
        RECT 6.325 1.865 7.08 3.69 ;
    END
  END A2
  PIN A3
    DIRECTION INPUT ;
    USE SIGNAL ;
    ANTENNAMODEL OXIDE1 ;
      ANTENNAGATEAREA 1.3680 LAYER Metal1 ;
    PORT
      LAYER Metal1 ;
        RECT 10.74 1.96 11.07 2.985 ;
    END
  END A3
  PIN S1
    DIRECTION INPUT ;
    USE SIGNAL ;
    ANTENNAMODEL OXIDE1 ;
      ANTENNAGATEAREA 2.7360 LAYER Metal1 ;
    PORT
      LAYER Metal1 ;
        RECT 14.585 2.125 15.845 2.81 ;
    END
  END S1
  PIN X
    DIRECTION OUTPUT ;
    USE SIGNAL ;
    ANTENNADIFFAREA 1.1662 LAYER Metal1 ;
    PORT
      LAYER Metal1 ;
        RECT 16.56 1.05 17.165 1.79 ;
    END
  END X
  PIN VDD
    DIRECTION INOUT ;
    USE POWER ;
    SHAPE ABUTMENT ;
    NETEXPR "VDD VDD!" ;
    PORT
      LAYER Metal1 ;
        RECT 0 6.825 17.76 7.36 ;
    END
  END VDD
  PIN VSS
    DIRECTION INOUT ;
    USE GROUND ;
    SHAPE ABUTMENT ;
    NETEXPR "VSS VSS!" ;
    PORT
      LAYER Metal1 ;
        RECT 0 -0.22 17.76 0.22 ;
    END
  END VSS
  OBS
      LAYER Metal1 ;
        RECT 0.33 1.02 0.64 1.45 ;
        RECT 0.33 1.45 3.29 1.63 ;
        RECT 0.33 1.63 0.5 3.37 ;
        RECT 0.33 3.37 0.87 5.445 ;
        RECT 1.55 0.22 1.81 1.27 ;
        RECT 1.55 3.37 1.81 6.825 ;
        RECT 2.805 0.905 4.79 1.075 ;
        RECT 2.805 1.075 3.29 1.45 ;
        RECT 2.805 1.63 3.29 1.85 ;
        RECT 2.805 1.85 3.455 2.625 ;
        RECT 3.47 1.3 4.08 1.63 ;
        RECT 3.635 1.63 4.08 2.96 ;
        RECT 3.635 2.96 4.625 4.125 ;
        RECT 3.635 4.125 7.23 4.51 ;
        RECT 3.635 4.51 4.625 5.25 ;
        RECT 4.535 1.075 4.79 1.48 ;
        RECT 4.535 1.48 8.525 1.64 ;
        RECT 4.535 1.64 5.185 2.545 ;
        RECT 6.1 0.22 6.375 1.265 ;
        RECT 6.125 5.29 6.385 6.825 ;
        RECT 6.915 4.51 7.23 5.78 ;
        RECT 6.915 5.78 10.12 6.19 ;
        RECT 7.29 1.64 8.165 2.545 ;
        RECT 8.065 3.56 10.41 3.97 ;
        RECT 8.065 3.97 9.345 5.35 ;
        RECT 8.105 1.025 9.205 1.3 ;
        RECT 8.355 1.64 8.525 2.54 ;
        RECT 8.355 2.54 9.865 3.01 ;
        RECT 9.025 1.3 9.205 1.57 ;
        RECT 9.025 1.57 11.045 1.73 ;
        RECT 9.895 0.22 10.155 1.39 ;
        RECT 9.92 4.41 11.515 4.82 ;
        RECT 9.92 4.82 10.12 5.78 ;
        RECT 10.065 1.73 10.41 3.56 ;
        RECT 10.62 5.25 10.95 6.825 ;
        RECT 10.785 0.87 14.07 1.03 ;
        RECT 10.785 1.03 11.045 1.57 ;
        RECT 11.18 3.49 11.515 4.41 ;
        RECT 11.18 4.82 11.515 5.865 ;
        RECT 11.25 1.25 13.73 1.41 ;
        RECT 11.25 1.41 11.515 1.83 ;
        RECT 11.25 3.115 11.515 3.49 ;
        RECT 11.29 1.83 11.515 3.115 ;
        RECT 12.155 1.59 12.4 1.765 ;
        RECT 12.155 1.765 12.575 1.935 ;
        RECT 12.2 1.935 12.575 5.78 ;
        RECT 12.2 5.78 15.69 6.19 ;
        RECT 13.295 1.41 13.73 1.51 ;
        RECT 13.5 1.69 14.07 1.78 ;
        RECT 13.5 1.78 14.045 1.85 ;
        RECT 13.5 1.85 13.735 3.61 ;
        RECT 13.5 3.61 13.925 5.025 ;
        RECT 13.91 1.03 14.07 1.69 ;
        RECT 13.915 2.54 14.405 3.01 ;
        RECT 13.915 3.01 14.42 3.07 ;
        RECT 14.235 3.07 14.42 3.56 ;
        RECT 14.245 1.83 14.42 1.915 ;
        RECT 14.245 1.915 14.405 2.54 ;
        RECT 14.26 1.19 15.09 1.79 ;
        RECT 14.26 1.79 14.42 1.83 ;
        RECT 14.26 3.56 14.42 3.57 ;
        RECT 14.26 3.57 14.635 5.025 ;
        RECT 15.11 3.63 16.51 4.04 ;
        RECT 15.11 4.04 15.69 5.78 ;
        RECT 15.925 0.22 16.185 1.755 ;
        RECT 15.985 4.485 16.245 6.825 ;
        RECT 16.09 2.48 16.51 3.63 ;
        RECT 16.9 4.95 17.165 5.66 ;
        RECT 16.925 1.79 17.165 4.95 ;
  END
END sg13g2_hv_mux4_1

MACRO sg13g2_hv_nand2_1
  CLASS CORE ;
  ORIGIN 0 0 ;
  FOREIGN sg13g2_hv_nand2_1 0 0 ;
  SIZE 2.88 BY 7.14 ;
  SYMMETRY X Y ;
  SITE CoreSiteHV ;
  PIN Y
    DIRECTION OUTPUT ;
    USE SIGNAL ;
    ANTENNADIFFAREA 2.0808 LAYER Metal1 ;
    PORT
      LAYER Metal1 ;
        RECT 1.15 1.795 1.41 5.865 ;
    END
  END Y
  PIN A
    DIRECTION INPUT ;
    USE SIGNAL ;
    ANTENNAMODEL OXIDE1 ;
      ANTENNAGATEAREA 1.5435 LAYER Metal1 ;
    PORT
      LAYER Metal1 ;
        RECT 1.885 1.9 2.24 2.825 ;
    END
  END A
  PIN B
    DIRECTION INPUT ;
    USE SIGNAL ;
    ANTENNAMODEL OXIDE1 ;
      ANTENNAGATEAREA 1.5435 LAYER Metal1 ;
    PORT
      LAYER Metal1 ;
        RECT 0.33 1.9 0.62 2.825 ;
    END
  END B
  PIN VDD
    DIRECTION INOUT ;
    USE POWER ;
    SHAPE ABUTMENT ;
    NETEXPR "VDD VDD!" ;
    PORT
      LAYER Metal1 ;
        RECT 0 6.825 2.88 7.36 ;
    END
  END VDD
  PIN VSS
    DIRECTION INOUT ;
    USE GROUND ;
    SHAPE ABUTMENT ;
    NETEXPR "VSS VSS!" ;
    PORT
      LAYER Metal1 ;
        RECT 0 -0.22 2.88 0.22 ;
    END
  END VSS
  OBS
      LAYER Metal1 ;
        RECT 0.32 0.22 0.58 1.705 ;
        RECT 0.32 3.27 0.58 6.825 ;
        RECT 1.15 1.49 2.24 1.675 ;
        RECT 1.15 1.675 1.41 1.795 ;
        RECT 1.98 1.05 2.24 1.49 ;
        RECT 1.98 3.27 2.24 6.825 ;
  END
END sg13g2_hv_nand2_1

MACRO sg13g2_hv_nand2_2
  CLASS CORE ;
  ORIGIN 0 0 ;
  FOREIGN sg13g2_hv_nand2_2 0 0 ;
  SIZE 4.32 BY 7.14 ;
  SYMMETRY X Y ;
  SITE CoreSiteHV ;
  PIN Y
    DIRECTION OUTPUT ;
    USE SIGNAL ;
    ANTENNADIFFAREA 2.3180 LAYER Metal1 ;
    PORT
      LAYER Metal1 ;
        RECT 1.96 1.82 2.2 3.945 ;
    END
  END Y
  PIN A
    DIRECTION INPUT ;
    USE SIGNAL ;
    ANTENNAMODEL OXIDE1 ;
      ANTENNAGATEAREA 3.0690 LAYER Metal1 ;
    PORT
      LAYER Metal1 ;
        RECT 2.675 2.605 3.01 3.85 ;
    END
  END A
  PIN B
    DIRECTION INPUT ;
    USE SIGNAL ;
    ANTENNAMODEL OXIDE1 ;
      ANTENNAGATEAREA 3.0690 LAYER Metal1 ;
    PORT
      LAYER Metal1 ;
        RECT 1.14 1.865 1.42 2.825 ;
        RECT 1.42 1.865 1.44 2.825 ;
    END
  END B
  PIN VDD
    DIRECTION INOUT ;
    USE POWER ;
    SHAPE ABUTMENT ;
    NETEXPR "VDD VDD!" ;
    PORT
      LAYER Metal1 ;
        RECT 0 6.825 4.32 7.36 ;
    END
  END VDD
  PIN VSS
    DIRECTION INOUT ;
    USE GROUND ;
    SHAPE ABUTMENT ;
    NETEXPR "VSS VSS!" ;
    PORT
      LAYER Metal1 ;
        RECT 0 -0.22 4.32 0.22 ;
    END
  END VSS
  OBS
      LAYER Metal1 ;
        RECT 0.32 3.27 0.58 6.825 ;
        RECT 0.325 0.93 0.585 1.465 ;
        RECT 0.325 1.465 2.26 1.63 ;
        RECT 1.17 0.22 1.43 1.285 ;
        RECT 1.17 4.28 3.1 4.81 ;
        RECT 1.17 4.81 1.43 5.865 ;
        RECT 1.96 3.945 2.2 4.28 ;
        RECT 1.99 0.96 3.93 1.19 ;
        RECT 1.99 1.19 2.26 1.465 ;
        RECT 2 5.24 2.26 6.825 ;
        RECT 2.2 1.82 3.1 2.025 ;
        RECT 2.84 1.43 3.1 1.82 ;
        RECT 2.84 4.81 3.1 5.865 ;
        RECT 3.01 2.605 3.13 3.03 ;
        RECT 3.65 1.19 3.93 1.63 ;
        RECT 3.67 3.465 3.93 6.825 ;
  END
END sg13g2_hv_nand2_2

MACRO sg13g2_hv_nand2b_1
  CLASS CORE ;
  ORIGIN 0 0 ;
  FOREIGN sg13g2_hv_nand2b_1 0 0 ;
  SIZE 3.36 BY 7.14 ;
  SYMMETRY X Y ;
  SITE CoreSiteHV ;
  PIN Y
    DIRECTION OUTPUT ;
    USE SIGNAL ;
    ANTENNADIFFAREA 2.0808 LAYER Metal1 ;
    PORT
      LAYER Metal1 ;
        RECT 2.705 1.04 3.12 1.745 ;
    END
  END Y
  PIN B
    DIRECTION INPUT ;
    USE SIGNAL ;
    ANTENNAMODEL OXIDE1 ;
      ANTENNAGATEAREA 1.5435 LAYER Metal1 ;
    PORT
      LAYER Metal1 ;
        RECT 1.16 1.96 1.845 2.71 ;
    END
  END B
  PIN A_N
    DIRECTION INPUT ;
    USE SIGNAL ;
    ANTENNAMODEL OXIDE1 ;
      ANTENNAGATEAREA 1.1542 LAYER Metal1 ;
    PORT
      LAYER Metal1 ;
        RECT 0.295 1.96 0.91 2.71 ;
    END
  END A_N
  PIN VDD
    DIRECTION INOUT ;
    USE POWER ;
    SHAPE ABUTMENT ;
    NETEXPR "VDD VDD!" ;
    PORT
      LAYER Metal1 ;
        RECT 0 6.825 3.36 7.36 ;
    END
  END VDD
  PIN VSS
    DIRECTION INOUT ;
    USE GROUND ;
    SHAPE ABUTMENT ;
    NETEXPR "VSS VSS!" ;
    PORT
      LAYER Metal1 ;
        RECT 0 -0.22 3.36 0.22 ;
    END
  END VSS
  OBS
      LAYER Metal1 ;
        RECT 0.155 1.35 0.415 1.62 ;
        RECT 0.155 1.62 2.235 1.78 ;
        RECT 0.155 3.49 2.235 3.93 ;
        RECT 0.155 3.93 0.415 5.19 ;
        RECT 0.195 1.96 0.295 2.71 ;
        RECT 1.01 0.22 1.28 1.37 ;
        RECT 1.015 4.375 1.275 6.825 ;
        RECT 1.845 4.375 3.12 4.76 ;
        RECT 1.845 4.76 2.105 5.865 ;
        RECT 2.025 1.78 2.235 1.95 ;
        RECT 2.025 1.95 2.765 2.705 ;
        RECT 2.025 2.705 2.235 3.49 ;
        RECT 2.675 5.24 2.935 6.825 ;
        RECT 2.96 1.745 3.12 4.375 ;
  END
END sg13g2_hv_nand2b_1

MACRO sg13g2_hv_nand2b_2
  CLASS CORE ;
  ORIGIN 0 0 ;
  FOREIGN sg13g2_hv_nand2b_2 0 0 ;
  SIZE 5.76 BY 7.14 ;
  SYMMETRY X Y ;
  SITE CoreSiteHV ;
  PIN Y
    DIRECTION OUTPUT ;
    USE SIGNAL ;
    ANTENNADIFFAREA 2.3180 LAYER Metal1 ;
    PORT
      LAYER Metal1 ;
        RECT 3.99 3.56 4.28 5.91 ;
    END
  END Y
  PIN B
    DIRECTION INPUT ;
    USE SIGNAL ;
    ANTENNAMODEL OXIDE1 ;
      ANTENNAGATEAREA 3.0690 LAYER Metal1 ;
    PORT
      LAYER Metal1 ;
        RECT 3.12 1.965 3.72 2.72 ;
    END
  END B
  PIN VDD
    DIRECTION INOUT ;
    USE POWER ;
    SHAPE ABUTMENT ;
    NETEXPR "VDD VDD!" ;
    PORT
      LAYER Metal1 ;
        RECT 0 6.825 5.76 7.36 ;
    END
  END VDD
  PIN VSS
    DIRECTION INOUT ;
    USE GROUND ;
    SHAPE ABUTMENT ;
    NETEXPR "VSS VSS!" ;
    PORT
      LAYER Metal1 ;
        RECT 0 -0.22 5.76 0.22 ;
    END
  END VSS
  PIN A_N
    DIRECTION INPUT ;
    USE SIGNAL ;
    ANTENNAMODEL OXIDE1 ;
      ANTENNAGATEAREA 1.1542 LAYER Metal1 ;
    PORT
      LAYER Metal1 ;
        RECT 0.155 1.905 0.93 2.74 ;
    END
  END A_N
  OBS
      LAYER Metal1 ;
        RECT 0.13 0.22 0.39 1.705 ;
        RECT 0.13 3.75 0.39 6.825 ;
        RECT 0.96 1.445 1.285 1.705 ;
        RECT 0.96 3.585 1.285 3.895 ;
        RECT 0.96 3.895 1.22 5.19 ;
        RECT 1.125 1.705 1.285 2.37 ;
        RECT 1.125 2.37 1.79 2.72 ;
        RECT 1.125 2.72 1.285 3.585 ;
        RECT 1.47 3.38 1.73 6.825 ;
        RECT 1.475 1.03 1.735 1.465 ;
        RECT 1.475 1.465 3.41 1.63 ;
        RECT 2.32 0.22 2.58 1.285 ;
        RECT 2.32 3.56 3.99 3.945 ;
        RECT 2.32 3.945 2.58 5.865 ;
        RECT 3.14 0.96 5.08 1.19 ;
        RECT 3.14 1.19 3.41 1.465 ;
        RECT 3.15 4.425 3.41 6.825 ;
        RECT 3.99 1.43 4.28 1.82 ;
        RECT 4.05 1.82 4.28 3.56 ;
        RECT 4.8 1.19 5.08 1.63 ;
        RECT 4.82 3.61 5.08 6.825 ;
  END
END sg13g2_hv_nand2b_2

MACRO sg13g2_hv_nand3_1
  CLASS CORE ;
  ORIGIN 0 0 ;
  FOREIGN sg13g2_hv_nand3_1 0 0 ;
  SIZE 3.36 BY 7.14 ;
  SYMMETRY X Y ;
  SITE CoreSiteHV ;
  PIN B
    DIRECTION INPUT ;
    USE SIGNAL ;
    ANTENNAMODEL OXIDE1 ;
      ANTENNAGATEAREA 1.5435 LAYER Metal1 ;
    PORT
      LAYER Metal1 ;
        RECT 1.16 1.935 1.81 2.795 ;
    END
  END B
  PIN C
    DIRECTION INPUT ;
    USE SIGNAL ;
    ANTENNAMODEL OXIDE1 ;
      ANTENNAGATEAREA 1.5435 LAYER Metal1 ;
    PORT
      LAYER Metal1 ;
        RECT 0.3 1.935 0.775 2.795 ;
    END
  END C
  PIN A
    DIRECTION INPUT ;
    USE SIGNAL ;
    ANTENNAMODEL OXIDE1 ;
      ANTENNAGATEAREA 1.5435 LAYER Metal1 ;
    PORT
      LAYER Metal1 ;
        RECT 2.695 1.935 3.115 2.795 ;
    END
  END A
  PIN Y
    DIRECTION OUTPUT ;
    USE SIGNAL ;
    ANTENNADIFFAREA 2.9954 LAYER Metal1 ;
    PORT
      LAYER Metal1 ;
        RECT 2.74 3.775 3.03 6.03 ;
    END
  END Y
  PIN VDD
    DIRECTION INOUT ;
    USE POWER ;
    SHAPE ABUTMENT ;
    NETEXPR "VDD VDD!" ;
    PORT
      LAYER Metal1 ;
        RECT 0 6.825 3.36 7.36 ;
    END
  END VDD
  PIN VSS
    DIRECTION INOUT ;
    USE GROUND ;
    SHAPE ABUTMENT ;
    NETEXPR "VSS VSS!" ;
    PORT
      LAYER Metal1 ;
        RECT 0 -0.22 3.36 0.22 ;
    END
  END VSS
  OBS
      LAYER Metal1 ;
        RECT 0.28 0.22 0.54 1.66 ;
        RECT 0.28 3.775 0.54 6.825 ;
        RECT 1.11 3.775 2.74 4.16 ;
        RECT 1.11 4.16 1.37 6.03 ;
        RECT 1.94 4.59 2.2 6.825 ;
        RECT 2.04 1.405 3.03 1.66 ;
        RECT 2.04 1.66 2.205 3.775 ;
        RECT 2.77 1.06 3.03 1.405 ;
  END
END sg13g2_hv_nand3_1

MACRO sg13g2_hv_nand3b_1
  CLASS CORE ;
  ORIGIN 0 0 ;
  FOREIGN sg13g2_hv_nand3b_1 0 0 ;
  SIZE 5.28 BY 7.14 ;
  SYMMETRY X Y ;
  SITE CoreSiteHV ;
  PIN B
    DIRECTION INPUT ;
    USE SIGNAL ;
    ANTENNAMODEL OXIDE1 ;
      ANTENNAGATEAREA 1.5435 LAYER Metal1 ;
    PORT
      LAYER Metal1 ;
        RECT 2.71 1.905 3.33 2.825 ;
    END
  END B
  PIN C
    DIRECTION INPUT ;
    USE SIGNAL ;
    ANTENNAMODEL OXIDE1 ;
      ANTENNAGATEAREA 1.5435 LAYER Metal1 ;
    PORT
      LAYER Metal1 ;
        RECT 1.91 1.905 2.53 2.825 ;
    END
  END C
  PIN Y
    DIRECTION OUTPUT ;
    USE SIGNAL ;
    ANTENNADIFFAREA 2.9954 LAYER Metal1 ;
    PORT
      LAYER Metal1 ;
        RECT 4.22 3.56 4.68 5.865 ;
    END
  END Y
  PIN VDD
    DIRECTION INOUT ;
    USE POWER ;
    SHAPE ABUTMENT ;
    NETEXPR "VDD VDD!" ;
    PORT
      LAYER Metal1 ;
        RECT 0 6.825 5.28 7.36 ;
    END
  END VDD
  PIN VSS
    DIRECTION INOUT ;
    USE GROUND ;
    SHAPE ABUTMENT ;
    NETEXPR "VSS VSS!" ;
    PORT
      LAYER Metal1 ;
        RECT 0 -0.22 5.28 0.22 ;
    END
  END VSS
  PIN A_N
    DIRECTION INPUT ;
    USE SIGNAL ;
    ANTENNAMODEL OXIDE1 ;
      ANTENNAGATEAREA 1.1542 LAYER Metal1 ;
    PORT
      LAYER Metal1 ;
        RECT 0.79 1.905 1.67 2.825 ;
    END
  END A_N
  OBS
      LAYER Metal1 ;
        RECT 0.44 1.375 0.75 1.5 ;
        RECT 0.44 1.5 4.09 1.66 ;
        RECT 0.44 1.66 0.61 3.75 ;
        RECT 0.44 3.75 0.985 5.19 ;
        RECT 1.67 0.22 1.94 1.32 ;
        RECT 1.73 3.61 1.99 6.825 ;
        RECT 2.56 3.56 4.22 4.015 ;
        RECT 2.56 4.015 2.82 5.865 ;
        RECT 3.39 4.46 3.65 6.825 ;
        RECT 3.66 1.66 4.09 2.42 ;
        RECT 3.66 2.42 4.305 2.725 ;
        RECT 4.325 1.06 4.68 1.66 ;
        RECT 4.51 1.66 4.68 3.56 ;
  END
END sg13g2_hv_nand3b_1

MACRO sg13g2_hv_nand4_1
  CLASS CORE ;
  ORIGIN 0 0 ;
  FOREIGN sg13g2_hv_nand4_1 0 0 ;
  SIZE 4.32 BY 7.14 ;
  SYMMETRY X Y ;
  SITE CoreSiteHV ;
  PIN B
    DIRECTION INPUT ;
    USE SIGNAL ;
    ANTENNAMODEL OXIDE1 ;
      ANTENNAGATEAREA 1.5435 LAYER Metal1 ;
    PORT
      LAYER Metal1 ;
        RECT 1.96 1.57 2.2 1.81 ;
    END
  END B
  PIN C
    DIRECTION INPUT ;
    USE SIGNAL ;
    ANTENNAMODEL OXIDE1 ;
      ANTENNAGATEAREA 1.5435 LAYER Metal1 ;
    PORT
      LAYER Metal1 ;
        RECT 1.16 2.025 1.705 2.745 ;
    END
  END C
  PIN A
    DIRECTION INPUT ;
    USE SIGNAL ;
    ANTENNAMODEL OXIDE1 ;
      ANTENNAGATEAREA 1.5435 LAYER Metal1 ;
    PORT
      LAYER Metal1 ;
        RECT 2.76 1.15 3 1.39 ;
    END
  END A
  PIN Y
    DIRECTION OUTPUT ;
    USE SIGNAL ;
    ANTENNADIFFAREA 3.9100 LAYER Metal1 ;
    PORT
      LAYER Metal1 ;
        RECT 2.76 3.775 3.03 6.02 ;
    END
  END Y
  PIN VDD
    DIRECTION INOUT ;
    USE POWER ;
    SHAPE ABUTMENT ;
    NETEXPR "VDD VDD!" ;
    PORT
      LAYER Metal1 ;
        RECT 0 6.825 4.32 7.36 ;
    END
  END VDD
  PIN VSS
    DIRECTION INOUT ;
    USE GROUND ;
    SHAPE ABUTMENT ;
    NETEXPR "VSS VSS!" ;
    PORT
      LAYER Metal1 ;
        RECT 0 -0.22 4.32 0.22 ;
    END
  END VSS
  PIN D
    DIRECTION INPUT ;
    USE SIGNAL ;
    ANTENNAMODEL OXIDE1 ;
      ANTENNAGATEAREA 1.5435 LAYER Metal1 ;
    PORT
      LAYER Metal1 ;
        RECT 0.25 2.025 0.6 2.745 ;
    END
  END D
  OBS
      LAYER Metal1 ;
        RECT 0.28 0.22 0.54 1.66 ;
        RECT 0.28 3.775 0.54 6.825 ;
        RECT 1.11 3.775 2.76 4.16 ;
        RECT 1.11 4.16 1.37 6.02 ;
        RECT 1.94 4.59 2.2 6.825 ;
        RECT 2.08 1.81 2.33 2.42 ;
        RECT 2.08 2.42 2.535 2.725 ;
        RECT 2.2 1.57 2.33 1.81 ;
        RECT 2.8 1.39 2.96 1.7 ;
        RECT 2.8 1.7 3.085 1.86 ;
        RECT 2.925 1.86 3.085 2.42 ;
        RECT 2.925 2.42 3.47 2.725 ;
        RECT 3.03 3.775 3.9 4.16 ;
        RECT 3.6 1.06 3.9 1.66 ;
        RECT 3.6 4.59 3.86 6.825 ;
        RECT 3.74 1.66 3.9 3.775 ;
  END
END sg13g2_hv_nand4_1

MACRO sg13g2_hv_nor2_1
  CLASS CORE ;
  ORIGIN 0 0 ;
  FOREIGN sg13g2_hv_nor2_1 0 0 ;
  SIZE 3.36 BY 7.14 ;
  SYMMETRY X Y ;
  SITE CoreSiteHV ;
  PIN A
    DIRECTION INPUT ;
    USE SIGNAL ;
    ANTENNAMODEL OXIDE1 ;
      ANTENNAGATEAREA 1.5435 LAYER Metal1 ;
    PORT
      LAYER Metal1 ;
        RECT 0.35 1.95 0.68 2.725 ;
    END
  END A
  PIN B
    DIRECTION INPUT ;
    USE SIGNAL ;
    ANTENNAMODEL OXIDE1 ;
      ANTENNAGATEAREA 1.5435 LAYER Metal1 ;
    PORT
      LAYER Metal1 ;
        RECT 2.17 1.95 2.79 2.725 ;
    END
  END B
  PIN Y
    DIRECTION OUTPUT ;
    USE SIGNAL ;
    ANTENNADIFFAREA 1.4178 LAYER Metal1 ;
    PORT
      LAYER Metal1 ;
        RECT 2.19 3.645 2.78 5.865 ;
    END
  END Y
  PIN VDD
    DIRECTION INOUT ;
    USE POWER ;
    SHAPE ABUTMENT ;
    NETEXPR "VDD VDD!" ;
    PORT
      LAYER Metal1 ;
        RECT 0 6.825 3.36 7.36 ;
    END
  END VDD
  PIN VSS
    DIRECTION INOUT ;
    USE GROUND ;
    SHAPE ABUTMENT ;
    NETEXPR "VSS VSS!" ;
    PORT
      LAYER Metal1 ;
        RECT 0 -0.22 3.36 0.22 ;
    END
  END VSS
  OBS
      LAYER Metal1 ;
        RECT 0.4 0.22 0.66 1.64 ;
        RECT 0.4 3.61 0.66 6.825 ;
        RECT 1.195 1.035 1.8 1.64 ;
        RECT 1.195 1.64 1.395 3.645 ;
        RECT 1.195 3.645 2.19 4.125 ;
        RECT 2.63 0.22 2.89 1.64 ;
  END
END sg13g2_hv_nor2_1

MACRO sg13g2_hv_nor2_2
  CLASS CORE ;
  ORIGIN 0 0 ;
  FOREIGN sg13g2_hv_nor2_2 0 0 ;
  SIZE 4.32 BY 7.14 ;
  SYMMETRY X Y ;
  SITE CoreSiteHV ;
  PIN A
    DIRECTION INPUT ;
    USE SIGNAL ;
    ANTENNAMODEL OXIDE1 ;
      ANTENNAGATEAREA 3.0870 LAYER Metal1 ;
    PORT
      LAYER Metal1 ;
        RECT 1.07 1.96 1.45 2.715 ;
    END
  END A
  PIN B
    DIRECTION INPUT ;
    USE SIGNAL ;
    ANTENNAMODEL OXIDE1 ;
      ANTENNAGATEAREA 3.0870 LAYER Metal1 ;
    PORT
      LAYER Metal1 ;
        RECT 2.73 1.96 3.11 2.715 ;
    END
  END B
  PIN Y
    DIRECTION OUTPUT ;
    USE SIGNAL ;
    ANTENNADIFFAREA 1.5846 LAYER Metal1 ;
    PORT
      LAYER Metal1 ;
        RECT 2.74 3.61 3.05 4.81 ;
    END
  END Y
  PIN VDD
    DIRECTION INOUT ;
    USE POWER ;
    SHAPE ABUTMENT ;
    NETEXPR "VDD VDD!" ;
    PORT
      LAYER Metal1 ;
        RECT 0 6.825 4.32 7.36 ;
    END
  END VDD
  PIN VSS
    DIRECTION INOUT ;
    USE GROUND ;
    SHAPE ABUTMENT ;
    NETEXPR "VSS VSS!" ;
    PORT
      LAYER Metal1 ;
        RECT 0 -0.22 4.32 0.22 ;
    END
  END VSS
  OBS
      LAYER Metal1 ;
        RECT 0.3 0.22 0.56 1.64 ;
        RECT 0.3 3.61 2.22 3.99 ;
        RECT 0.3 3.99 0.56 5.865 ;
        RECT 1.13 1.04 1.385 1.505 ;
        RECT 1.13 1.505 3.88 1.67 ;
        RECT 1.13 4.425 1.39 6.825 ;
        RECT 1.96 0.22 2.22 1.3 ;
        RECT 1.96 3.99 2.22 5.24 ;
        RECT 1.96 5.24 3.88 5.865 ;
        RECT 2.79 1.02 3.045 1.505 ;
        RECT 3.05 3.61 3.88 3.99 ;
        RECT 3.62 0.22 3.88 1.295 ;
        RECT 3.62 4.425 3.88 5.24 ;
        RECT 3.72 1.67 3.88 3.61 ;
  END
END sg13g2_hv_nor2_2

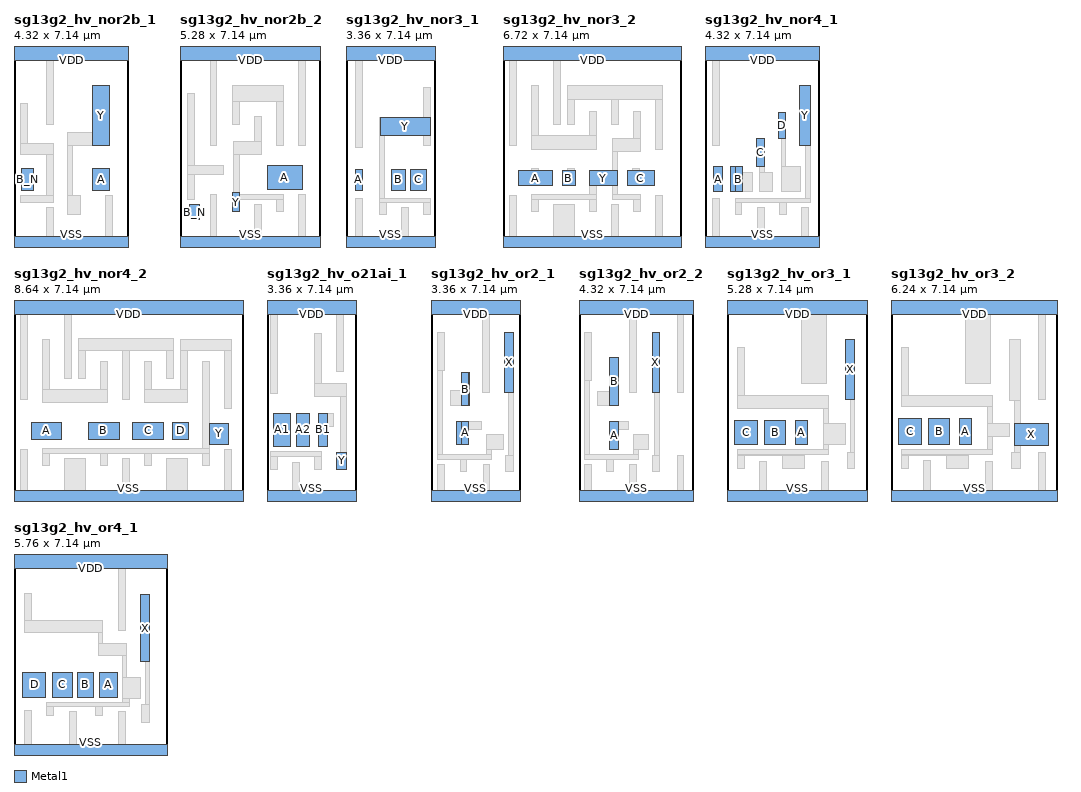
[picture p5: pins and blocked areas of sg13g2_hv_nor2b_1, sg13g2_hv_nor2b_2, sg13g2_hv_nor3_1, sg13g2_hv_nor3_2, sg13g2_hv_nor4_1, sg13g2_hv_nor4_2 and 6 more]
MACRO sg13g2_hv_nor2b_1
  CLASS CORE ;
  ORIGIN 0 0 ;
  FOREIGN sg13g2_hv_nor2b_1 0 0 ;
  SIZE 4.32 BY 7.14 ;
  SYMMETRY X Y ;
  SITE CoreSiteHV ;
  PIN A
    DIRECTION INPUT ;
    USE SIGNAL ;
    ANTENNAMODEL OXIDE1 ;
      ANTENNAGATEAREA 1.5435 LAYER Metal1 ;
    PORT
      LAYER Metal1 ;
        RECT 2.965 1.93 3.59 2.745 ;
    END
  END A
  PIN B_N
    DIRECTION INPUT ;
    USE SIGNAL ;
    ANTENNAMODEL OXIDE1 ;
      ANTENNAGATEAREA 1.1542 LAYER Metal1 ;
    PORT
      LAYER Metal1 ;
        RECT 0.27 1.93 0.745 2.745 ;
    END
  END B_N
  PIN Y
    DIRECTION OUTPUT ;
    USE SIGNAL ;
    ANTENNADIFFAREA 1.4178 LAYER Metal1 ;
    PORT
      LAYER Metal1 ;
        RECT 2.965 3.645 3.59 5.865 ;
    END
  END Y
  PIN VDD
    DIRECTION INOUT ;
    USE POWER ;
    SHAPE ABUTMENT ;
    NETEXPR "VDD VDD!" ;
    PORT
      LAYER Metal1 ;
        RECT 0 6.825 4.32 7.36 ;
    END
  END VDD
  PIN VSS
    DIRECTION INOUT ;
    USE GROUND ;
    SHAPE ABUTMENT ;
    NETEXPR "VSS VSS!" ;
    PORT
      LAYER Metal1 ;
        RECT 0 -0.22 4.32 0.22 ;
    END
  END VSS
  OBS
      LAYER Metal1 ;
        RECT 0.25 1.48 1.47 1.74 ;
        RECT 0.25 3.27 1.47 3.705 ;
        RECT 0.25 3.705 0.51 5.19 ;
        RECT 1.21 0.22 1.47 1.3 ;
        RECT 1.21 1.74 1.47 3.27 ;
        RECT 1.21 4.41 1.47 6.825 ;
        RECT 2.005 1.035 2.49 1.74 ;
        RECT 2.005 1.74 2.205 3.645 ;
        RECT 2.005 3.645 2.965 4.125 ;
        RECT 3.44 0.22 3.7 1.74 ;
  END
END sg13g2_hv_nor2b_1

MACRO sg13g2_hv_nor2b_2
  CLASS CORE ;
  ORIGIN 0 0 ;
  FOREIGN sg13g2_hv_nor2b_2 0 0 ;
  SIZE 5.28 BY 7.14 ;
  SYMMETRY X Y ;
  SITE CoreSiteHV ;
  PIN A
    DIRECTION INPUT ;
    USE SIGNAL ;
    ANTENNAMODEL OXIDE1 ;
      ANTENNAGATEAREA 3.0690 LAYER Metal1 ;
    PORT
      LAYER Metal1 ;
        RECT 3.285 1.97 4.6 2.87 ;
    END
  END A
  PIN B_N
    DIRECTION INPUT ;
    USE SIGNAL ;
    ANTENNAMODEL OXIDE1 ;
      ANTENNAGATEAREA 1.3680 LAYER Metal1 ;
    PORT
      LAYER Metal1 ;
        RECT 0.34 0.83 0.73 1.41 ;
    END
  END B_N
  PIN Y
    DIRECTION OUTPUT ;
    USE SIGNAL ;
    ANTENNADIFFAREA 1.5694 LAYER Metal1 ;
    PORT
      LAYER Metal1 ;
        RECT 1.96 1.15 2.22 1.85 ;
    END
  END Y
  PIN VDD
    DIRECTION INOUT ;
    USE POWER ;
    SHAPE ABUTMENT ;
    NETEXPR "VDD VDD!" ;
    PORT
      LAYER Metal1 ;
        RECT 0 6.825 5.28 7.36 ;
    END
  END VDD
  PIN VSS
    DIRECTION INOUT ;
    USE GROUND ;
    SHAPE ABUTMENT ;
    NETEXPR "VSS VSS!" ;
    PORT
      LAYER Metal1 ;
        RECT 0 -0.22 5.28 0.22 ;
    END
  END VSS
  OBS
      LAYER Metal1 ;
        RECT 0.27 1.59 0.53 2.53 ;
        RECT 0.27 2.53 1.625 2.87 ;
        RECT 0.27 2.87 0.53 5.575 ;
        RECT 1.13 0.22 1.39 1.77 ;
        RECT 1.13 3.61 1.39 6.825 ;
        RECT 1.96 4.425 2.22 5.29 ;
        RECT 1.96 5.29 3.88 5.865 ;
        RECT 2 1.85 2.22 3.27 ;
        RECT 2 3.27 3.05 3.765 ;
        RECT 2.22 1.59 3.88 1.79 ;
        RECT 2.79 0.22 3.05 1.41 ;
        RECT 2.79 3.765 3.05 4.71 ;
        RECT 3.62 1.15 3.88 1.59 ;
        RECT 3.62 3.61 3.88 5.29 ;
        RECT 4.45 0.22 4.71 1.77 ;
        RECT 4.45 3.61 4.71 6.825 ;
  END
END sg13g2_hv_nor2b_2

MACRO sg13g2_hv_nor3_1
  CLASS CORE ;
  ORIGIN 0 0 ;
  FOREIGN sg13g2_hv_nor3_1 0 0 ;
  SIZE 3.36 BY 7.14 ;
  SYMMETRY X Y ;
  SITE CoreSiteHV ;
  PIN A
    DIRECTION INPUT ;
    USE SIGNAL ;
    ANTENNAMODEL OXIDE1 ;
      ANTENNAGATEAREA 1.5570 LAYER Metal1 ;
    PORT
      LAYER Metal1 ;
        RECT 0.34 1.945 0.62 2.725 ;
    END
  END A
  PIN B
    DIRECTION INPUT ;
    USE SIGNAL ;
    ANTENNAMODEL OXIDE1 ;
      ANTENNAGATEAREA 1.5570 LAYER Metal1 ;
    PORT
      LAYER Metal1 ;
        RECT 1.705 1.945 2.22 2.725 ;
    END
  END B
  PIN C
    DIRECTION INPUT ;
    USE SIGNAL ;
    ANTENNAMODEL OXIDE1 ;
      ANTENNAGATEAREA 1.5570 LAYER Metal1 ;
    PORT
      LAYER Metal1 ;
        RECT 2.43 1.945 3.02 2.725 ;
    END
  END C
  PIN Y
    DIRECTION OUTPUT ;
    USE SIGNAL ;
    ANTENNADIFFAREA 1.7000 LAYER Metal1 ;
    PORT
      LAYER Metal1 ;
        RECT 1.28 3.99 3.185 4.675 ;
    END
  END Y
  PIN VDD
    DIRECTION INOUT ;
    USE POWER ;
    SHAPE ABUTMENT ;
    NETEXPR "VDD VDD!" ;
    PORT
      LAYER Metal1 ;
        RECT 0 6.825 3.36 7.36 ;
    END
  END VDD
  PIN VSS
    DIRECTION INOUT ;
    USE GROUND ;
    SHAPE ABUTMENT ;
    NETEXPR "VSS VSS!" ;
    PORT
      LAYER Metal1 ;
        RECT 0 -0.22 3.36 0.22 ;
    END
  END VSS
  OBS
      LAYER Metal1 ;
        RECT 0.375 0.22 0.635 1.65 ;
        RECT 0.375 3.57 0.635 6.825 ;
        RECT 1.265 1.05 1.525 1.49 ;
        RECT 1.265 1.49 3.185 1.65 ;
        RECT 1.265 1.65 1.44 3.99 ;
        RECT 1.265 3.99 1.28 4.675 ;
        RECT 2.095 0.22 2.355 1.31 ;
        RECT 2.925 1.05 3.185 1.49 ;
        RECT 2.925 3.61 3.185 3.99 ;
        RECT 2.925 4.675 3.185 5.79 ;
  END
END sg13g2_hv_nor3_1

MACRO sg13g2_hv_nor3_2
  CLASS CORE ;
  ORIGIN 0 0 ;
  FOREIGN sg13g2_hv_nor3_2 0 0 ;
  SIZE 6.72 BY 7.14 ;
  SYMMETRY X Y ;
  SITE CoreSiteHV ;
  PIN A
    DIRECTION INPUT ;
    USE SIGNAL ;
    ANTENNAMODEL OXIDE1 ;
      ANTENNAGATEAREA 3.0870 LAYER Metal1 ;
    PORT
      LAYER Metal1 ;
        RECT 0.57 2.125 1.85 2.675 ;
    END
  END A
  PIN B
    DIRECTION INPUT ;
    USE SIGNAL ;
    ANTENNAMODEL OXIDE1 ;
      ANTENNAGATEAREA 3.0870 LAYER Metal1 ;
    PORT
      LAYER Metal1 ;
        RECT 2.235 2.125 2.715 2.675 ;
    END
  END B
  PIN C
    DIRECTION INPUT ;
    USE SIGNAL ;
    ANTENNAMODEL OXIDE1 ;
      ANTENNAGATEAREA 3.0870 LAYER Metal1 ;
    PORT
      LAYER Metal1 ;
        RECT 4.675 2.125 5.68 2.675 ;
    END
  END C
  PIN Y
    DIRECTION OUTPUT ;
    USE SIGNAL ;
    ANTENNADIFFAREA 1.8658 LAYER Metal1 ;
    PORT
      LAYER Metal1 ;
        RECT 3.25 2.125 4.3 2.675 ;
    END
  END Y
  PIN VDD
    DIRECTION INOUT ;
    USE POWER ;
    SHAPE ABUTMENT ;
    NETEXPR "VDD VDD!" ;
    PORT
      LAYER Metal1 ;
        RECT 0 6.825 6.72 7.36 ;
    END
  END VDD
  PIN VSS
    DIRECTION INOUT ;
    USE GROUND ;
    SHAPE ABUTMENT ;
    NETEXPR "VSS VSS!" ;
    PORT
      LAYER Metal1 ;
        RECT 0 -0.22 6.72 0.22 ;
    END
  END VSS
  OBS
      LAYER Metal1 ;
        RECT 0.25 0.22 0.51 1.75 ;
        RECT 0.25 3.61 0.51 6.825 ;
        RECT 1.08 1.15 1.34 1.59 ;
        RECT 1.08 1.59 3.51 1.77 ;
        RECT 1.08 3.475 3.51 3.99 ;
        RECT 1.08 3.99 1.34 5.865 ;
        RECT 1.085 2.675 1.345 2.765 ;
        RECT 1.91 0.22 2.68 1.41 ;
        RECT 1.91 4.425 2.17 6.825 ;
        RECT 2.42 4.425 2.68 5.35 ;
        RECT 2.42 5.35 6 5.865 ;
        RECT 2.435 2.675 2.695 2.765 ;
        RECT 3.25 1.15 3.51 1.59 ;
        RECT 3.25 1.77 3.51 2.125 ;
        RECT 3.25 3.99 3.51 4.915 ;
        RECT 4.08 0.22 4.34 1.41 ;
        RECT 4.08 4.425 4.34 5.35 ;
        RECT 4.1 1.59 5.17 1.78 ;
        RECT 4.1 1.78 4.3 2.125 ;
        RECT 4.1 2.675 4.3 3.405 ;
        RECT 4.1 3.405 5.17 3.885 ;
        RECT 4.86 2.675 5.12 2.765 ;
        RECT 4.91 1.15 5.17 1.59 ;
        RECT 4.91 3.885 5.17 4.915 ;
        RECT 5.74 0.22 6 1.75 ;
        RECT 5.74 3.475 6 5.35 ;
        RECT 6.72 -0.22 6.725 0.22 ;
  END
END sg13g2_hv_nor3_2

MACRO sg13g2_hv_nor4_1
  CLASS CORE ;
  ORIGIN 0 0 ;
  FOREIGN sg13g2_hv_nor4_1 0 0 ;
  SIZE 4.32 BY 7.14 ;
  SYMMETRY X Y ;
  SITE CoreSiteHV ;
  PIN A
    DIRECTION INPUT ;
    USE SIGNAL ;
    ANTENNAMODEL OXIDE1 ;
      ANTENNAGATEAREA 1.5435 LAYER Metal1 ;
    PORT
      LAYER Metal1 ;
        RECT 0.33 1.885 0.655 2.84 ;
    END
  END A
  PIN B
    DIRECTION INPUT ;
    USE SIGNAL ;
    ANTENNAMODEL OXIDE1 ;
      ANTENNAGATEAREA 1.5435 LAYER Metal1 ;
    PORT
      LAYER Metal1 ;
        RECT 1.155 1.885 1.4 2.84 ;
        RECT 0.96 1.885 1.155 2.84 ;
    END
  END B
  PIN C
    DIRECTION INPUT ;
    USE SIGNAL ;
    ANTENNAMODEL OXIDE1 ;
      ANTENNAGATEAREA 1.5435 LAYER Metal1 ;
    PORT
      LAYER Metal1 ;
        RECT 1.94 2.84 2.22 3.885 ;
    END
  END C
  PIN D
    DIRECTION INPUT ;
    USE SIGNAL ;
    ANTENNAMODEL OXIDE1 ;
      ANTENNAGATEAREA 1.5435 LAYER Metal1 ;
    PORT
      LAYER Metal1 ;
        RECT 2.76 3.885 3.02 4.855 ;
    END
  END D
  PIN Y
    DIRECTION OUTPUT ;
    USE SIGNAL ;
    ANTENNADIFFAREA 1.9210 LAYER Metal1 ;
    PORT
      LAYER Metal1 ;
        RECT 3.56 3.61 3.98 5.865 ;
    END
  END Y
  PIN VDD
    DIRECTION INOUT ;
    USE POWER ;
    SHAPE ABUTMENT ;
    NETEXPR "VDD VDD!" ;
    PORT
      LAYER Metal1 ;
        RECT 0 6.825 4.32 7.36 ;
    END
  END VDD
  PIN VSS
    DIRECTION INOUT ;
    USE GROUND ;
    SHAPE ABUTMENT ;
    NETEXPR "VSS VSS!" ;
    PORT
      LAYER Metal1 ;
        RECT 0 -0.22 4.32 0.22 ;
    END
  END VSS
  OBS
      LAYER Metal1 ;
        RECT 0.3 0.22 0.56 1.64 ;
        RECT 0.3 3.61 0.56 6.825 ;
        RECT 1.13 1.04 1.39 1.48 ;
        RECT 1.13 1.48 3.98 1.64 ;
        RECT 1.4 1.885 1.795 2.61 ;
        RECT 1.96 0.22 2.22 1.3 ;
        RECT 2.05 1.885 2.555 2.61 ;
        RECT 2.05 2.61 2.22 2.84 ;
        RECT 2.79 1.04 3.05 1.48 ;
        RECT 2.86 1.885 3.6 2.84 ;
        RECT 2.86 2.84 3.02 3.885 ;
        RECT 3.62 0.22 3.88 1.3 ;
        RECT 3.785 1.64 3.98 3.61 ;
  END
END sg13g2_hv_nor4_1

MACRO sg13g2_hv_nor4_2
  CLASS CORE ;
  ORIGIN 0 0 ;
  FOREIGN sg13g2_hv_nor4_2 0 0 ;
  SIZE 8.64 BY 7.14 ;
  SYMMETRY X Y ;
  SITE CoreSiteHV ;
  PIN A
    DIRECTION INPUT ;
    USE SIGNAL ;
    ANTENNAMODEL OXIDE1 ;
      ANTENNAGATEAREA 3.0870 LAYER Metal1 ;
    PORT
      LAYER Metal1 ;
        RECT 0.64 2.125 1.78 2.765 ;
    END
  END A
  PIN B
    DIRECTION INPUT ;
    USE SIGNAL ;
    ANTENNAMODEL OXIDE1 ;
      ANTENNAGATEAREA 3.0870 LAYER Metal1 ;
    PORT
      LAYER Metal1 ;
        RECT 2.81 2.125 3.95 2.765 ;
    END
  END B
  PIN C
    DIRECTION INPUT ;
    USE SIGNAL ;
    ANTENNAMODEL OXIDE1 ;
      ANTENNAGATEAREA 3.0870 LAYER Metal1 ;
    PORT
      LAYER Metal1 ;
        RECT 4.47 2.125 5.61 2.765 ;
    END
  END C
  PIN Y
    DIRECTION OUTPUT ;
    USE SIGNAL ;
    ANTENNADIFFAREA 2.1470 LAYER Metal1 ;
    PORT
      LAYER Metal1 ;
        RECT 7.34 1.95 8.045 2.715 ;
    END
  END Y
  PIN VSS
    DIRECTION INOUT ;
    USE GROUND ;
    SHAPE ABUTMENT ;
    NETEXPR "VSS VSS!" ;
    PORT
      LAYER Metal1 ;
        RECT 0 -0.22 8.64 0.22 ;
    END
  END VSS
  PIN VDD
    DIRECTION INOUT ;
    USE POWER ;
    SHAPE ABUTMENT ;
    NETEXPR "VDD VDD!" ;
    PORT
      LAYER Metal1 ;
        RECT 0 6.825 8.64 7.36 ;
    END
  END VDD
  PIN D
    DIRECTION INPUT ;
    USE SIGNAL ;
    ANTENNAMODEL OXIDE1 ;
      ANTENNAGATEAREA 3.0870 LAYER Metal1 ;
    PORT
      LAYER Metal1 ;
        RECT 5.945 2.125 6.56 2.765 ;
    END
  END D
  OBS
      LAYER Metal1 ;
        RECT 0.25 0.22 0.51 1.75 ;
        RECT 0.25 3.61 0.51 6.825 ;
        RECT 1.08 1.15 1.34 1.59 ;
        RECT 1.08 1.59 7.34 1.78 ;
        RECT 1.08 3.51 3.51 3.99 ;
        RECT 1.08 3.99 1.34 5.865 ;
        RECT 1.91 0.22 2.68 1.41 ;
        RECT 1.91 4.425 2.17 6.825 ;
        RECT 2.42 4.425 2.68 5.48 ;
        RECT 2.42 5.48 6 5.91 ;
        RECT 3.25 1.15 3.51 1.59 ;
        RECT 3.25 3.99 3.51 5.05 ;
        RECT 4.08 0.22 4.34 1.41 ;
        RECT 4.08 3.61 4.34 5.48 ;
        RECT 4.91 1.15 5.17 1.59 ;
        RECT 4.91 3.51 6.51 3.99 ;
        RECT 4.91 3.99 5.17 5.05 ;
        RECT 5.74 0.22 6.51 1.41 ;
        RECT 5.74 4.425 6 5.48 ;
        RECT 6.25 3.99 6.51 5.48 ;
        RECT 6.25 5.48 8.17 5.865 ;
        RECT 7.08 1.15 7.34 1.59 ;
        RECT 7.08 1.78 7.34 5.05 ;
        RECT 7.91 0.22 8.17 1.75 ;
        RECT 7.91 3.27 8.17 5.48 ;
  END
END sg13g2_hv_nor4_2

MACRO sg13g2_hv_o21ai_1
  CLASS CORE ;
  ORIGIN 0 0 ;
  FOREIGN sg13g2_hv_o21ai_1 0 0 ;
  SIZE 3.36 BY 7.14 ;
  SYMMETRY X Y ;
  SITE CoreSiteHV ;
  PIN B1
    DIRECTION INPUT ;
    USE SIGNAL ;
    ANTENNAMODEL OXIDE1 ;
      ANTENNAGATEAREA 1.5435 LAYER Metal1 ;
    PORT
      LAYER Metal1 ;
        RECT 1.92 1.86 2.26 3.105 ;
    END
  END B1
  PIN VDD
    DIRECTION INOUT ;
    USE POWER ;
    SHAPE ABUTMENT ;
    NETEXPR "VDD VDD!" ;
    PORT
      LAYER Metal1 ;
        RECT 0 6.825 3.36 7.36 ;
    END
  END VDD
  PIN Y
    DIRECTION OUTPUT ;
    USE SIGNAL ;
    ANTENNADIFFAREA 2.0808 LAYER Metal1 ;
    PORT
      LAYER Metal1 ;
        RECT 2.62 1 2.99 1.65 ;
    END
  END Y
  PIN VSS
    DIRECTION INOUT ;
    USE GROUND ;
    SHAPE ABUTMENT ;
    NETEXPR "VSS VSS!" ;
    PORT
      LAYER Metal1 ;
        RECT 0 -0.22 3.36 0.22 ;
    END
  END VSS
  PIN A1
    DIRECTION INPUT ;
    USE SIGNAL ;
    ANTENNAMODEL OXIDE1 ;
      ANTENNAGATEAREA 1.5435 LAYER Metal1 ;
    PORT
      LAYER Metal1 ;
        RECT 0.24 1.86 0.9 3.105 ;
    END
  END A1
  PIN A2
    DIRECTION INPUT ;
    USE SIGNAL ;
    ANTENNAMODEL OXIDE1 ;
      ANTENNAGATEAREA 1.5435 LAYER Metal1 ;
    PORT
      LAYER Metal1 ;
        RECT 1.1 1.86 1.58 3.105 ;
    END
  END A2
  OBS
      LAYER Metal1 ;
        RECT 0.13 1 0.39 1.49 ;
        RECT 0.13 1.49 2.05 1.675 ;
        RECT 0.13 3.85 0.39 6.825 ;
        RECT 0.96 0.22 1.22 1.27 ;
        RECT 1.79 1 2.05 1.49 ;
        RECT 1.79 3.73 2.99 4.23 ;
        RECT 1.79 4.23 2.05 6.105 ;
        RECT 2.26 2.625 2.485 3.105 ;
        RECT 2.62 4.665 2.88 6.825 ;
        RECT 2.77 1.65 2.99 3.73 ;
  END
END sg13g2_hv_o21ai_1

MACRO sg13g2_hv_or2_1
  CLASS CORE ;
  ORIGIN 0 0 ;
  FOREIGN sg13g2_hv_or2_1 0 0 ;
  SIZE 3.36 BY 7.14 ;
  SYMMETRY X Y ;
  SITE CoreSiteHV ;
  PIN VSS
    DIRECTION INOUT ;
    USE GROUND ;
    SHAPE ABUTMENT ;
    NETEXPR "VSS VSS!" ;
    PORT
      LAYER Metal1 ;
        RECT 0 -0.22 3.36 0.22 ;
    END
  END VSS
  PIN VDD
    DIRECTION INOUT ;
    USE POWER ;
    SHAPE ABUTMENT ;
    NETEXPR "VDD VDD!" ;
    PORT
      LAYER Metal1 ;
        RECT 0 6.825 3.36 7.36 ;
    END
  END VDD
  PIN X
    DIRECTION OUTPUT ;
    USE SIGNAL ;
    ANTENNADIFFAREA 1.1662 LAYER Metal1 ;
    PORT
      LAYER Metal1 ;
        RECT 2.76 3.895 3.11 6.15 ;
    END
  END X
  PIN B
    DIRECTION INPUT ;
    USE SIGNAL ;
    ANTENNAMODEL OXIDE1 ;
      ANTENNAGATEAREA 1.1542 LAYER Metal1 ;
    PORT
      LAYER Metal1 ;
        RECT 1.16 3.39 1.4 4.64 ;
        RECT 1.4 3.39 1.44 4.64 ;
    END
  END B
  PIN A
    DIRECTION INPUT ;
    USE SIGNAL ;
    ANTENNAMODEL OXIDE1 ;
      ANTENNAGATEAREA 1.1542 LAYER Metal1 ;
    PORT
      LAYER Metal1 ;
        RECT 1.16 1.925 1.4 2.81 ;
        RECT 0.96 1.925 1.16 2.81 ;
    END
  END A
  OBS
      LAYER Metal1 ;
        RECT 0.26 0.22 0.52 1.19 ;
        RECT 0.26 1.37 2.275 1.55 ;
        RECT 0.26 1.55 0.445 4.71 ;
        RECT 0.26 4.71 0.52 6.15 ;
        RECT 0.735 3.39 1.16 3.97 ;
        RECT 1.09 0.93 1.35 1.37 ;
        RECT 1.4 2.51 1.895 2.81 ;
        RECT 1.94 3.895 2.2 6.825 ;
        RECT 1.955 0.22 2.215 1.19 ;
        RECT 2.085 1.55 2.275 1.745 ;
        RECT 2.085 1.745 2.73 2.32 ;
        RECT 2.785 0.93 3.11 1.53 ;
        RECT 2.915 1.53 3.11 3.895 ;
  END
END sg13g2_hv_or2_1

MACRO sg13g2_hv_or2_2
  CLASS CORE ;
  ORIGIN 0 0 ;
  FOREIGN sg13g2_hv_or2_2 0 0 ;
  SIZE 4.32 BY 7.14 ;
  SYMMETRY X Y ;
  SITE CoreSiteHV ;
  PIN VSS
    DIRECTION INOUT ;
    USE GROUND ;
    SHAPE ABUTMENT ;
    NETEXPR "VSS VSS!" ;
    PORT
      LAYER Metal1 ;
        RECT 0 -0.22 4.32 0.22 ;
    END
  END VSS
  PIN VDD
    DIRECTION INOUT ;
    USE POWER ;
    SHAPE ABUTMENT ;
    NETEXPR "VDD VDD!" ;
    PORT
      LAYER Metal1 ;
        RECT 0 6.825 4.32 7.36 ;
    END
  END VDD
  PIN X
    DIRECTION OUTPUT ;
    USE SIGNAL ;
    ANTENNADIFFAREA 1.3034 LAYER Metal1 ;
    PORT
      LAYER Metal1 ;
        RECT 2.75 3.895 3.01 6.15 ;
    END
  END X
  PIN B
    DIRECTION INPUT ;
    USE SIGNAL ;
    ANTENNAMODEL OXIDE1 ;
      ANTENNAGATEAREA 1.1542 LAYER Metal1 ;
    PORT
      LAYER Metal1 ;
        RECT 1.16 3.39 1.49 5.19 ;
    END
  END B
  PIN A
    DIRECTION INPUT ;
    USE SIGNAL ;
    ANTENNAMODEL OXIDE1 ;
      ANTENNAGATEAREA 1.1542 LAYER Metal1 ;
    PORT
      LAYER Metal1 ;
        RECT 1.16 1.765 1.49 2.81 ;
    END
  END A
  OBS
      LAYER Metal1 ;
        RECT 0.22 0.22 0.48 1.19 ;
        RECT 0.22 1.375 2.235 1.555 ;
        RECT 0.22 1.555 0.405 4.35 ;
        RECT 0.22 4.35 0.48 6.15 ;
        RECT 0.695 3.39 1.16 3.92 ;
        RECT 1.05 0.93 1.31 1.375 ;
        RECT 1.49 2.51 1.855 2.81 ;
        RECT 1.91 3.895 2.17 6.825 ;
        RECT 1.915 0.22 2.175 1.19 ;
        RECT 2.065 1.555 2.235 1.745 ;
        RECT 2.065 1.745 2.615 2.32 ;
        RECT 2.745 0.93 3.01 1.53 ;
        RECT 2.845 1.53 3.01 3.895 ;
        RECT 3.685 0.22 3.945 1.53 ;
        RECT 3.685 3.895 3.945 6.825 ;
  END
END sg13g2_hv_or2_2

MACRO sg13g2_hv_or3_1
  CLASS CORE ;
  ORIGIN 0 0 ;
  FOREIGN sg13g2_hv_or3_1 0 0 ;
  SIZE 5.28 BY 7.14 ;
  SYMMETRY X Y ;
  SITE CoreSiteHV ;
  PIN A
    DIRECTION INPUT ;
    USE SIGNAL ;
    ANTENNAMODEL OXIDE1 ;
      ANTENNAGATEAREA 1.3275 LAYER Metal1 ;
    PORT
      LAYER Metal1 ;
        RECT 2.575 1.935 3.04 2.825 ;
    END
  END A
  PIN B
    DIRECTION INPUT ;
    USE SIGNAL ;
    ANTENNAMODEL OXIDE1 ;
      ANTENNAGATEAREA 1.3275 LAYER Metal1 ;
    PORT
      LAYER Metal1 ;
        RECT 1.41 1.935 2.2 2.825 ;
    END
  END B
  PIN C
    DIRECTION INPUT ;
    USE SIGNAL ;
    ANTENNAMODEL OXIDE1 ;
      ANTENNAGATEAREA 1.3275 LAYER Metal1 ;
    PORT
      LAYER Metal1 ;
        RECT 0.295 1.935 1.155 2.825 ;
    END
  END C
  PIN X
    DIRECTION OUTPUT ;
    USE SIGNAL ;
    ANTENNADIFFAREA 1.1662 LAYER Metal1 ;
    PORT
      LAYER Metal1 ;
        RECT 4.45 3.61 4.81 5.865 ;
    END
  END X
  PIN VDD
    DIRECTION INOUT ;
    USE POWER ;
    SHAPE ABUTMENT ;
    NETEXPR "VDD VDD!" ;
    PORT
      LAYER Metal1 ;
        RECT 0 6.825 5.28 7.36 ;
    END
  END VDD
  PIN VSS
    DIRECTION INOUT ;
    USE GROUND ;
    SHAPE ABUTMENT ;
    NETEXPR "VSS VSS!" ;
    PORT
      LAYER Metal1 ;
        RECT 0 -0.22 5.28 0.22 ;
    END
  END VSS
  OBS
      LAYER Metal1 ;
        RECT 0.385 1.04 0.645 1.54 ;
        RECT 0.385 1.54 2.925 1.545 ;
        RECT 0.385 1.545 3.805 1.755 ;
        RECT 0.385 3.295 3.805 3.79 ;
        RECT 0.385 3.79 0.645 5.575 ;
        RECT 1.215 0.22 1.475 1.3 ;
        RECT 2.085 1.04 2.925 1.54 ;
        RECT 2.81 4.22 3.73 6.825 ;
        RECT 3.535 0.22 3.805 1.3 ;
        RECT 3.625 1.755 3.805 1.95 ;
        RECT 3.625 1.95 4.47 2.725 ;
        RECT 3.625 2.725 3.805 3.295 ;
        RECT 4.52 1.035 4.81 1.645 ;
        RECT 4.65 1.645 4.81 3.61 ;
  END
END sg13g2_hv_or3_1

MACRO sg13g2_hv_or3_2
  CLASS CORE ;
  ORIGIN 0 0 ;
  FOREIGN sg13g2_hv_or3_2 0 0 ;
  SIZE 6.24 BY 7.14 ;
  SYMMETRY X Y ;
  SITE CoreSiteHV ;
  PIN A
    DIRECTION INPUT ;
    USE SIGNAL ;
    ANTENNAMODEL OXIDE1 ;
      ANTENNAGATEAREA 1.3275 LAYER Metal1 ;
    PORT
      LAYER Metal1 ;
        RECT 2.575 1.935 3.04 2.925 ;
    END
  END A
  PIN B
    DIRECTION INPUT ;
    USE SIGNAL ;
    ANTENNAMODEL OXIDE1 ;
      ANTENNAGATEAREA 1.3275 LAYER Metal1 ;
    PORT
      LAYER Metal1 ;
        RECT 1.41 1.935 2.2 2.925 ;
    END
  END B
  PIN C
    DIRECTION INPUT ;
    USE SIGNAL ;
    ANTENNAMODEL OXIDE1 ;
      ANTENNAGATEAREA 1.3275 LAYER Metal1 ;
    PORT
      LAYER Metal1 ;
        RECT 0.295 1.935 1.155 2.925 ;
    END
  END C
  PIN X
    DIRECTION OUTPUT ;
    USE SIGNAL ;
    ANTENNADIFFAREA 1.3034 LAYER Metal1 ;
    PORT
      LAYER Metal1 ;
        RECT 4.65 1.915 5.905 2.73 ;
    END
  END X
  PIN VDD
    DIRECTION INOUT ;
    USE POWER ;
    SHAPE ABUTMENT ;
    NETEXPR "VDD VDD!" ;
    PORT
      LAYER Metal1 ;
        RECT 0 6.825 6.24 7.36 ;
    END
  END VDD
  PIN VSS
    DIRECTION INOUT ;
    USE GROUND ;
    SHAPE ABUTMENT ;
    NETEXPR "VSS VSS!" ;
    PORT
      LAYER Metal1 ;
        RECT 0 -0.22 6.24 0.22 ;
    END
  END VSS
  OBS
      LAYER Metal1 ;
        RECT 0.385 1.04 0.645 1.54 ;
        RECT 0.385 1.54 2.925 1.545 ;
        RECT 0.385 1.545 3.805 1.755 ;
        RECT 0.385 3.37 3.805 3.79 ;
        RECT 0.385 3.79 0.645 5.575 ;
        RECT 1.215 0.22 1.475 1.32 ;
        RECT 2.085 1.04 2.925 1.54 ;
        RECT 2.81 4.22 3.73 6.825 ;
        RECT 3.535 0.22 3.805 1.3 ;
        RECT 3.625 1.755 3.805 2.225 ;
        RECT 3.625 2.225 4.47 2.725 ;
        RECT 3.625 2.725 3.805 3.37 ;
        RECT 4.45 3.595 4.885 5.865 ;
        RECT 4.52 1.035 4.885 1.64 ;
        RECT 4.65 1.64 4.885 1.915 ;
        RECT 4.65 2.73 4.885 3.595 ;
        RECT 5.535 3.61 5.795 6.825 ;
        RECT 5.55 0.22 5.81 1.64 ;
  END
END sg13g2_hv_or3_2

MACRO sg13g2_hv_or4_1
  CLASS CORE ;
  ORIGIN 0 0 ;
  FOREIGN sg13g2_hv_or4_1 0 0 ;
  SIZE 5.76 BY 7.14 ;
  SYMMETRY X Y ;
  SITE CoreSiteHV ;
  PIN A
    DIRECTION INPUT ;
    USE SIGNAL ;
    ANTENNAMODEL OXIDE1 ;
      ANTENNAGATEAREA 1.3275 LAYER Metal1 ;
    PORT
      LAYER Metal1 ;
        RECT 3.23 1.975 3.885 2.925 ;
    END
  END A
  PIN B
    DIRECTION INPUT ;
    USE SIGNAL ;
    ANTENNAMODEL OXIDE1 ;
      ANTENNAGATEAREA 1.3275 LAYER Metal1 ;
    PORT
      LAYER Metal1 ;
        RECT 2.39 1.975 2.98 2.925 ;
    END
  END B
  PIN C
    DIRECTION INPUT ;
    USE SIGNAL ;
    ANTENNAMODEL OXIDE1 ;
      ANTENNAGATEAREA 1.3275 LAYER Metal1 ;
    PORT
      LAYER Metal1 ;
        RECT 1.465 1.975 2.2 2.925 ;
    END
  END C
  PIN D
    DIRECTION INPUT ;
    USE SIGNAL ;
    ANTENNAMODEL OXIDE1 ;
      ANTENNAGATEAREA 1.3275 LAYER Metal1 ;
    PORT
      LAYER Metal1 ;
        RECT 0.32 1.975 1.195 2.925 ;
    END
  END D
  PIN X
    DIRECTION OUTPUT ;
    USE SIGNAL ;
    ANTENNADIFFAREA 1.1662 LAYER Metal1 ;
    PORT
      LAYER Metal1 ;
        RECT 4.755 3.31 5.1 5.83 ;
    END
  END X
  PIN VDD
    DIRECTION INOUT ;
    USE POWER ;
    SHAPE ABUTMENT ;
    NETEXPR "VDD VDD!" ;
    PORT
      LAYER Metal1 ;
        RECT 0 6.825 5.76 7.36 ;
    END
  END VDD
  PIN VSS
    DIRECTION INOUT ;
    USE GROUND ;
    SHAPE ABUTMENT ;
    NETEXPR "VSS VSS!" ;
    PORT
      LAYER Metal1 ;
        RECT 0 -0.22 5.76 0.22 ;
    END
  END VSS
  OBS
      LAYER Metal1 ;
        RECT 0.38 0.22 0.64 1.49 ;
        RECT 0.38 4.41 3.32 4.88 ;
        RECT 0.38 4.88 0.64 5.865 ;
        RECT 1.21 1.285 1.47 1.625 ;
        RECT 1.21 1.625 4.35 1.795 ;
        RECT 2.095 0.22 2.355 1.43 ;
        RECT 3.075 1.285 3.335 1.625 ;
        RECT 3.16 3.535 4.235 3.99 ;
        RECT 3.16 3.99 3.32 4.41 ;
        RECT 3.915 0.22 4.175 1.44 ;
        RECT 3.925 4.485 4.185 6.825 ;
        RECT 4.065 1.795 4.35 1.95 ;
        RECT 4.065 1.95 4.76 2.725 ;
        RECT 4.065 2.725 4.235 3.535 ;
        RECT 4.78 1.05 5.1 1.725 ;
        RECT 4.94 1.725 5.1 3.31 ;
  END
END sg13g2_hv_or4_1

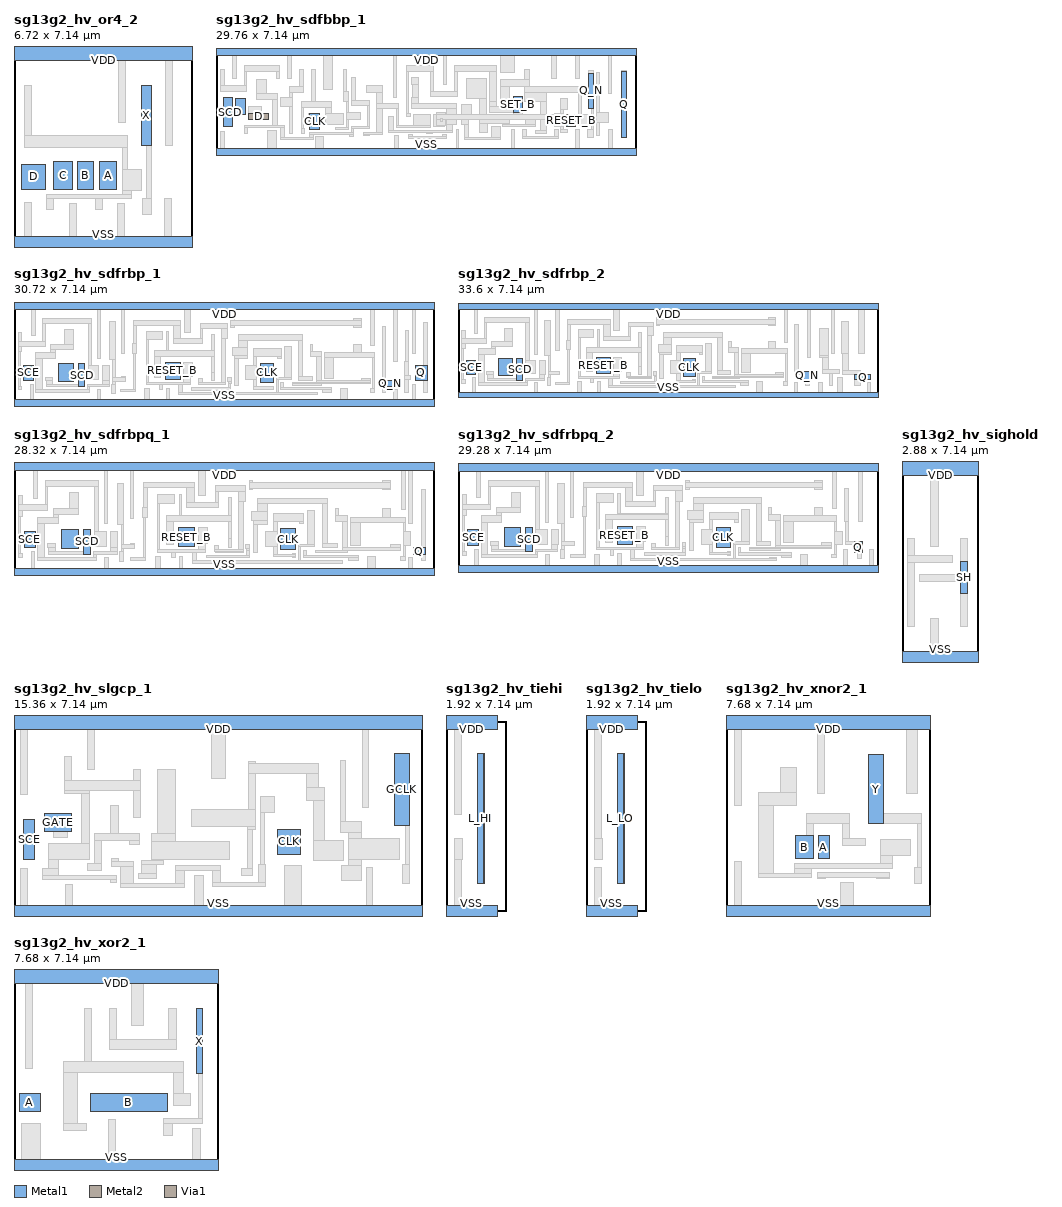
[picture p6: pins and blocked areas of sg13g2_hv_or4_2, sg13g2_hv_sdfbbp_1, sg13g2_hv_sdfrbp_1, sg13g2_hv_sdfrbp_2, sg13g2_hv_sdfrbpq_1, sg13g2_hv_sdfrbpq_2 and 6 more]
MACRO sg13g2_hv_or4_2
  CLASS CORE ;
  ORIGIN 0 0 ;
  FOREIGN sg13g2_hv_or4_2 0 0 ;
  SIZE 6.72 BY 7.14 ;
  SYMMETRY X Y ;
  SITE CoreSiteHV ;
  PIN A
    DIRECTION INPUT ;
    USE SIGNAL ;
    ANTENNAMODEL OXIDE1 ;
      ANTENNAGATEAREA 1.3275 LAYER Metal1 ;
    PORT
      LAYER Metal1 ;
        RECT 3.23 1.975 3.845 3.02 ;
    END
  END A
  PIN B
    DIRECTION INPUT ;
    USE SIGNAL ;
    ANTENNAMODEL OXIDE1 ;
      ANTENNAGATEAREA 1.3275 LAYER Metal1 ;
    PORT
      LAYER Metal1 ;
        RECT 2.39 1.975 2.98 3.01 ;
    END
  END B
  PIN C
    DIRECTION INPUT ;
    USE SIGNAL ;
    ANTENNAMODEL OXIDE1 ;
      ANTENNAGATEAREA 1.3275 LAYER Metal1 ;
    PORT
      LAYER Metal1 ;
        RECT 1.5 1.975 2.21 3.01 ;
    END
  END C
  PIN D
    DIRECTION INPUT ;
    USE SIGNAL ;
    ANTENNAMODEL OXIDE1 ;
      ANTENNAGATEAREA 1.3275 LAYER Metal1 ;
    PORT
      LAYER Metal1 ;
        RECT 0.265 1.975 1.195 2.925 ;
    END
  END D
  PIN X
    DIRECTION OUTPUT ;
    USE SIGNAL ;
    ANTENNADIFFAREA 1.3034 LAYER Metal1 ;
    PORT
      LAYER Metal1 ;
        RECT 4.805 3.61 5.15 5.865 ;
        RECT 4.8 3.61 4.805 5.865 ;
    END
  END X
  PIN VDD
    DIRECTION INOUT ;
    USE POWER ;
    SHAPE ABUTMENT ;
    NETEXPR "VDD VDD!" ;
    PORT
      LAYER Metal1 ;
        RECT 0 6.825 6.72 7.36 ;
    END
  END VDD
  PIN VSS
    DIRECTION INOUT ;
    USE GROUND ;
    SHAPE ABUTMENT ;
    NETEXPR "VSS VSS!" ;
    PORT
      LAYER Metal1 ;
        RECT 0 -0.22 6.72 0.22 ;
    END
  END VSS
  OBS
      LAYER Metal1 ;
        RECT 0.38 0.22 0.64 1.49 ;
        RECT 0.38 3.535 4.26 3.99 ;
        RECT 0.38 3.99 0.64 5.865 ;
        RECT 1.21 1.23 1.47 1.625 ;
        RECT 1.21 1.625 4.4 1.795 ;
        RECT 2.095 0.22 2.355 1.445 ;
        RECT 3.075 1.23 3.335 1.625 ;
        RECT 3.905 0.22 4.165 1.44 ;
        RECT 3.925 4.485 4.185 6.825 ;
        RECT 4.065 1.795 4.4 1.95 ;
        RECT 4.065 1.95 4.81 2.725 ;
        RECT 4.065 2.725 4.26 3.535 ;
        RECT 4.83 1.04 5.15 1.64 ;
        RECT 4.99 1.64 5.15 3.61 ;
        RECT 5.66 0.22 5.92 1.64 ;
        RECT 5.69 3.61 5.95 6.825 ;
  END
END sg13g2_hv_or4_2

MACRO sg13g2_hv_sdfbbp_1
  CLASS CORE ;
  ORIGIN 0 0 ;
  FOREIGN sg13g2_hv_sdfbbp_1 0 0 ;
  SIZE 29.76 BY 7.14 ;
  SYMMETRY X Y ;
  SITE CoreSiteHV ;
  PIN Q
    DIRECTION OUTPUT ;
    USE SIGNAL ;
    ANTENNADIFFAREA 1.1662 LAYER Metal1 ;
    PORT
      LAYER Metal1 ;
        RECT 28.725 1.02 29.115 5.72 ;
    END
  END Q
  PIN Q_N
    DIRECTION OUTPUT ;
    USE SIGNAL ;
    ANTENNADIFFAREA 1.1662 LAYER Metal1 ;
    PORT
      LAYER Metal1 ;
        RECT 26.41 3.09 26.77 5.565 ;
    END
  END Q_N
  PIN RESET_B
    DIRECTION INPUT ;
    USE SIGNAL ;
    ANTENNAMODEL OXIDE1 ;
      ANTENNAGATEAREA 0.8797 LAYER Metal1 ;
    PORT
      LAYER Metal1 ;
        RECT 24.845 1.81 25.485 2.665 ;
    END
  END RESET_B
  PIN SET_B
    DIRECTION INPUT ;
    USE SIGNAL ;
    ANTENNAMODEL OXIDE1 ;
      ANTENNAGATEAREA 2.5673 LAYER Metal1 ;
    PORT
      LAYER Metal1 ;
        RECT 21.08 2.795 21.71 3.92 ;
    END
  END SET_B
  PIN D
    DIRECTION INPUT ;
    USE SIGNAL ;
    ANTENNAPARTIALCUTAREA 0.0361 LAYER Via1 ;
    ANTENNAMODEL OXIDE1 ;
      ANTENNAGATEAREA 0.8797 LAYER Metal2 ;
    PORT
      LAYER Metal2 ;
        RECT 2.285 2.32 3.74 2.735 ;
      LAYER Via1 ;
        RECT 2.77 2.52 2.96 2.71 ;
    END
  END D
  PIN SCE
    DIRECTION INPUT ;
    USE SIGNAL ;
    ANTENNAMODEL OXIDE1 ;
      ANTENNAGATEAREA 1.7595 LAYER Metal1 ;
    PORT
      LAYER Metal1 ;
        RECT 1.37 2.625 2.07 3.775 ;
    END
  END SCE
  PIN SCD
    DIRECTION INPUT ;
    USE SIGNAL ;
    ANTENNAMODEL OXIDE1 ;
      ANTENNAGATEAREA 0.8797 LAYER Metal1 ;
    PORT
      LAYER Metal1 ;
        RECT 0.51 1.79 1.16 3.85 ;
    END
  END SCD
  PIN CLK
    DIRECTION INPUT ;
    USE SIGNAL ;
    ANTENNAMODEL OXIDE1 ;
      ANTENNAGATEAREA 1.5435 LAYER Metal1 ;
    PORT
      LAYER Metal1 ;
        RECT 6.645 1.59 7.335 2.725 ;
    END
  END CLK
  PIN VDD
    DIRECTION INPUT ;
    USE POWER ;
    SHAPE ABUTMENT ;
    NETEXPR "VDD VDD!" ;
    PORT
      LAYER Metal1 ;
        RECT 0 6.825 29.76 7.36 ;
    END
  END VDD
  PIN VSS
    DIRECTION INPUT ;
    USE GROUND ;
    SHAPE ABUTMENT ;
    NETEXPR "VSS VSS!" ;
    PORT
      LAYER Metal1 ;
        RECT 0 -0.22 29.76 0.22 ;
    END
  END VSS
  OBS
      LAYER Metal1 ;
        RECT 0.34 0.22 0.6 1.485 ;
        RECT 0.34 4.29 2.195 4.7 ;
        RECT 0.34 4.7 0.6 5.815 ;
        RECT 0.51 1.785 1.16 1.79 ;
        RECT 0.51 3.85 1.16 3.86 ;
        RECT 1.17 5.19 1.43 6.825 ;
        RECT 1.37 3.775 2.075 3.79 ;
        RECT 1.995 4.7 2.195 5.73 ;
        RECT 1.995 5.73 4.525 6.14 ;
        RECT 2 1.305 2.26 1.71 ;
        RECT 2 1.71 4.84 1.87 ;
        RECT 2.07 2.625 2.075 3.775 ;
        RECT 2.32 2.495 3.245 3.21 ;
        RECT 2.89 3.69 4.36 4.17 ;
        RECT 2.89 4.17 3.55 5.11 ;
        RECT 3.68 0.22 4.31 1.525 ;
        RECT 4.03 1.87 4.36 3.69 ;
        RECT 4.265 5.19 4.525 5.73 ;
        RECT 4.535 0.885 6.905 1.055 ;
        RECT 4.535 1.055 4.84 1.71 ;
        RECT 4.54 3.235 5.4 3.86 ;
        RECT 5.08 5.19 5.365 6.825 ;
        RECT 5.215 1.315 5.4 3.235 ;
        RECT 5.215 3.86 5.4 4.21 ;
        RECT 5.215 4.21 6.195 4.615 ;
        RECT 5.935 4.615 6.195 5.815 ;
        RECT 6.04 1.3 6.245 1.64 ;
        RECT 6.04 1.64 6.2 3.175 ;
        RECT 6.04 3.175 8.21 3.585 ;
        RECT 6.525 1.81 6.645 2.725 ;
        RECT 6.645 1.055 6.905 1.245 ;
        RECT 6.645 1.245 9.765 1.405 ;
        RECT 6.645 1.585 7.335 1.59 ;
        RECT 6.75 3.585 7.035 5.865 ;
        RECT 7.085 0.22 7.63 1.065 ;
        RECT 7.63 4.425 8.28 6.825 ;
        RECT 7.725 1.97 9.04 2.745 ;
        RECT 7.725 2.745 8.21 3.175 ;
        RECT 8.46 1.585 9.395 1.765 ;
        RECT 9.02 3.61 9.395 4.255 ;
        RECT 9.02 4.255 9.28 5.865 ;
        RECT 9.225 1.765 9.395 2.32 ;
        RECT 9.225 2.32 10.265 2.765 ;
        RECT 9.225 2.765 9.395 3.61 ;
        RECT 9.46 1.13 9.765 1.245 ;
        RECT 9.575 1.405 9.765 1.655 ;
        RECT 9.575 1.655 10.865 1.815 ;
        RECT 9.62 3.26 10.865 3.645 ;
        RECT 9.62 3.645 9.87 5.29 ;
        RECT 10.455 1.155 10.845 1.255 ;
        RECT 10.455 1.255 11.82 1.415 ;
        RECT 10.69 4.195 11.82 4.69 ;
        RECT 10.705 1.815 10.865 3.26 ;
        RECT 11.4 1.415 11.82 3.07 ;
        RECT 11.4 3.07 12.96 3.465 ;
        RECT 11.4 3.465 11.82 4.195 ;
        RECT 12.24 1.385 16.765 1.545 ;
        RECT 12.24 1.545 12.605 2.525 ;
        RECT 12.545 3.895 12.805 6.825 ;
        RECT 12.64 0.22 12.9 1.175 ;
        RECT 12.79 1.725 14.15 1.765 ;
        RECT 12.79 1.765 15.2 1.885 ;
        RECT 12.79 1.885 12.96 3.07 ;
        RECT 13.475 2.51 13.765 2.73 ;
        RECT 13.5 2.73 13.67 5.73 ;
        RECT 13.5 5.73 15.4 6.14 ;
        RECT 13.66 0.95 16.34 1.11 ;
        RECT 13.66 1.11 13.955 1.205 ;
        RECT 13.875 3.08 17.075 3.465 ;
        RECT 13.875 3.465 14.345 3.87 ;
        RECT 13.875 4.8 14.345 5.25 ;
        RECT 13.89 3.87 14.345 4.8 ;
        RECT 13.99 1.885 15.2 2.66 ;
        RECT 14.89 1.3 15.355 1.385 ;
        RECT 15.225 3.91 17.085 4.305 ;
        RECT 15.225 4.305 15.4 5.73 ;
        RECT 15.435 1.81 16.17 2.66 ;
        RECT 16.08 1.11 16.34 1.205 ;
        RECT 16.1 4.75 16.36 6.825 ;
        RECT 16.36 1.545 16.765 1.965 ;
        RECT 16.36 1.965 17.075 3.08 ;
        RECT 16.915 4.305 17.085 5.73 ;
        RECT 16.915 5.73 19.88 6.14 ;
        RECT 17.02 0.22 17.195 1.605 ;
        RECT 17.39 1.965 17.92 2.63 ;
        RECT 17.39 2.63 18.12 3.38 ;
        RECT 17.595 0.885 20.155 1.045 ;
        RECT 17.595 1.045 17.92 1.965 ;
        RECT 17.78 3.825 19.2 5.23 ;
        RECT 18.69 1.365 19.26 2.025 ;
        RECT 18.69 2.025 20.82 2.585 ;
        RECT 18.69 2.585 19.2 3.825 ;
        RECT 19.385 3.595 19.88 5.73 ;
        RECT 19.4 2.795 21.08 3.2 ;
        RECT 19.4 3.2 19.88 3.595 ;
        RECT 19.55 1.045 20.155 1.79 ;
        RECT 20.17 3.63 20.82 4.665 ;
        RECT 20.17 4.665 22.195 5.17 ;
        RECT 20.175 5.61 21.14 6.825 ;
        RECT 20.335 1.775 22.625 1.955 ;
        RECT 20.335 1.955 20.82 2.025 ;
        RECT 20.91 0.22 21.17 1.59 ;
        RECT 21.08 2.595 21.74 2.795 ;
        RECT 21.71 2.795 21.74 3.08 ;
        RECT 21.75 0.945 24.235 1.125 ;
        RECT 21.75 1.125 22.01 1.585 ;
        RECT 21.83 5.17 22.195 5.83 ;
        RECT 21.89 3.55 23.43 4.245 ;
        RECT 21.89 4.245 25.875 4.63 ;
        RECT 21.89 4.63 22.195 4.665 ;
        RECT 21.95 1.955 22.625 2.625 ;
        RECT 22.66 1.305 23.43 1.555 ;
        RECT 23.01 1.555 23.43 3.55 ;
        RECT 23.76 5.19 24.13 6.825 ;
        RECT 23.975 1.125 24.235 1.6 ;
        RECT 24.005 1.81 24.605 2.74 ;
        RECT 24.445 1.36 24.92 1.57 ;
        RECT 24.445 1.57 24.605 1.81 ;
        RECT 24.445 2.74 24.605 3.02 ;
        RECT 24.445 3.02 24.9 3.81 ;
        RECT 25.485 0.22 25.745 1.57 ;
        RECT 25.505 5.205 25.765 6.825 ;
        RECT 25.665 1.85 26.37 2.625 ;
        RECT 25.665 2.625 25.875 4.245 ;
        RECT 26.34 1.04 26.77 1.62 ;
        RECT 26.41 5.565 26.77 5.805 ;
        RECT 26.6 1.62 26.77 3.09 ;
        RECT 26.99 1.135 27.175 2.075 ;
        RECT 26.99 2.075 27.785 2.78 ;
        RECT 26.99 2.78 27.195 5.65 ;
        RECT 27.785 4.17 28.045 6.825 ;
        RECT 27.815 0.22 28.075 1.585 ;
        RECT 28.725 5.72 29.115 5.77 ;
      LAYER Metal2 ;
        RECT 15.625 1.885 16.285 2.32 ;
        RECT 15.625 2.32 24.425 2.655 ;
        RECT 15.625 2.655 16.285 2.825 ;
        RECT 24.135 1.9 24.425 2.32 ;
        RECT 24.135 2.655 24.425 2.74 ;
      LAYER Via1 ;
        RECT 15.885 2.175 16.075 2.365 ;
        RECT 24.195 2.47 24.385 2.66 ;
  END
END sg13g2_hv_sdfbbp_1

MACRO sg13g2_hv_sdfrbp_1
  CLASS CORE ;
  ORIGIN 0 0 ;
  FOREIGN sg13g2_hv_sdfrbp_1 0 0 ;
  SIZE 30.72 BY 7.14 ;
  SYMMETRY X Y ;
  SITE CoreSiteHV ;
  PIN RESET_B
    DIRECTION INPUT ;
    USE SIGNAL ;
    ANTENNAMODEL OXIDE1 ;
      ANTENNAGATEAREA 1.9305 LAYER Metal1 ;
    PORT
      LAYER Metal1 ;
        RECT 11.095 1.71 12.16 2.995 ;
    END
  END RESET_B
  PIN VSS
    DIRECTION INOUT ;
    USE GROUND ;
    SHAPE ABUTMENT ;
    NETEXPR "VSS VSS!" ;
    PORT
      LAYER Metal1 ;
        RECT 0 -0.22 30.72 0.22 ;
    END
  END VSS
  PIN VDD
    DIRECTION INOUT ;
    USE POWER ;
    SHAPE ABUTMENT ;
    NETEXPR "VDD VDD!" ;
    PORT
      LAYER Metal1 ;
        RECT 0 6.825 30.72 7.36 ;
    END
  END VDD
  PIN SCD
    DIRECTION INPUT ;
    USE SIGNAL ;
    ANTENNAMODEL OXIDE1 ;
      ANTENNAGATEAREA 1.4130 LAYER Metal1 ;
    PORT
      LAYER Metal1 ;
        RECT 4.695 1.19 5.19 2.885 ;
    END
  END SCD
  PIN Q
    DIRECTION OUTPUT ;
    USE SIGNAL ;
    ANTENNADIFFAREA 1.1662 LAYER Metal1 ;
    PORT
      LAYER Metal1 ;
        RECT 29.345 1.67 30.21 2.73 ;
    END
  END Q
  PIN CLK
    DIRECTION INPUT ;
    USE SIGNAL ;
    ANTENNAMODEL OXIDE1 ;
      ANTENNAGATEAREA 1.5435 LAYER Metal1 ;
    PORT
      LAYER Metal1 ;
        RECT 18 1.495 19.005 2.925 ;
    END
  END CLK
  PIN D
    DIRECTION INPUT ;
    USE SIGNAL ;
    ANTENNAMODEL OXIDE1 ;
      ANTENNAGATEAREA 1.4130 LAYER Metal1 ;
    PORT
      LAYER Metal1 ;
        RECT 3.225 1.58 4.345 2.885 ;
    END
  END D
  PIN Q_N
    DIRECTION OUTPUT ;
    USE SIGNAL ;
    ANTENNADIFFAREA 1.1662 LAYER Metal1 ;
    PORT
      LAYER Metal1 ;
        RECT 26.94 1.22 28.02 1.61 ;
    END
  END Q_N
  PIN SCE
    DIRECTION INPUT ;
    USE SIGNAL ;
    ANTENNAMODEL OXIDE1 ;
      ANTENNAGATEAREA 2.5673 LAYER Metal1 ;
    PORT
      LAYER Metal1 ;
        RECT 0.675 1.66 1.425 2.745 ;
    END
  END SCE
  OBS
      LAYER Metal1 ;
        RECT 0.295 0.96 0.575 1.22 ;
        RECT 0.295 1.22 0.455 3.75 ;
        RECT 0.295 3.75 0.575 4.135 ;
        RECT 0.295 4.135 2.28 4.52 ;
        RECT 0.295 4.52 0.575 5.19 ;
        RECT 1.175 0.22 1.41 1.37 ;
        RECT 1.295 4.95 1.555 6.825 ;
        RECT 1.605 0.77 5.54 0.99 ;
        RECT 1.605 0.99 2.09 3.27 ;
        RECT 1.605 3.27 3.015 3.705 ;
        RECT 2.12 4.52 2.28 5.78 ;
        RECT 2.12 5.78 5.685 6.19 ;
        RECT 2.27 1.63 2.8 1.89 ;
        RECT 2.35 1.19 4.695 1.36 ;
        RECT 2.35 1.36 2.8 1.63 ;
        RECT 2.68 3.705 3.015 3.91 ;
        RECT 2.68 3.91 4.38 4.29 ;
        RECT 3.725 4.29 4.38 5.35 ;
        RECT 5.37 0.99 5.54 1.19 ;
        RECT 5.37 1.19 6.95 1.36 ;
        RECT 5.425 1.7 6.215 2.745 ;
        RECT 5.425 2.745 5.685 5.78 ;
        RECT 6.095 0.22 6.355 1.005 ;
        RECT 6.125 3.27 6.325 6.825 ;
        RECT 6.5 1.36 6.95 1.68 ;
        RECT 6.5 1.68 6.995 2.725 ;
        RECT 6.95 3.175 7.405 5.96 ;
        RECT 7.13 0.73 7.405 1.37 ;
        RECT 7.215 1.37 7.405 1.605 ;
        RECT 7.215 1.605 8.13 1.86 ;
        RECT 7.215 1.86 7.405 3.175 ;
        RECT 7.825 0.805 8.885 1 ;
        RECT 7.83 3.595 8.085 6.825 ;
        RECT 7.87 1.86 8.13 1.91 ;
        RECT 8.655 3.655 8.99 4.33 ;
        RECT 8.725 1 8.885 3.655 ;
        RECT 8.725 4.33 8.99 5.67 ;
        RECT 8.725 5.67 12.18 6.055 ;
        RECT 9.545 0.22 9.875 1.045 ;
        RECT 9.675 1.33 12.9 1.49 ;
        RECT 9.675 1.49 9.835 4.615 ;
        RECT 9.675 4.615 10.835 5.24 ;
        RECT 10.295 1.865 10.74 3.43 ;
        RECT 10.295 3.43 14.65 3.81 ;
        RECT 10.615 0.975 10.875 1.33 ;
        RECT 11.13 0.22 11.39 1.075 ;
        RECT 11.14 3.81 14.65 3.835 ;
        RECT 11.14 3.835 11.32 5.24 ;
        RECT 11.66 4.33 13.77 4.71 ;
        RECT 11.66 4.71 12.18 5.67 ;
        RECT 12.005 0.6 22.175 0.765 ;
        RECT 12.005 0.765 12.33 1.33 ;
        RECT 12.41 1.49 12.9 1.915 ;
        RECT 12.41 1.915 13.04 2.995 ;
        RECT 12.445 5.145 12.92 6.825 ;
        RECT 12.98 0.945 15.86 1.12 ;
        RECT 13.495 1.385 15.445 1.49 ;
        RECT 13.495 1.49 13.8 1.8 ;
        RECT 13.61 4.71 13.77 5.445 ;
        RECT 13.61 5.445 15.62 5.83 ;
        RECT 13.62 1.33 15.445 1.385 ;
        RECT 14.465 1.67 14.685 2.255 ;
        RECT 14.465 2.255 14.65 3.43 ;
        RECT 14.465 3.835 14.65 5.01 ;
        RECT 15.15 1.49 15.445 4.725 ;
        RECT 15.15 4.725 15.62 5.445 ;
        RECT 15.625 1.6 15.89 1.86 ;
        RECT 15.68 1.12 15.86 1.46 ;
        RECT 15.68 1.46 15.89 1.6 ;
        RECT 15.85 5.54 16.11 5.66 ;
        RECT 15.85 5.66 25.415 6.045 ;
        RECT 15.85 6.045 16.11 6.165 ;
        RECT 16.015 3.44 17.1 4.065 ;
        RECT 16.15 1.295 16.41 3.225 ;
        RECT 16.15 3.225 17.1 3.44 ;
        RECT 16.42 4.065 17.1 4.59 ;
        RECT 16.42 4.59 21.13 4.975 ;
        RECT 16.965 1.7 17.76 2.745 ;
        RECT 17.5 1.015 19.005 1.185 ;
        RECT 17.5 1.185 17.76 1.7 ;
        RECT 17.5 2.745 17.76 3.43 ;
        RECT 17.5 3.43 19.54 3.97 ;
        RECT 18.77 0.97 19.005 1.015 ;
        RECT 18.77 1.185 19.005 1.23 ;
        RECT 19.185 0.765 19.345 1.715 ;
        RECT 19.185 1.715 20.29 1.885 ;
        RECT 19.28 3.26 19.54 3.43 ;
        RECT 19.525 0.965 23.215 1.125 ;
        RECT 19.525 1.125 19.695 1.47 ;
        RECT 19.76 1.885 20.29 4.16 ;
        RECT 20.345 1.305 22.49 1.435 ;
        RECT 20.345 1.435 26.05 1.475 ;
        RECT 20.775 1.67 21.8 1.93 ;
        RECT 20.775 1.93 21.13 4.59 ;
        RECT 21.655 3.38 22.47 3.79 ;
        RECT 21.655 3.79 21.86 4.28 ;
        RECT 21.74 0.765 22.175 0.785 ;
        RECT 22.14 1.475 26.05 1.625 ;
        RECT 22.14 1.625 22.47 3.38 ;
        RECT 22.57 0.785 23.215 0.965 ;
        RECT 22.7 1.815 23.38 3.32 ;
        RECT 22.7 3.32 26.39 3.705 ;
        RECT 23.85 0.22 24.375 1.045 ;
        RECT 24.835 3.705 25.405 4.27 ;
        RECT 24.835 5.54 25.415 5.66 ;
        RECT 24.835 6.045 25.415 6.165 ;
        RECT 25.395 1.625 26.05 1.825 ;
        RECT 26.04 0.785 26.39 1.045 ;
        RECT 26.11 4.185 26.37 6.825 ;
        RECT 26.23 1.045 26.39 3.32 ;
        RECT 26.94 0.75 27.2 1.22 ;
        RECT 26.94 1.61 27.2 5.625 ;
        RECT 27.77 0.22 28.03 1.01 ;
        RECT 27.77 3.03 28.03 6.825 ;
        RECT 28.595 0.75 28.86 1.695 ;
        RECT 28.595 1.695 29.02 2.025 ;
        RECT 28.595 2.025 28.86 3.03 ;
        RECT 28.6 3.03 28.86 5.29 ;
        RECT 29.12 0.22 29.375 1.37 ;
        RECT 29.12 3.645 29.38 6.825 ;
        RECT 29.945 0.755 30.21 1.67 ;
        RECT 29.95 2.73 30.21 5.9 ;
  END
END sg13g2_hv_sdfrbp_1

MACRO sg13g2_hv_sdfrbp_2
  CLASS CORE ;
  ORIGIN 0 0 ;
  FOREIGN sg13g2_hv_sdfrbp_2 0 0 ;
  SIZE 33.6 BY 7.14 ;
  SYMMETRY X Y ;
  SITE CoreSiteHV ;
  PIN RESET_B
    DIRECTION INPUT ;
    USE SIGNAL ;
    ANTENNAMODEL OXIDE1 ;
      ANTENNAGATEAREA 1.9305 LAYER Metal1 ;
    PORT
      LAYER Metal1 ;
        RECT 11.095 1.71 12.16 2.995 ;
    END
  END RESET_B
  PIN VSS
    DIRECTION INOUT ;
    USE GROUND ;
    SHAPE ABUTMENT ;
    NETEXPR "VSS VSS!" ;
    PORT
      LAYER Metal1 ;
        RECT 0 -0.22 33.6 0.22 ;
    END
  END VSS
  PIN VDD
    DIRECTION INOUT ;
    USE POWER ;
    SHAPE ABUTMENT ;
    NETEXPR "VDD VDD!" ;
    PORT
      LAYER Metal1 ;
        RECT 0 6.825 33.6 7.36 ;
    END
  END VDD
  PIN SCD
    DIRECTION INPUT ;
    USE SIGNAL ;
    ANTENNAMODEL OXIDE1 ;
      ANTENNAGATEAREA 1.4130 LAYER Metal1 ;
    PORT
      LAYER Metal1 ;
        RECT 4.695 1.19 5.19 2.885 ;
    END
  END SCD
  PIN Q
    DIRECTION OUTPUT ;
    USE SIGNAL ;
    ANTENNADIFFAREA 1.3034 LAYER Metal1 ;
    PORT
      LAYER Metal1 ;
        RECT 31.73 1.205 33.03 1.65 ;
    END
  END Q
  PIN CLK
    DIRECTION INPUT ;
    USE SIGNAL ;
    ANTENNAMODEL OXIDE1 ;
      ANTENNAGATEAREA 1.5435 LAYER Metal1 ;
    PORT
      LAYER Metal1 ;
        RECT 18 1.495 19.005 2.925 ;
    END
  END CLK
  PIN SCE
    DIRECTION INPUT ;
    USE SIGNAL ;
    ANTENNAMODEL OXIDE1 ;
      ANTENNAGATEAREA 2.5673 LAYER Metal1 ;
    PORT
      LAYER Metal1 ;
        RECT 0.675 1.66 1.425 2.745 ;
    END
  END SCE
  PIN Q_N
    DIRECTION OUTPUT ;
    USE SIGNAL ;
    ANTENNADIFFAREA 1.3034 LAYER Metal1 ;
    PORT
      LAYER Metal1 ;
        RECT 27.64 1.15 28.19 1.9 ;
    END
  END Q_N
  PIN D
    DIRECTION INPUT ;
    USE SIGNAL ;
    ANTENNAMODEL OXIDE1 ;
      ANTENNAGATEAREA 1.4130 LAYER Metal1 ;
    PORT
      LAYER Metal1 ;
        RECT 3.225 1.58 4.345 2.885 ;
    END
  END D
  OBS
      LAYER Metal1 ;
        RECT 0.295 0.96 0.575 1.22 ;
        RECT 0.295 1.22 0.455 3.75 ;
        RECT 0.295 3.75 0.575 4.135 ;
        RECT 0.295 4.135 2.28 4.52 ;
        RECT 0.295 4.52 0.575 5.19 ;
        RECT 1.175 0.22 1.41 1.37 ;
        RECT 1.295 4.95 1.555 6.825 ;
        RECT 1.605 0.77 5.54 0.99 ;
        RECT 1.605 0.99 2.09 3.27 ;
        RECT 1.605 3.27 3.015 3.705 ;
        RECT 2.12 4.52 2.28 5.78 ;
        RECT 2.12 5.78 5.685 6.19 ;
        RECT 2.27 1.63 2.8 1.89 ;
        RECT 2.35 1.19 4.695 1.36 ;
        RECT 2.35 1.36 2.8 1.63 ;
        RECT 2.68 3.705 3.015 3.91 ;
        RECT 2.68 3.91 4.38 4.29 ;
        RECT 3.725 4.29 4.38 5.35 ;
        RECT 5.37 0.99 5.54 1.19 ;
        RECT 5.37 1.19 6.95 1.36 ;
        RECT 5.425 1.7 6.215 2.745 ;
        RECT 5.425 2.745 5.685 5.78 ;
        RECT 6.095 0.22 6.355 1.005 ;
        RECT 6.125 3.27 6.325 6.825 ;
        RECT 6.5 1.36 6.95 1.68 ;
        RECT 6.5 1.68 6.995 2.725 ;
        RECT 6.95 3.175 7.405 5.96 ;
        RECT 7.13 0.73 7.405 1.37 ;
        RECT 7.215 1.37 7.405 1.65 ;
        RECT 7.215 1.65 8.13 1.91 ;
        RECT 7.215 1.91 7.405 3.175 ;
        RECT 7.825 0.805 8.885 1 ;
        RECT 7.83 3.595 8.085 6.825 ;
        RECT 8.655 3.655 8.99 4.33 ;
        RECT 8.725 1 8.885 3.655 ;
        RECT 8.725 4.33 8.99 5.67 ;
        RECT 8.725 5.67 12.18 6.055 ;
        RECT 9.545 0.22 9.875 1.045 ;
        RECT 9.675 1.33 12.9 1.49 ;
        RECT 9.675 1.49 9.835 4.615 ;
        RECT 9.675 4.615 10.835 5.24 ;
        RECT 10.295 1.865 10.74 3.43 ;
        RECT 10.295 3.43 14.65 3.81 ;
        RECT 10.615 0.975 10.875 1.33 ;
        RECT 11.13 0.22 11.39 1.075 ;
        RECT 11.14 3.81 14.65 3.835 ;
        RECT 11.14 3.835 11.32 5.24 ;
        RECT 11.66 4.33 13.77 4.71 ;
        RECT 11.66 4.71 12.18 5.67 ;
        RECT 12.005 0.6 22.175 0.765 ;
        RECT 12.005 0.765 12.33 1.33 ;
        RECT 12.41 1.49 12.9 1.915 ;
        RECT 12.41 1.915 13.04 2.995 ;
        RECT 12.445 5.145 12.92 6.825 ;
        RECT 12.98 0.945 15.86 1.12 ;
        RECT 13.495 1.385 15.445 1.49 ;
        RECT 13.495 1.49 13.8 1.8 ;
        RECT 13.61 4.71 13.77 5.445 ;
        RECT 13.61 5.445 15.62 5.83 ;
        RECT 13.62 1.33 15.445 1.385 ;
        RECT 14.465 1.67 14.685 2.255 ;
        RECT 14.465 2.255 14.65 3.43 ;
        RECT 14.465 3.835 14.65 5.01 ;
        RECT 15.15 1.49 15.445 4.725 ;
        RECT 15.15 4.725 15.62 5.445 ;
        RECT 15.625 1.6 15.89 1.86 ;
        RECT 15.68 1.12 15.86 1.46 ;
        RECT 15.68 1.46 15.89 1.6 ;
        RECT 15.85 5.54 16.11 5.66 ;
        RECT 15.85 5.66 25.415 6.045 ;
        RECT 15.85 6.045 16.11 6.165 ;
        RECT 16.015 3.44 17.1 4.065 ;
        RECT 16.15 1.295 16.41 3.225 ;
        RECT 16.15 3.225 17.1 3.44 ;
        RECT 16.42 4.065 17.1 4.59 ;
        RECT 16.42 4.59 21.13 4.975 ;
        RECT 16.965 1.7 17.76 2.745 ;
        RECT 17.5 1.015 19.005 1.185 ;
        RECT 17.5 1.185 17.76 1.7 ;
        RECT 17.5 2.745 17.76 3.43 ;
        RECT 17.5 3.43 19.54 3.97 ;
        RECT 18.77 0.97 19.005 1.015 ;
        RECT 18.77 1.185 19.005 1.23 ;
        RECT 19.185 0.765 19.345 1.715 ;
        RECT 19.185 1.715 20.29 1.885 ;
        RECT 19.28 3.26 19.54 3.43 ;
        RECT 19.525 0.965 23.215 1.125 ;
        RECT 19.525 1.125 19.695 1.47 ;
        RECT 19.76 1.885 20.29 4.16 ;
        RECT 20.345 1.305 22.49 1.435 ;
        RECT 20.345 1.435 26.05 1.475 ;
        RECT 20.775 1.67 21.8 1.93 ;
        RECT 20.775 1.93 21.13 4.59 ;
        RECT 21.655 3.38 22.47 3.79 ;
        RECT 21.655 3.79 21.86 4.28 ;
        RECT 21.74 0.765 22.175 0.785 ;
        RECT 22.14 1.475 26.05 1.625 ;
        RECT 22.14 1.625 22.47 3.38 ;
        RECT 22.57 0.785 23.215 0.965 ;
        RECT 22.7 1.815 23.38 3.32 ;
        RECT 22.7 3.32 26.39 3.705 ;
        RECT 23.85 0.22 24.375 1.045 ;
        RECT 24.835 3.705 25.405 4.27 ;
        RECT 24.835 5.54 25.415 5.66 ;
        RECT 24.835 6.045 25.415 6.165 ;
        RECT 25.395 1.625 26.05 1.825 ;
        RECT 26.04 0.785 26.39 1.045 ;
        RECT 26.11 4.185 26.37 6.825 ;
        RECT 26.23 1.045 26.39 3.32 ;
        RECT 26.89 0.22 27.13 1.01 ;
        RECT 26.94 1.68 27.64 1.9 ;
        RECT 26.94 1.9 27.225 5.625 ;
        RECT 27.83 0.75 28.13 1.15 ;
        RECT 27.94 3.03 28.225 6.825 ;
        RECT 28.85 0.22 29.135 1.01 ;
        RECT 28.945 3.03 29.645 3.18 ;
        RECT 28.945 3.18 29.62 5.29 ;
        RECT 29.155 1.695 30.54 2.025 ;
        RECT 29.155 2.025 29.645 3.03 ;
        RECT 29.685 0.75 29.97 1.695 ;
        RECT 29.84 3.285 30.1 6.825 ;
        RECT 30.35 0.22 30.795 1.37 ;
        RECT 30.67 3.285 31.24 5.9 ;
        RECT 30.795 1.675 32.195 1.935 ;
        RECT 30.795 1.935 31.24 3.285 ;
        RECT 31.73 0.755 32.195 1.205 ;
        RECT 31.73 1.65 32.195 1.675 ;
        RECT 32.07 3.285 32.535 6.825 ;
        RECT 32.755 0.22 33.03 1 ;
  END
END sg13g2_hv_sdfrbp_2

MACRO sg13g2_hv_sdfrbpq_1
  CLASS CORE ;
  ORIGIN 0 0 ;
  FOREIGN sg13g2_hv_sdfrbpq_1 0 0 ;
  SIZE 28.32 BY 7.14 ;
  SYMMETRY X Y ;
  SITE CoreSiteHV ;
  PIN Q
    DIRECTION OUTPUT ;
    USE SIGNAL ;
    ANTENNADIFFAREA 1.1662 LAYER Metal1 ;
    PORT
      LAYER Metal1 ;
        RECT 26.915 1.16 27.75 1.625 ;
    END
  END Q
  PIN CLK
    DIRECTION INPUT ;
    USE SIGNAL ;
    ANTENNAMODEL OXIDE1 ;
      ANTENNAGATEAREA 1.5435 LAYER Metal1 ;
    PORT
      LAYER Metal1 ;
        RECT 18 1.495 19.005 2.925 ;
    END
  END CLK
  PIN RESET_B
    DIRECTION INPUT ;
    USE SIGNAL ;
    ANTENNAMODEL OXIDE1 ;
      ANTENNAGATEAREA 1.9305 LAYER Metal1 ;
    PORT
      LAYER Metal1 ;
        RECT 11.095 1.71 12.16 2.995 ;
    END
  END RESET_B
  PIN SCD
    DIRECTION INPUT ;
    USE SIGNAL ;
    ANTENNAMODEL OXIDE1 ;
      ANTENNAGATEAREA 1.4130 LAYER Metal1 ;
    PORT
      LAYER Metal1 ;
        RECT 4.695 1.19 5.19 2.885 ;
    END
  END SCD
  PIN D
    DIRECTION INPUT ;
    USE SIGNAL ;
    ANTENNAMODEL OXIDE1 ;
      ANTENNAGATEAREA 1.4130 LAYER Metal1 ;
    PORT
      LAYER Metal1 ;
        RECT 3.225 1.58 4.345 2.885 ;
    END
  END D
  PIN SCE
    DIRECTION INPUT ;
    USE SIGNAL ;
    ANTENNAMODEL OXIDE1 ;
      ANTENNAGATEAREA 2.5673 LAYER Metal1 ;
    PORT
      LAYER Metal1 ;
        RECT 0.675 1.66 1.425 2.745 ;
    END
  END SCE
  PIN VSS
    DIRECTION INOUT ;
    USE GROUND ;
    SHAPE ABUTMENT ;
    NETEXPR "VSS VSS!" ;
    PORT
      LAYER Metal1 ;
        RECT 0 -0.22 28.32 0.22 ;
    END
  END VSS
  PIN VDD
    DIRECTION INOUT ;
    USE POWER ;
    SHAPE ABUTMENT ;
    NETEXPR "VDD VDD!" ;
    PORT
      LAYER Metal1 ;
        RECT 0 6.825 28.32 7.36 ;
    END
  END VDD
  OBS
      LAYER Metal1 ;
        RECT 0.295 0.96 0.575 1.22 ;
        RECT 0.295 1.22 0.455 3.75 ;
        RECT 0.295 3.75 0.575 4.135 ;
        RECT 0.295 4.135 2.28 4.52 ;
        RECT 0.295 4.52 0.575 5.19 ;
        RECT 1.175 0.22 1.41 1.37 ;
        RECT 1.295 4.95 1.555 6.825 ;
        RECT 1.605 0.77 5.54 0.99 ;
        RECT 1.605 0.99 2.09 3.27 ;
        RECT 1.605 3.27 3.015 3.705 ;
        RECT 2.12 4.52 2.28 5.78 ;
        RECT 2.12 5.78 5.685 6.19 ;
        RECT 2.27 1.63 2.8 1.89 ;
        RECT 2.35 1.19 4.695 1.36 ;
        RECT 2.35 1.36 2.8 1.63 ;
        RECT 2.68 3.705 3.015 3.91 ;
        RECT 2.68 3.91 4.38 4.29 ;
        RECT 3.725 4.29 4.38 5.35 ;
        RECT 5.37 0.99 5.54 1.19 ;
        RECT 5.37 1.19 6.95 1.36 ;
        RECT 5.425 1.7 6.215 2.745 ;
        RECT 5.425 2.745 5.685 5.78 ;
        RECT 6.095 0.22 6.355 1.005 ;
        RECT 6.125 3.27 6.325 6.825 ;
        RECT 6.5 1.36 6.95 1.68 ;
        RECT 6.5 1.68 6.995 2.725 ;
        RECT 6.95 3.175 7.405 5.96 ;
        RECT 7.13 0.73 7.405 1.37 ;
        RECT 7.215 1.37 7.405 1.605 ;
        RECT 7.215 1.605 8.13 1.86 ;
        RECT 7.215 1.86 7.405 3.175 ;
        RECT 7.825 0.805 8.885 1 ;
        RECT 7.83 3.595 8.085 6.825 ;
        RECT 7.87 1.86 8.13 1.91 ;
        RECT 8.655 3.655 8.99 4.33 ;
        RECT 8.725 1 8.885 3.655 ;
        RECT 8.725 4.33 8.99 5.67 ;
        RECT 8.725 5.67 12.18 6.055 ;
        RECT 9.545 0.22 9.875 1.045 ;
        RECT 9.675 1.33 12.9 1.49 ;
        RECT 9.675 1.49 9.835 4.615 ;
        RECT 9.675 4.615 10.835 5.24 ;
        RECT 10.295 1.865 10.74 3.43 ;
        RECT 10.295 3.43 14.65 3.81 ;
        RECT 10.615 0.975 10.875 1.33 ;
        RECT 11.13 0.22 11.39 1.075 ;
        RECT 11.14 3.81 14.65 3.835 ;
        RECT 11.14 3.835 11.32 5.24 ;
        RECT 11.66 4.33 13.77 4.71 ;
        RECT 11.66 4.71 12.18 5.67 ;
        RECT 12.005 0.6 22.175 0.765 ;
        RECT 12.005 0.765 12.33 1.33 ;
        RECT 12.41 1.49 12.9 1.915 ;
        RECT 12.41 1.915 13.04 2.995 ;
        RECT 12.445 5.145 12.92 6.825 ;
        RECT 12.98 0.945 15.86 1.12 ;
        RECT 13.495 1.385 15.445 1.49 ;
        RECT 13.495 1.49 13.8 1.8 ;
        RECT 13.61 4.71 13.77 5.445 ;
        RECT 13.61 5.445 15.62 5.83 ;
        RECT 13.62 1.33 15.445 1.385 ;
        RECT 14.465 1.67 14.685 2.255 ;
        RECT 14.465 2.255 14.65 3.43 ;
        RECT 14.465 3.835 14.65 5.01 ;
        RECT 15.15 1.49 15.445 4.725 ;
        RECT 15.15 4.725 15.62 5.445 ;
        RECT 15.625 1.6 15.89 1.86 ;
        RECT 15.68 1.12 15.86 1.46 ;
        RECT 15.68 1.46 15.89 1.6 ;
        RECT 15.85 5.54 16.11 5.66 ;
        RECT 15.85 5.66 25.415 6.045 ;
        RECT 15.85 6.045 16.11 6.165 ;
        RECT 16.015 3.44 17.1 4.065 ;
        RECT 16.15 1.295 16.41 3.225 ;
        RECT 16.15 3.225 17.1 3.44 ;
        RECT 16.42 4.065 17.1 4.59 ;
        RECT 16.42 4.59 21.13 4.975 ;
        RECT 16.965 1.7 17.76 2.745 ;
        RECT 17.5 1.015 19.005 1.185 ;
        RECT 17.5 1.185 17.76 1.7 ;
        RECT 17.5 2.745 17.76 3.43 ;
        RECT 17.5 3.43 19.54 3.97 ;
        RECT 18.77 0.97 19.005 1.015 ;
        RECT 18.77 1.185 19.005 1.23 ;
        RECT 19.185 0.765 19.345 1.715 ;
        RECT 19.185 1.715 20.29 1.885 ;
        RECT 19.28 3.26 19.54 3.43 ;
        RECT 19.525 0.965 23.215 1.125 ;
        RECT 19.525 1.125 19.695 1.47 ;
        RECT 19.76 1.885 20.29 4.16 ;
        RECT 20.345 1.305 22.49 1.435 ;
        RECT 20.345 1.435 26.05 1.475 ;
        RECT 20.775 1.67 21.8 1.93 ;
        RECT 20.775 1.93 21.13 4.59 ;
        RECT 21.655 3.38 22.47 3.79 ;
        RECT 21.655 3.79 21.86 4.28 ;
        RECT 21.74 0.765 22.175 0.785 ;
        RECT 22.14 1.475 26.05 1.625 ;
        RECT 22.14 1.625 22.47 3.38 ;
        RECT 22.57 0.785 23.215 0.965 ;
        RECT 22.7 1.815 23.38 3.32 ;
        RECT 22.7 3.32 26.39 3.705 ;
        RECT 23.85 0.22 24.375 1.045 ;
        RECT 24.835 3.705 25.405 4.27 ;
        RECT 24.835 5.54 25.415 5.66 ;
        RECT 24.835 6.045 25.415 6.165 ;
        RECT 25.395 1.625 26.05 1.825 ;
        RECT 26.04 0.785 26.39 1.045 ;
        RECT 26.11 4.185 26.37 6.825 ;
        RECT 26.23 1.045 26.39 1.77 ;
        RECT 26.23 1.77 26.76 2.715 ;
        RECT 26.23 2.715 26.39 3.32 ;
        RECT 26.63 0.22 26.89 0.97 ;
        RECT 26.63 3.27 26.89 6.825 ;
        RECT 27.46 0.75 27.72 1.16 ;
        RECT 27.46 1.625 27.72 5.53 ;
  END
END sg13g2_hv_sdfrbpq_1

MACRO sg13g2_hv_sdfrbpq_2
  CLASS CORE ;
  ORIGIN 0 0 ;
  FOREIGN sg13g2_hv_sdfrbpq_2 0 0 ;
  SIZE 29.28 BY 7.14 ;
  SYMMETRY X Y ;
  SITE CoreSiteHV ;
  PIN Q
    DIRECTION OUTPUT ;
    USE SIGNAL ;
    ANTENNADIFFAREA 1.3034 LAYER Metal1 ;
    PORT
      LAYER Metal1 ;
        RECT 27.64 1.15 28.19 1.9 ;
    END
  END Q
  PIN CLK
    DIRECTION INPUT ;
    USE SIGNAL ;
    ANTENNAMODEL OXIDE1 ;
      ANTENNAGATEAREA 1.5435 LAYER Metal1 ;
    PORT
      LAYER Metal1 ;
        RECT 18 1.495 19.005 2.925 ;
    END
  END CLK
  PIN RESET_B
    DIRECTION INPUT ;
    USE SIGNAL ;
    ANTENNAMODEL OXIDE1 ;
      ANTENNAGATEAREA 1.9305 LAYER Metal1 ;
    PORT
      LAYER Metal1 ;
        RECT 11.095 1.71 12.16 2.995 ;
    END
  END RESET_B
  PIN SCD
    DIRECTION INPUT ;
    USE SIGNAL ;
    ANTENNAMODEL OXIDE1 ;
      ANTENNAGATEAREA 1.4130 LAYER Metal1 ;
    PORT
      LAYER Metal1 ;
        RECT 4.695 1.19 5.19 2.885 ;
    END
  END SCD
  PIN D
    DIRECTION INPUT ;
    USE SIGNAL ;
    ANTENNAMODEL OXIDE1 ;
      ANTENNAGATEAREA 1.4130 LAYER Metal1 ;
    PORT
      LAYER Metal1 ;
        RECT 3.225 1.58 4.345 2.885 ;
    END
  END D
  PIN SCE
    DIRECTION INPUT ;
    USE SIGNAL ;
    ANTENNAMODEL OXIDE1 ;
      ANTENNAGATEAREA 2.5673 LAYER Metal1 ;
    PORT
      LAYER Metal1 ;
        RECT 0.675 1.66 1.425 2.745 ;
    END
  END SCE
  PIN VDD
    DIRECTION INOUT ;
    USE POWER ;
    SHAPE ABUTMENT ;
    NETEXPR "VDD VDD!" ;
    PORT
      LAYER Metal1 ;
        RECT 0 6.825 29.28 7.36 ;
    END
  END VDD
  PIN VSS
    DIRECTION INOUT ;
    USE GROUND ;
    SHAPE ABUTMENT ;
    NETEXPR "VSS VSS!" ;
    PORT
      LAYER Metal1 ;
        RECT 0 -0.22 29.28 0.22 ;
    END
  END VSS
  OBS
      LAYER Metal1 ;
        RECT 0.295 0.96 0.575 1.22 ;
        RECT 0.295 1.22 0.455 3.75 ;
        RECT 0.295 3.75 0.575 4.135 ;
        RECT 0.295 4.135 2.28 4.52 ;
        RECT 0.295 4.52 0.575 5.19 ;
        RECT 1.175 0.22 1.41 1.37 ;
        RECT 1.295 4.95 1.555 6.825 ;
        RECT 1.605 0.77 5.54 0.99 ;
        RECT 1.605 0.99 2.09 3.27 ;
        RECT 1.605 3.27 3.015 3.705 ;
        RECT 2.12 4.52 2.28 5.78 ;
        RECT 2.12 5.78 5.685 6.19 ;
        RECT 2.27 1.63 2.8 1.89 ;
        RECT 2.35 1.19 4.695 1.36 ;
        RECT 2.35 1.36 2.8 1.63 ;
        RECT 2.68 3.705 3.015 3.91 ;
        RECT 2.68 3.91 4.38 4.29 ;
        RECT 3.725 4.29 4.38 5.35 ;
        RECT 5.37 0.99 5.54 1.19 ;
        RECT 5.37 1.19 6.95 1.36 ;
        RECT 5.425 1.7 6.215 2.745 ;
        RECT 5.425 2.745 5.685 5.78 ;
        RECT 6.095 0.22 6.355 1.005 ;
        RECT 6.125 3.27 6.325 6.825 ;
        RECT 6.5 1.36 6.95 1.68 ;
        RECT 6.5 1.68 6.995 2.725 ;
        RECT 6.95 3.175 7.405 5.96 ;
        RECT 7.13 0.73 7.405 1.37 ;
        RECT 7.215 1.37 7.405 1.65 ;
        RECT 7.215 1.65 8.13 1.91 ;
        RECT 7.215 1.91 7.405 3.175 ;
        RECT 7.825 0.805 8.885 1 ;
        RECT 7.83 3.595 8.085 6.825 ;
        RECT 8.655 3.655 8.99 4.33 ;
        RECT 8.725 1 8.885 3.655 ;
        RECT 8.725 4.33 8.99 5.67 ;
        RECT 8.725 5.67 12.18 6.055 ;
        RECT 9.545 0.22 9.875 1.045 ;
        RECT 9.675 1.33 12.9 1.49 ;
        RECT 9.675 1.49 9.835 4.615 ;
        RECT 9.675 4.615 10.835 5.24 ;
        RECT 10.295 1.865 10.74 3.43 ;
        RECT 10.295 3.43 14.65 3.81 ;
        RECT 10.615 0.975 10.875 1.33 ;
        RECT 11.13 0.22 11.39 1.075 ;
        RECT 11.14 3.81 14.65 3.835 ;
        RECT 11.14 3.835 11.32 5.24 ;
        RECT 11.66 4.33 13.77 4.71 ;
        RECT 11.66 4.71 12.18 5.67 ;
        RECT 12.005 0.6 22.175 0.765 ;
        RECT 12.005 0.765 12.33 1.33 ;
        RECT 12.41 1.49 12.9 1.915 ;
        RECT 12.41 1.915 13.04 2.995 ;
        RECT 12.445 5.145 12.92 6.825 ;
        RECT 12.98 0.945 15.86 1.12 ;
        RECT 13.495 1.385 15.445 1.49 ;
        RECT 13.495 1.49 13.8 1.8 ;
        RECT 13.61 4.71 13.77 5.445 ;
        RECT 13.61 5.445 15.62 5.83 ;
        RECT 13.62 1.33 15.445 1.385 ;
        RECT 14.465 1.67 14.685 2.255 ;
        RECT 14.465 2.255 14.65 3.43 ;
        RECT 14.465 3.835 14.65 5.01 ;
        RECT 15.15 1.49 15.445 4.725 ;
        RECT 15.15 4.725 15.62 5.445 ;
        RECT 15.625 1.6 15.89 1.86 ;
        RECT 15.68 1.12 15.86 1.46 ;
        RECT 15.68 1.46 15.89 1.6 ;
        RECT 15.85 5.54 16.11 5.66 ;
        RECT 15.85 5.66 25.415 6.045 ;
        RECT 15.85 6.045 16.11 6.165 ;
        RECT 16.015 3.44 17.1 4.065 ;
        RECT 16.15 1.295 16.41 3.225 ;
        RECT 16.15 3.225 17.1 3.44 ;
        RECT 16.42 4.065 17.1 4.59 ;
        RECT 16.42 4.59 21.13 4.975 ;
        RECT 16.965 1.7 17.76 2.745 ;
        RECT 17.5 1.015 19.005 1.185 ;
        RECT 17.5 1.185 17.76 1.7 ;
        RECT 17.5 2.745 17.76 3.43 ;
        RECT 17.5 3.43 19.54 3.97 ;
        RECT 18.77 0.97 19.005 1.015 ;
        RECT 18.77 1.185 19.005 1.23 ;
        RECT 19.185 0.765 19.345 1.715 ;
        RECT 19.185 1.715 20.29 1.885 ;
        RECT 19.28 3.26 19.54 3.43 ;
        RECT 19.525 0.965 23.215 1.125 ;
        RECT 19.525 1.125 19.695 1.47 ;
        RECT 19.76 1.885 20.29 4.16 ;
        RECT 20.345 1.305 22.49 1.435 ;
        RECT 20.345 1.435 26.035 1.475 ;
        RECT 20.775 1.67 21.8 1.93 ;
        RECT 20.775 1.93 21.13 4.59 ;
        RECT 21.655 3.38 22.47 3.79 ;
        RECT 21.655 3.79 21.86 4.28 ;
        RECT 21.74 0.765 22.175 0.785 ;
        RECT 22.14 1.475 26.035 1.625 ;
        RECT 22.14 1.625 22.47 3.38 ;
        RECT 22.57 0.785 23.215 0.965 ;
        RECT 22.7 1.815 23.38 3.32 ;
        RECT 22.7 3.32 26.39 3.705 ;
        RECT 23.85 0.22 24.375 1.045 ;
        RECT 24.835 3.705 25.405 4.27 ;
        RECT 24.835 5.54 25.415 5.66 ;
        RECT 24.835 6.045 25.415 6.165 ;
        RECT 25.325 1.625 26.035 1.825 ;
        RECT 26.04 0.785 26.39 1.045 ;
        RECT 26.11 4.185 26.37 6.825 ;
        RECT 26.23 1.045 26.39 1.735 ;
        RECT 26.23 1.735 26.81 2.64 ;
        RECT 26.23 2.64 26.39 3.32 ;
        RECT 26.89 0.22 27.13 1.355 ;
        RECT 26.94 3.285 27.225 5.625 ;
        RECT 27.04 1.68 27.64 1.9 ;
        RECT 27.04 1.9 27.225 3.285 ;
        RECT 27.83 0.75 28.13 1.15 ;
        RECT 27.94 3.32 28.225 6.825 ;
        RECT 28.7 0.22 28.96 1.355 ;
  END
END sg13g2_hv_sdfrbpq_2

MACRO sg13g2_hv_sighold
  CLASS CORE ;
  ORIGIN 0 0 ;
  FOREIGN sg13g2_hv_sighold 0 0 ;
  SIZE 2.88 BY 7.14 ;
  SYMMETRY X Y ;
  SITE CoreSiteHV ;
  PIN VDD
    DIRECTION INOUT ;
    USE POWER ;
    SHAPE ABUTMENT ;
    NETEXPR "VDD VDD!" ;
    PORT
      LAYER Metal1 ;
        RECT 0 6.825 2.88 7.36 ;
    END
  END VDD
  PIN VSS
    DIRECTION INOUT ;
    USE GROUND ;
    SHAPE ABUTMENT ;
    NETEXPR "VSS VSS!" ;
    PORT
      LAYER Metal1 ;
        RECT 0 -0.22 2.88 0.22 ;
    END
  END VSS
  PIN SH
    DIRECTION INOUT ;
    USE SIGNAL ;
    ANTENNADIFFAREA 0.3468 LAYER Metal1 ;
    PORT
      LAYER Metal1 ;
        RECT 2.19 2.4 2.45 3.6 ;
    END
  END SH
  OBS
      LAYER Metal1 ;
        RECT 0.2 1.14 0.46 3.55 ;
        RECT 0.2 3.55 1.91 3.81 ;
        RECT 0.2 3.81 0.46 4.44 ;
        RECT 0.64 2.85 2.19 3.11 ;
        RECT 1.08 0.22 1.36 1.44 ;
        RECT 1.08 4.14 1.36 6.825 ;
        RECT 2.19 1.14 2.45 2.4 ;
        RECT 2.19 3.6 2.45 4.44 ;
  END
END sg13g2_hv_sighold

MACRO sg13g2_hv_slgcp_1
  CLASS CORE ;
  ORIGIN 0 0 ;
  FOREIGN sg13g2_hv_slgcp_1 0 0 ;
  SIZE 15.36 BY 7.14 ;
  SYMMETRY X Y ;
  SITE CoreSiteHV ;
  PIN GATE
    DIRECTION INPUT ;
    USE SIGNAL ;
    ANTENNAMODEL OXIDE1 ;
      ANTENNAGATEAREA 1.1542 LAYER Metal1 ;
    PORT
      LAYER Metal1 ;
        RECT 1.14 2.985 2.165 3.655 ;
    END
  END GATE
  PIN SCE
    DIRECTION INPUT ;
    USE SIGNAL ;
    ANTENNAMODEL OXIDE1 ;
      ANTENNAGATEAREA 1.1542 LAYER Metal1 ;
    PORT
      LAYER Metal1 ;
        RECT 0.355 1.94 0.775 3.43 ;
    END
  END SCE
  PIN CLK
    DIRECTION INPUT ;
    USE SIGNAL ;
    ANTENNAMODEL OXIDE1 ;
      ANTENNAGATEAREA 2.4345 LAYER Metal1 ;
    PORT
      LAYER Metal1 ;
        RECT 9.89 2.125 10.77 3.08 ;
    END
  END CLK
  PIN GCLK
    DIRECTION OUTPUT ;
    USE SIGNAL ;
    ANTENNADIFFAREA 1.1662 LAYER Metal1 ;
    PORT
      LAYER Metal1 ;
        RECT 14.29 3.225 14.87 5.91 ;
    END
  END GCLK
  PIN VDD
    DIRECTION INOUT ;
    USE POWER ;
    SHAPE ABUTMENT ;
    NETEXPR "VDD VDD!" ;
    PORT
      LAYER Metal1 ;
        RECT 0 6.825 15.36 7.36 ;
    END
  END VDD
  PIN VSS
    DIRECTION INOUT ;
    USE GROUND ;
    SHAPE ABUTMENT ;
    NETEXPR "VSS VSS!" ;
    PORT
      LAYER Metal1 ;
        RECT 0 -0.22 15.36 0.22 ;
    END
  END VSS
  OBS
      LAYER Metal1 ;
        RECT 0.23 0.22 0.49 1.595 ;
        RECT 0.23 4.375 0.49 6.825 ;
        RECT 1.06 1.185 3.84 1.35 ;
        RECT 1.06 1.35 1.655 1.61 ;
        RECT 1.29 1.61 1.655 1.95 ;
        RECT 1.29 1.95 2.83 2.555 ;
        RECT 1.5 2.78 1.995 2.985 ;
        RECT 1.89 4.425 2.83 4.51 ;
        RECT 1.89 4.51 4.74 4.905 ;
        RECT 1.89 4.905 2.15 5.815 ;
        RECT 1.92 0.22 2.18 1.005 ;
        RECT 2.545 2.555 2.83 4.425 ;
        RECT 2.78 1.53 3.305 1.77 ;
        RECT 2.78 5.335 3.04 6.825 ;
        RECT 3.01 1.77 3.305 2.64 ;
        RECT 3.01 2.64 4.725 2.925 ;
        RECT 3.615 2.925 3.915 3.97 ;
        RECT 3.62 1.085 3.84 1.185 ;
        RECT 3.68 1.68 4.5 1.85 ;
        RECT 3.68 1.85 3.925 1.975 ;
        RECT 4.02 0.88 6.41 1.04 ;
        RECT 4.02 1.04 4.5 1.68 ;
        RECT 4.35 2.515 4.725 2.64 ;
        RECT 4.48 3.5 4.74 4.51 ;
        RECT 4.48 4.905 4.74 5.325 ;
        RECT 4.68 1.22 5.34 1.42 ;
        RECT 4.795 1.42 5.34 1.745 ;
        RECT 4.795 1.745 5.605 1.9 ;
        RECT 5.165 1.9 5.605 1.93 ;
        RECT 5.165 1.93 8.09 2.595 ;
        RECT 5.165 2.595 6.06 2.925 ;
        RECT 5.385 2.925 6.06 5.325 ;
        RECT 6.06 1.04 6.41 1.535 ;
        RECT 6.06 1.535 7.775 1.695 ;
        RECT 6.66 3.19 9.07 3.81 ;
        RECT 6.78 0.22 7.11 1.34 ;
        RECT 7.42 4.965 7.945 6.825 ;
        RECT 7.475 0.905 9.455 1.075 ;
        RECT 7.475 1.075 7.775 1.535 ;
        RECT 8.54 1.34 8.955 1.6 ;
        RECT 8.78 1.6 8.955 3.08 ;
        RECT 8.78 3.08 9.07 3.19 ;
        RECT 8.81 3.81 9.07 5.155 ;
        RECT 8.81 5.155 11.45 5.54 ;
        RECT 8.81 5.54 9.07 5.635 ;
        RECT 9.17 1.075 9.455 1.74 ;
        RECT 9.265 1.74 9.425 3.69 ;
        RECT 9.265 3.69 9.8 4.315 ;
        RECT 10.17 0.22 10.81 1.705 ;
        RECT 10.975 4.16 11.66 4.65 ;
        RECT 10.975 4.65 11.45 5.155 ;
        RECT 11.255 1.89 12.385 2.635 ;
        RECT 11.255 2.635 11.66 4.16 ;
        RECT 12.28 2.935 13.045 3.345 ;
        RECT 12.28 3.345 12.475 5.66 ;
        RECT 12.31 1.14 13.055 1.7 ;
        RECT 12.565 1.7 13.055 1.95 ;
        RECT 12.565 1.95 14.48 2.725 ;
        RECT 12.565 2.725 13.045 2.935 ;
        RECT 13.08 3.885 13.34 6.825 ;
        RECT 13.235 0.22 13.465 1.65 ;
        RECT 14.61 1.05 14.87 1.73 ;
        RECT 14.71 1.73 14.87 3.225 ;
  END
END sg13g2_hv_slgcp_1

MACRO sg13g2_hv_tiehi
  CLASS CORE ;
  ORIGIN 0 0 ;
  FOREIGN sg13g2_hv_tiehi 0 0 ;
  SIZE 1.92 BY 7.14 ;
  SYMMETRY X Y ;
  SITE CoreSiteHV ;
  PIN VDD
    DIRECTION INOUT ;
    USE POWER ;
    SHAPE ABUTMENT ;
    NETEXPR "VDD VDD!" ;
    PORT
      LAYER Metal1 ;
        RECT 0 6.825 1.92 7.36 ;
    END
  END VDD
  PIN VSS
    DIRECTION INOUT ;
    USE GROUND ;
    SHAPE ABUTMENT ;
    NETEXPR "VSS VSS!" ;
    PORT
      LAYER Metal1 ;
        RECT 0 -0.22 1.92 0.22 ;
    END
  END VSS
  PIN L_HI
    DIRECTION OUTPUT ;
    USE SIGNAL ;
    ANTENNADIFFAREA 1.1662 LAYER Metal1 ;
    PORT
      LAYER Metal1 ;
        RECT 1.175 1.04 1.405 5.9 ;
        RECT 1.405 1.04 1.44 5.9 ;
    END
  END L_HI
  OBS
      LAYER Metal1 ;
        RECT 0.31 1.95 0.625 2.725 ;
        RECT 0.33 0.22 0.59 1.95 ;
        RECT 0.33 3.645 0.59 6.825 ;
  END
END sg13g2_hv_tiehi

MACRO sg13g2_hv_tielo
  CLASS CORE ;
  ORIGIN 0 0 ;
  FOREIGN sg13g2_hv_tielo 0 0 ;
  SIZE 1.92 BY 7.14 ;
  SYMMETRY X Y ;
  SITE CoreSiteHV ;
  PIN VDD
    DIRECTION INOUT ;
    USE POWER ;
    SHAPE ABUTMENT ;
    NETEXPR "VDD VDD!" ;
    PORT
      LAYER Metal1 ;
        RECT 0 6.825 1.92 7.36 ;
    END
  END VDD
  PIN VSS
    DIRECTION INOUT ;
    USE GROUND ;
    SHAPE ABUTMENT ;
    NETEXPR "VSS VSS!" ;
    PORT
      LAYER Metal1 ;
        RECT 0 -0.22 1.92 0.22 ;
    END
  END VSS
  PIN L_LO
    DIRECTION OUTPUT ;
    USE SIGNAL ;
    ANTENNADIFFAREA 1.1662 LAYER Metal1 ;
    PORT
      LAYER Metal1 ;
        RECT 1.175 1.04 1.405 5.9 ;
        RECT 1.405 1.04 1.44 5.9 ;
    END
  END L_LO
  OBS
      LAYER Metal1 ;
        RECT 0.31 1.95 0.625 2.725 ;
        RECT 0.33 0.22 0.59 1.64 ;
        RECT 0.33 2.725 0.59 6.825 ;
  END
END sg13g2_hv_tielo

MACRO sg13g2_hv_xnor2_1
  CLASS CORE ;
  ORIGIN 0 0 ;
  FOREIGN sg13g2_hv_xnor2_1 0 0 ;
  SIZE 7.68 BY 7.14 ;
  SYMMETRY X Y ;
  SITE CoreSiteHV ;
  PIN Y
    DIRECTION OUTPUT ;
    USE SIGNAL ;
    ANTENNADIFFAREA 2.0808 LAYER Metal1 ;
    PORT
      LAYER Metal1 ;
        RECT 5.365 3.27 5.91 5.865 ;
    END
  END Y
  PIN A
    DIRECTION INPUT ;
    USE SIGNAL ;
    ANTENNAMODEL OXIDE1 ;
      ANTENNAGATEAREA 2.7382 LAYER Metal1 ;
    PORT
      LAYER Metal1 ;
        RECT 3.485 1.955 3.875 2.825 ;
    END
  END A
  PIN B
    DIRECTION INPUT ;
    USE SIGNAL ;
    ANTENNAMODEL OXIDE1 ;
      ANTENNAGATEAREA 2.7382 LAYER Metal1 ;
    PORT
      LAYER Metal1 ;
        RECT 2.615 1.955 3.305 2.825 ;
    END
  END B
  PIN VDD
    DIRECTION INOUT ;
    USE POWER ;
    SHAPE ABUTMENT ;
    NETEXPR "VDD VDD!" ;
    PORT
      LAYER Metal1 ;
        RECT 0 6.825 7.68 7.36 ;
    END
  END VDD
  PIN VSS
    DIRECTION INOUT ;
    USE GROUND ;
    SHAPE ABUTMENT ;
    NETEXPR "VSS VSS!" ;
    PORT
      LAYER Metal1 ;
        RECT 0 -0.22 7.68 0.22 ;
    END
  END VSS
  OBS
      LAYER Metal1 ;
        RECT 0.32 0.22 0.585 1.85 ;
        RECT 0.32 3.955 0.58 6.825 ;
        RECT 1.21 1.265 3.195 1.425 ;
        RECT 1.21 1.425 1.795 3.955 ;
        RECT 1.21 3.955 2.665 4.435 ;
        RECT 2.045 4.435 2.665 5.395 ;
        RECT 2.575 1.425 3.195 1.61 ;
        RECT 2.575 1.61 6.255 1.77 ;
        RECT 3.02 2.825 3.305 3.27 ;
        RECT 3.02 3.27 4.65 3.655 ;
        RECT 3.45 1.23 3.75 1.26 ;
        RECT 3.45 1.26 6.135 1.43 ;
        RECT 3.45 4.425 3.71 6.825 ;
        RECT 4.31 0.22 4.805 1.08 ;
        RECT 4.365 2.48 5.245 2.74 ;
        RECT 4.365 2.74 4.65 3.27 ;
        RECT 5.65 1.22 6.135 1.26 ;
        RECT 5.815 1.77 6.255 2.075 ;
        RECT 5.815 2.075 6.94 2.69 ;
        RECT 5.91 3.27 7.34 3.655 ;
        RECT 6.765 4.425 7.21 6.825 ;
        RECT 7.085 1.04 7.34 1.64 ;
        RECT 7.18 1.64 7.34 3.27 ;
  END
END sg13g2_hv_xnor2_1

MACRO sg13g2_hv_xor2_1
  CLASS CORE ;
  ORIGIN 0 0 ;
  FOREIGN sg13g2_hv_xor2_1 0 0 ;
  SIZE 7.68 BY 7.14 ;
  SYMMETRY X Y ;
  SITE CoreSiteHV ;
  PIN B
    DIRECTION INPUT ;
    USE SIGNAL ;
    ANTENNAMODEL OXIDE1 ;
      ANTENNAGATEAREA 2.8710 LAYER Metal1 ;
    PORT
      LAYER Metal1 ;
        RECT 2.875 2.025 5.765 2.705 ;
    END
  END B
  PIN A
    DIRECTION INPUT ;
    USE SIGNAL ;
    ANTENNAMODEL OXIDE1 ;
      ANTENNAGATEAREA 2.8710 LAYER Metal1 ;
    PORT
      LAYER Metal1 ;
        RECT 0.2 2.025 0.98 2.705 ;
    END
  END A
  PIN X
    DIRECTION OUTPUT ;
    USE SIGNAL ;
    ANTENNADIFFAREA 1.4178 LAYER Metal1 ;
    PORT
      LAYER Metal1 ;
        RECT 6.84 3.45 7.1 5.865 ;
    END
  END X
  PIN VDD
    DIRECTION INOUT ;
    USE POWER ;
    SHAPE ABUTMENT ;
    NETEXPR "VDD VDD!" ;
    PORT
      LAYER Metal1 ;
        RECT 0 6.825 7.68 7.36 ;
    END
  END VDD
  PIN VSS
    DIRECTION INOUT ;
    USE GROUND ;
    SHAPE ABUTMENT ;
    NETEXPR "VSS VSS!" ;
    PORT
      LAYER Metal1 ;
        RECT 0 -0.22 7.68 0.22 ;
    END
  END VSS
  OBS
      LAYER Metal1 ;
        RECT 0.285 0.22 0.98 1.55 ;
        RECT 0.435 3.61 0.695 6.825 ;
        RECT 1.855 1.29 2.71 1.55 ;
        RECT 1.855 1.55 2.395 3.49 ;
        RECT 1.855 3.49 6.365 3.895 ;
        RECT 2.665 3.895 2.925 5.865 ;
        RECT 3.565 0.22 3.825 1.7 ;
        RECT 3.585 4.33 6.125 4.71 ;
        RECT 3.585 4.71 3.845 5.865 ;
        RECT 4.415 5.24 4.88 6.825 ;
        RECT 5.6 1.1 5.975 1.545 ;
        RECT 5.6 1.545 7.1 1.745 ;
        RECT 5.815 4.71 6.125 5.865 ;
        RECT 5.985 2.225 6.645 2.705 ;
        RECT 5.985 2.705 6.365 3.49 ;
        RECT 6.715 0.22 7.02 1.365 ;
        RECT 6.92 1.745 7.1 3.45 ;
  END
END sg13g2_hv_xor2_1

END LIBRARY
